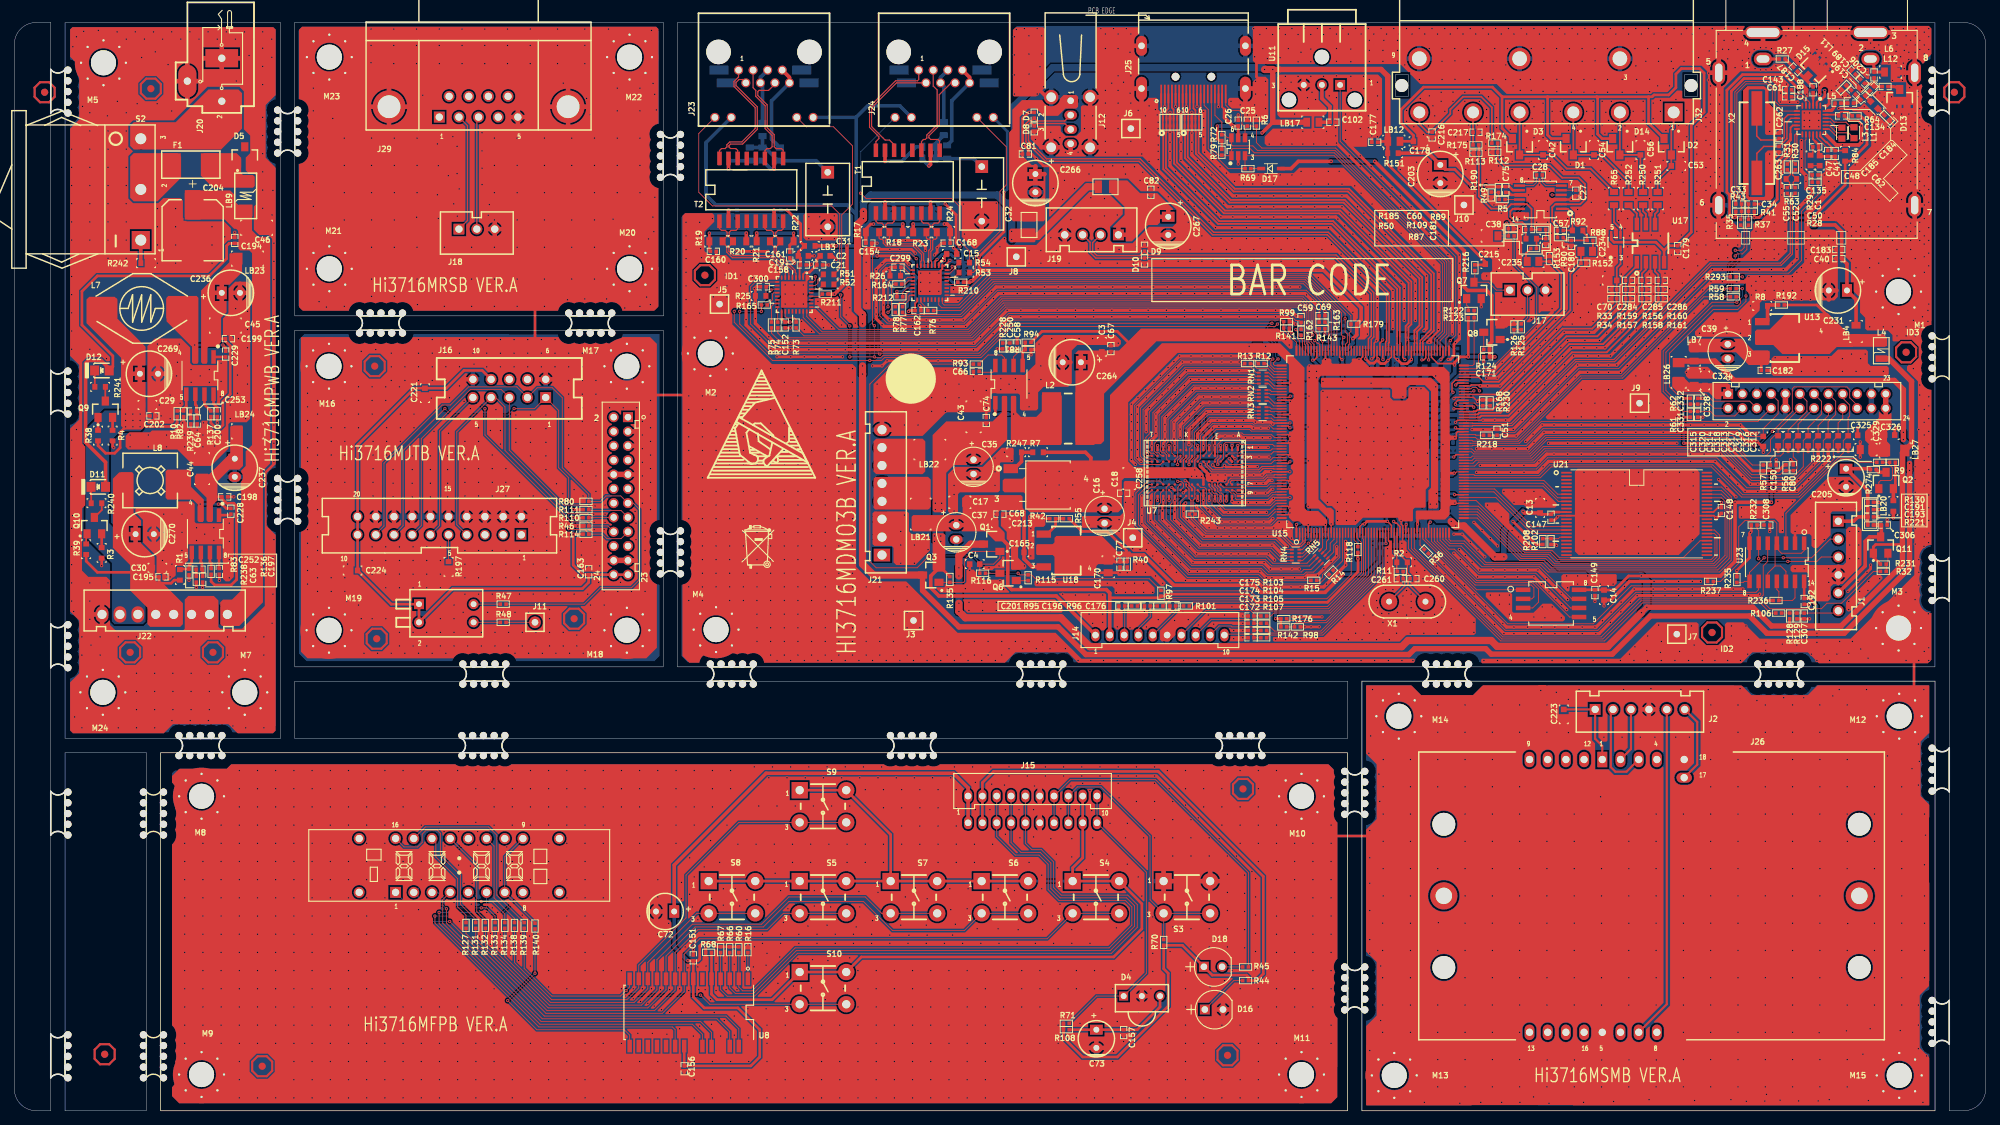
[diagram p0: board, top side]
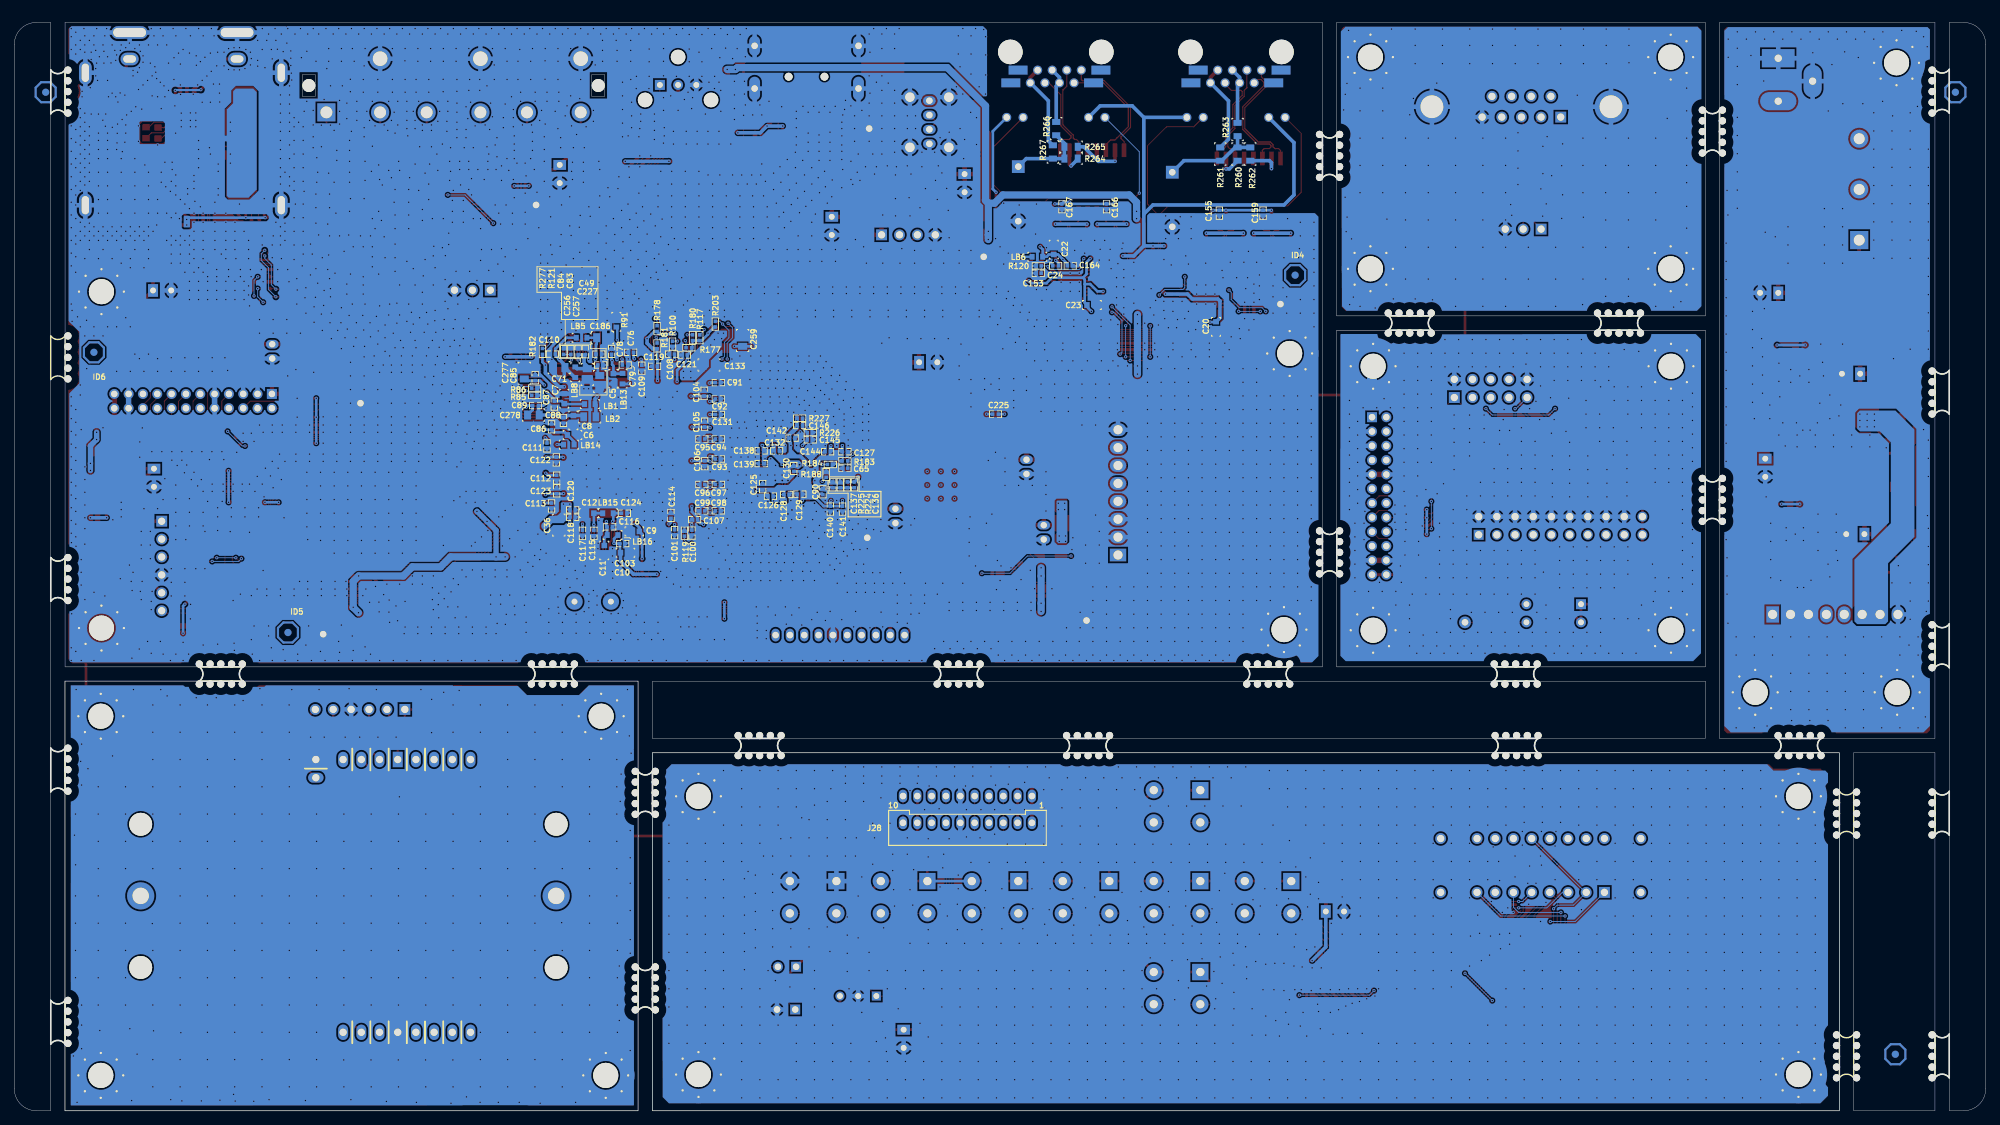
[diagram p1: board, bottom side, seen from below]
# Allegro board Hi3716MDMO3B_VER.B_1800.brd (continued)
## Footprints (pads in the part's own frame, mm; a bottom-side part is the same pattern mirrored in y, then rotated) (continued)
SOT23
  rect 1.016x1.27 smd: 1(-1.016,-1.143) 2(1.016,-1.143) 3(0,1.143)
SOT23A-6L
  rect 0.635x1.27 smd: 1(-0.95,-1.25) 2(0,-1.25) 3(0.95,-1.25) 4(0.95,1.25) 5(0,1.25) 6(-0.95,1.25)
SOT223A
  rect 1.016x2.032 smd: 1(-2.286,-3.15) 2(0,-3.15) 3(2.286,-3.15)
  rect 3.302x2.032 smd: 4(0,3.15)
SPL0707B
  rect 1.651x2.286 smd: 1(-3.302,0) 2(3.302,0)
SPL1209
  rect 4.064x2.794 smd: 1(-5.461,0) 2(5.461,0)
SR0402
  rect 0.508x0.508 smd: 1(-0.406,0) 2(0.406,0)
SR0603
  rect 0.711x0.813 smd: 1(-0.737,0) 2(0.737,0)
SR0805
  rect 0.838x1.143 smd: 1(-0.927,0) 2(0.927,0)
SRN8-0804
  rect 0.279x0.533 smd: 1(-0.762,-0.521) 2(-0.254,-0.521) 3(0.254,-0.521) 4(0.762,-0.521) 5(0.762,0.521) 6(0.254,0.521) 7(-0.254,0.521) 8(-0.762,0.521)
STFM16-50-285
  rect 0.635x1.905 smd: 1(-4.445,-4.381) 2(-3.175,-4.381) 3(-1.905,-4.381) 4(-0.635,-4.381) 5(0.635,-4.381) 6(1.905,-4.381) 7(3.175,-4.381) 8(4.445,-4.381) 9(4.445,4.381) 10(3.175,4.381) 11(1.905,4.381) 12(0.635,4.381) 13(-0.635,4.381) 14(-1.905,4.381) 15(-3.175,4.381) 16(-4.445,4.381)
SW4-PUSH
  rect 2.286x2.286 hole 1.143: 1(-3.25,2.25)
  round 2.286 hole 1.143: 2(3.25,2.25) 3(-3.25,-2.25) 4(3.25,-2.25)
SX2-1205
  rect 4.826x1.524 smd: 1(-4.85,0) 2(4.85,0)
TO-252
  rect 1.27x2.032 smd: 1(-2.285,-3.375) 2(0,-3.375) 3(2.285,-3.375)
  rect 5.715x5.842 smd: 4(0,3.375)
unnamed
  round 1.016 hole 1.016 unplated: (-3,1.4) (-3,-1.4) (-1.5,1.4) (-1.5,-1.4) (0,1.4) (0,-1.4) (1.5,1.4) (1.5,-1.4) (3,1.4) (3,-1.4)
unnamed#2
  round 1.016 smd: 1(0,0)
unnamed#3
  round 1.016 hole 1.016 unplated: (-3,-1.4) (-1.5,-1.4) (0,-1.4) (1.5,-1.4) (3,-1.4)
USB4-2007
  oval 1.27x1.778 hole 0.914: 1(0,0) 2(2.007,0) 3(4.013,0) 4(6.02,0)
  round 2.032 hole 1.321: 5(-0.495,2.718) 6(6.515,2.718) 7(-0.495,-2.718) 8(6.515,-2.718)
VAF9-RF
  round 1.803 hole 1.803 unplated: (-2.45,-3.75) (37.95,-3.75)
  rect 2.54x2.54 hole 1.651: 1(0,0)
  round 2.54 hole 1.651: 2(7.5,0) 4(14,0) 5(21.5,0) 7(28,0) 8(35.5,0)
  round 3.048 hole 2.032: 3(7.5,-7.5) 6(21.5,-7.5) 9(35.5,-7.5)
WBC0119-20R
  rect 0.254x2.591 smd: 1(4.5,5.155) 2(4,5.155) 3(3.5,5.155) 4(3,5.155) 5(2.5,5.155) 6(2,5.155) 7(1.5,5.155) 8(1,5.155) 9(0.5,5.155) 10(0,5.155) 11(-0.5,5.155) 12(-1,5.155) 13(-1.5,5.155) 14(-2,5.155) 15(-2.5,5.155) 16(-3,5.155) 17(-3.5,5.155) 18(-4,5.155) 19(-4.5,5.155)
  oval 1.524x3.302 hole 0.914: 20(-7.25,4.395) 21(7.25,4.395)
  oval 1.524x2.794 hole 0.914: 22(-7.25,-1.565) 23(7.25,-1.565)
  round 1.092 hole 1.092: 24(-2.5,2.745) 25(2.5,2.745)
WBC0212-79T
  rect 1.397x1.397 hole 0.914: 1(0,0)
  round 1.397 hole 0.914: 2(0,-2) 3(2,0) 4(2,-2) 5(4,0) 6(4,-2) 7(6,0) 8(6,-2) 9(8,0) 10(8,-2) 11(10,0) 12(10,-2) 13(12,0) 14(12,-2) 15(14,0) 16(14,-2) 17(16,0) 18(16,-2) 19(18,0) 20(18,-2) 21(20,0) 22(20,-2) 23(22,0) 24(22,-2)
XTAL2-200A
  round 2.286 hole 0.813: 1(-2.54,0) 2(2.54,0)

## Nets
1V2_CTRL: C3.1 C67.2 C71.1 C104.1 C105.1 C106.1 C107.1 C108.1 C109.1 C110.1 C111.1 C112.1 C113.1 C114.1 C117.1 C133.1 C264.1 L2.2 LB5.2 LB8.2 LB14.1 R94.2 U15.1 U15.13 U15.43 U15.60 U15.71 U15.85 U15.111 U15.139 U15.152 U15.174 U15.184 U15.197
1V2_PLL: C11.1 C116.1 LB16.2 U15.37
1V2_STANDBY: C10.1 C77.1 C103.1 C170.1 LB16.1 R40.1 R55.2 U15.32 U18.2(TP-2) U18.4(TP-4)
1V5_DDR3: C16.1 C18.1 C90.1 C91.1 C92.1 C93.1 C94.1 C95.1 C96.1 C97.1 C98.1 C99.1 C100.1 C101.1 C125.1 C126.1 C127.1 C128.1 C129.1 C130.1 C131.1 C132.1 C136.1 C138.1 C139.1 C140.1 C141.1 C142.1 C144.1 C146.1 C258.1 C259.1 R7.2 R183.1 R224.2 R227.2 U7.A1 U7.A8 U7.B2 U7.C1 U7.C9 U7.D2 U7.D9 U7.E9 U7.F1 U7.G7 U7.H2 U7.H9 U7.K2 U7.K8 U7.N1 U7.N9 U7.R1 U7.R9 U10.2 U10.4 U15.5 U15.11 U15.169 U15.175 U15.180 U15.187 U15.190 U15.194 U15.203 U15.206 U15.212 U15.215
1V8_ETH0: C2.1 C21.1 U3.2
1V8_ETH1: C15.1 C24.1 U4.2
3V3: C9.1 C17.1 C37.1 C68.2 C124.1 C165.1 C213.1 J14.2 LB15.1 LB21.2 Q1.2 R97.1 R118.2 R142.2 R176.2 U10.3 U15.23 U15.34 U18.3(TP-3)
3V3_A_ETH0: C19.1 C155.1 C158.1 C159.1 LB3.2 T2.2(TP-2) T2.7(TP-7) U3.3
3V3_A_ETH1: C22.1 C164.1 C166.1 C167.1 LB6.2 T1.2(TP-2) T1.7(TP-7) U4.3
3V3_FP_NB: D18.1 J15.2 J28.2 R44.1 R70.2 R71.2 R108.2
3V3_JTAG_FP: C163.1 C221.1 C224.1 J16.9 J27.10(TP-10) J27.20(TP-20) J30.23 J30.24 R110.2 R111.2 R114.2 S1.1 S1.2
3V3_MOS: C13.1 C14.1 C20.1 C23.1 C36.1 C118.1 C119.1 C120.1 C121.1 C122.1 C123.1 C147.1 C148.1 C149.1 C152.1 C162.1 C171.1 D17.2 J23.10 J23.12 J24.10 J24.12 L4.1 LB1.1 LB2.2 LB3.1 LB6.1 LB13.1 LB27.1 Q1.3 Q11.1 R56.1 R57.1 R61.1 R62.1 R117.2 R123.1 R124.2 R128.2 R141.2 R143.2 R177.2 R178.2 R179.2 R180.2 R181.2 R182.2 R203.2 R208.1 R210.2 R211.2 R212.2 R231.1 R237.1 U3.17 U4.17 U15.47 U15.63 U15.77 U15.115 U15.147 U15.155 U16.8 U21.12(TP-12) U21.37(TP-37)
3V3_PLL: C12.1 C115.1 LB15.2 U15.39
3V3_PWR: C30.1 C195.2 C270.1 J22.4 J22.5 L8.2(TP-2) R1.2 R39.1
3V3_T: C40.1(TP-1) C183.1 C231.1 LB4.2 R41.2 R43.2 R64.2 R84.2 U22.2 U22.11
3V3_TS: C325.1 C326.1 C329.1 J34.23 J34.24 LB27.2
5V0: C35.1 C43.1 C74.1 J14.1 LB22.2 Q3.2 R135.1 U19.2
5V0_MOS: C26.1 C177.1 C192.2 C215.1 D19.1 D20.2 J25.18 LB7.2 LB12.2 LB17.1 LB20.1 LB26.2 Q3.3 R72.2 R79.2 R151.1 R216.1 U14.5 U23.14
5V0_PWR: C29.1 C202.2 C269.1 J22.6 J22.7 L7.2 R10.2 R38.1
5V0_TS: C324.1 C328.1 J34.1 LB26.1
5V0_VBUS0: C81.1 C266.1 D19.2 J12.1
5V0_VBUS1: C82.1 C267.1 D20.1 J19.1
5V_FP_NB: C72.1 C151.2 C156.1 J15.1 J28.1 R60.2 R66.2 R67.2 U8.7 U8.21
5V_VIDEO: C178.1 C179.1 D1.2 D2.2 D3.2 D14.2 LB12.1 U12.5 U17.4
12V0_PWR: C46.1 C194.2 C204.1 D11.1(TP-1) D12.1(TP-1) J22.1 LB9.2(TP-2) LB23.1 LB24.1
AVCC12_HDMI: C83.1 C84.1 C227.1 C256.1 C257.1 LB8.1 U15.117
AVDD12_QAM: C6.1 C86.1 LB14.2 U15.86
AVDD33_ADAC: C7.1 C87.1 LB1.2 U15.103
AVDD33_USB: C5.1 C76.1 C78.1 C79.1 LB13.2 U15.129 U15.134 U15.138
AVDD33_VDAC: C8.1 C88.1 C89.1 C278.1 LB2.1 U15.96
AVDD_HDMI: C49.1 C186.1 LB5.1 U15.125
GND: C1.2 C2.2 C3.2 C4.2 C5.2 C6.2 C7.2 C8.2 C9.2 C10.2 C11.2 C12.2 C13.2 C14.2 C15.2 C16.2 C17.2 C18.2 C19.2 C20.2 C21.2 C22.2 C23.2 C24.2 C25.2 C26.2 C27.1(TP-1) C31.2 C32.2 C33.2 C34.2 C35.2 C36.2 C37.2 C38.2 C39.2 C40.2(TP-2) C41.1 C42.2 C43.2 C47.2 C49.2 C50.2 C51.2 C53.2 C54.2 C56.2 C58.2 C59.2 C61.1 C65.2 C66.2 C67.1 C68.1 C69.2 C70.2 C71.2 C72.2 C73.2 C74.2 C75.2 C76.2 C77.2 C78.2 C79.2 C80.2 C81.2 C82.2 C83.2 C84.2 C85.2 C86.2 C87.2 C88.2 C90.2 C91.2 C92.2 C93.2 C94.2 C95.2 C96.2 C97.2 C98.2 C99.2 C100.2 C101.2 C102.2 C103.2 C104.2 C105.2 C106.2 C107.2 C108.2 C109.2 C110.2 C111.2 C112.2 C113.2 C114.2 C115.2 C116.2 C117.2 C118.2 C119.2 C120.2 C121.2 C122.2 C123.2 C124.2 C125.2 C126.2 C127.2 C128.2 C129.2 C130.2 C131.2 C132.2 C133.2 C134.1 C135.2 C137.2 C138.2 C139.2 C140.2 C141.2 C142.2 C143.1 C144.2 C145.2 C147.2 C148.2 C149.2 C150.2 C151.1 C152.2 C153.2 C154.1 C155.2 C156.2 C157.2 C158.2 C159.2 C160.1 C161.2 C162.2 C163.2 C164.2 C165.2 C166.2 C167.2 C168.2 C170.2 C171.2 C172.2 C173.2 C174.2 C175.2 C176.2 C177.2 C178.2 C179.2 C180.2 C181.2 C182.2 C183.2 C186.2 C191.2 C192.1 C193.2 C196.2 C201.2 C203.2 C205.2 C213.2 C215.2 C216.2 C217.2 C221.2 C223.2 C224.2 C227.2 C231.2 C256.2 C257.2 C258.2 C259.2 C260.2 C261.2 C262.2 C263.2 C264.2 C266.2 C267.2 C277.2 C284.2 C285.2 C286.2 C299.2 C300.2 C306.2 C307.2 C308.2 C312.2 C313.2 C314.2 C315.2 C316.2 C317.2 C318.2 C319.2 C320.2 C324.2 C325.2 C326.2 C328.2 C329.2 C331.2 C332.2 D1.1 D2.1 D3.1 D4.2(TP-2) D7.2 D8.2 D9.2 D10.2 D13.1 D13.2 D14.1 D15.1 D15.2 D16.2 J1.4 J2.4 J3.1(TP-1) J4.1(TP-1) J5.1(TP-1) J6.1(TP-1) J7.1(TP-1) J8.1(TP-1) J9.1(TP-1) J10.1(TP-1) J12.4 J12.5 J12.6 J12.7 J12.8 J13.3 J13.4 J13.5 J13.6 J13.7 J13.8 J14.6 J15.6 J16.6 J16.10 J17.3 J18.3 J19.4 J21.2 J21.3 J21.8 J25.2 J25.5 J25.8 J25.11 J25.17 J25.20 J25.21 J25.22 J25.23 J26.5 J26.18 J27.11(TP-11) J27.12(TP-12) J27.13(TP-13) J27.14(TP-14) J27.15(TP-15) J27.16(TP-16) J27.17(TP-17) J27.18(TP-18) J27.19(TP-19) J28.6 J29.5 J29.10 J29.11 J30.3 J30.5 J30.9 J30.10 J30.21 J30.22 J32.3 J32.6 J32.9 J34.3 J34.5 J34.9 J34.10 J34.21 J34.22 L6.1 L9.1 L10.1 L11.1 M1.1 M1.2 M1.3 M1.4 M1.5 M1.6 M1.7 M1.8 M2.1 M2.2 M2.3 M2.4 M2.5 M2.6 M2.7 M2.8 M3.1 M3.2 M3.3 M3.4 M3.5 M3.6 M3.7 M3.8 M4.1 M4.2 M4.3 M4.4 M4.5 M4.6 M4.7 M4.8 M8.1 M8.2 M8.3 M8.4 M8.5 M8.6 M8.7 M8.8 M9.1 M9.2 M9.3 M9.4 M9.5 M9.6 M9.7 M9.8 M10.1 M10.2 M10.3 M10.4 M10.5 M10.6 M10.7 M10.8 M11.1 M11.2 M11.3 M11.4 M11.5 M11.6 M11.7 M11.8 M12.1 M12.2 M12.3 M12.4 M12.5 M12.6 M12.7 M12.8 M13.1 M13.2 M13.3 M13.4 M13.5 M13.6 M13.7 M13.8 M14.1 M14.2 M14.3 M14.4 M14.5 M14.6 M14.7 M14.8 M15.1 M15.2 M15.3 M15.4 M15.5 M15.6 M15.7 M15.8 M16.1 M16.2 M16.3 M16.4 M16.5 M16.6 M16.7 M16.8 M17.1 M17.2 M17.3 M17.4 M17.5 M17.6 M17.7 M17.8 M18.1 M18.2 M18.3 M18.4 M18.5 M18.6 M18.7 M18.8 M19.1 M19.2 M19.3 M19.4 M19.5 M19.6 M19.7 M19.8 M20.1 M20.2 M20.3 M20.4 M20.5 M20.6 M20.7 M20.8 M21.1 M21.2 M21.3 M21.4 M21.5 M21.6 M21.7 M21.8 M22.1 M22.2 M22.3 M22.4 M22.5 M22.6 M22.7 M22.8 M23.1 M23.2 M23.3 M23.4 M23.5 M23.6 M23.7 M23.8 Q6.2 Q7.2 Q8.2 R6.2 R8.2 R16.2 R25.2 R26.2 R33.1 R34.1 R40.2 R42.1 R46.1 R49.1 R68.1 R80.1 R81.1 R85.2 R86.2 R91.1 R98.2 R99.2 R100.2 R102.2 R112.2 R113.2 R119.2 R120.2 R121.2 R126.1 R129.1 R130.1 R152.2 R153.2 R156.1 R157.1 R158.1 R159.1 R160.1 R161.1 R168.1 R184.2 R185.2 R188.1 R197.2 R225.1 R226.1 R228.2 R230.1 R232.2 R235.2 R236.2 R247.2 R277.2 S3.1(TP-1) S3.2(TP-2) U2.3 U2.8 U3.1 U3.33 U4.1 U4.33 U5.3 U5.8 U7.A9 U7.B1 U7.B3 U7.B9 U7.D1 U7.D8 U7.E1 U7.E2 U7.E8 U7.F9 U7.G1 U7.G8 U7.G9 U7.J2 U7.J8 U7.M1 U7.M9 U7.P1 U7.P9 U7.T1 U7.T9 U8.22 U8.25 U8.28 U9.1 U9.4 U9.10 U9.14 U11.3(TP-3) U12.1 U12.2 U14.2 U15.2 U15.33 U15.38 U15.89 U15.93 U15.97 U15.101 U15.122 U15.128 U15.132 U15.135 U15.183 U15.200 U15.209 U15.217 U16.4 U17.5 U19.4 U19.9 U21.13(TP-13) U21.36(TP-36) U22.16 U22.25 U23.2 U23.7
VCC_SCI: C191.1 C193.1 C205.1 J1.1 R130.2 R221.1 R274.2
VCC_SMT: C223.1 J2.1 J26.1
VDD_AUDIO: C75.1 C203.1 R151.2 R190.2 U9.9
AUDIO_L: C216.1 J32.8 R174.1
AUDIO_OUTL: C234.1 R152.1 U15.104
AUDIO_OUTR: C235.2 R153.1 U15.105
AUDIO_R: C217.1 J32.7 R175.2
CLK_50M_PHY0: C59.1 R162.2 U3.9
CLK_50M_PHY1: C69.1 R163.2 U4.9
CLK_SCI_NB: J2.2 J26.3
CVBS: C70.1 R33.2 R34.2 U12.3 U15.98
CVBS_OUT: C42.1 D3.3 J32.5 R65.1
DATA_SCI_NB: J2.5 J26.7
DDR_ADDR0: RN2.8 U15.172
DDR_ADDR0_A: RN2.1 U7.N3
DDR_ADDR1: R14.1 U15.17
DDR_ADDR1_A: R14.2 U7.P7
DDR_ADDR2: R12.1 U15.165
DDR_ADDR2_A: R12.2 U7.P3
DDR_ADDR3: RN2.7 U15.173
DDR_ADDR3_A: RN2.2 U7.N2
DDR_ADDR4: RN5.8 U15.10
DDR_ADDR4_A: RN5.1 U7.P8
DDR_ADDR5: RN1.5 U15.171
DDR_ADDR5_A: RN1.4 U7.P2
DDR_ADDR6: RN5.7 U15.12
DDR_ADDR6_A: RN5.2 U7.R8
DDR_ADDR7: RN1.6 U15.170
DDR_ADDR7_A: RN1.3 U7.R2
DDR_ADDR8: RN5.6 U15.14
DDR_ADDR8_A: RN5.3 U7.T8
DDR_ADDR9: RN1.8 U15.167
DDR_ADDR9_A: RN1.1 U7.R3
DDR_ADDR10: RN4.7 U15.7
DDR_ADDR10_A: RN4.2 U7.L7
DDR_ADDR11: RN5.5 U15.15
DDR_ADDR11_A: RN5.4 U7.R7
DDR_ADDR12: RN4.5 U15.9
DDR_ADDR12_A: RN4.4 U7.N7
DDR_ADDR13: R13.1 U15.166
DDR_ADDR13_A: R13.2 U7.T3
DDR_ADDR14: R15.1 U15.16
DDR_ADDR14_A: R15.2 U7.T7
DDR_BA0: RN2.6 U15.176
DDR_BA0_A: RN2.3 U7.M2
DDR_BA1: RN4.6 U15.8
DDR_BA1_A: RN4.3 U7.N8
DDR_BA2: RN2.5 U15.177
DDR_BA2_A: RN2.4 U7.M3
DDR_CASN: RN3.6 U15.181
DDR_CASN_A: RN3.3 U7.K3
DDR_CKE: R119.1 RN4.8 U15.6
DDR_CKE_A: RN4.1 U7.K9
DDR_CKN1: R243.2 U7.K7 U15.4
DDR_CKP1: R243.1 U7.J7 U15.3
DDR_CS0N_A: R184.1 U7.L2
DDR_DM0: U7.E7 U15.210
DDR_DM1: U7.D3 U15.191
DDR_DQ0: U7.E3 U15.189
DDR_DQ1: U7.F7 U15.211
DDR_DQ2: U7.F2 U15.188
DDR_DQ3: U7.F8 U15.213
DDR_DQ4: U7.H3 U15.185
DDR_DQ5: U7.H8 U15.216
DDR_DQ6: U7.G2 U15.186
DDR_DQ7: U7.H7 U15.214
DDR_DQ8: U7.D7 U15.205
DDR_DQ9: U7.C3 U15.196
DDR_DQ10: U7.C8 U15.208
DDR_DQ11: U7.C2 U15.192
DDR_DQ12: U7.A7 U15.204
DDR_DQ13: U7.A2 U15.193
DDR_DQ14: U7.B8 U15.207
DDR_DQ15: U7.A3 U15.195
DDR_DQSN0: U7.G3 U15.199
DDR_DQSN1: U7.B7 U15.202
DDR_DQSP0: U7.F3 U15.198
DDR_DQSP1: U7.C7 U15.201
DDR_ODT: RN3.7 U15.179
DDR_ODT_A: RN3.2 U7.K1
DDR_RASN: RN3.5 U15.182
DDR_RASN_A: RN3.4 U7.J3
DDR_RSTN: RN1.7 U15.168
DDR_RSTN_A: C65.1 R183.2 RN1.2 U7.T2
DDR_VREF_CA: C136.2 C137.1 R224.1 R225.2 U7.M8
DDR_VREF_DQ: C145.1 C146.2 R226.2 R227.1 U7.H1
DDR_WEN: RN3.8 U15.178
DDR_WEN_A: RN3.1 U7.L3
DETECT_SCI_NB: J2.6 J26.17
DM_USB0: D7.1 J12.2 U15.131
DM_USB1: D9.1 J19.2 U15.136
DP_USB0: D8.1 J12.3 U15.130
DP_USB1: D10.1 J19.3 U15.137
ETH_RSTN: C153.1 R120.1 U3.32 U4.32 U15.164
FP_CLK: R96.2 U15.24
FP_CLK_NB: J15.4 J28.4 R66.1 U8.3
FP_IO: R95.2 U15.22
FP_IO_NB: J15.3 J28.3 R60.1 U8.2
FP_IR_NB: D4.1(TP-1) J15.10 J28.10 R71.1
FP_STB: R101.2 U15.25
FP_STB_NB: J15.5 J28.5 R67.1 U8.4
FUNC_SEL: R118.1 U15.21
HDMI_REXT: R121.1 R277.1 U15.116
IF_AGC: R218.2 U15.84
IR_IN: R107.2 U15.31
JTAG_SEL: R117.1 U15.161
KEY_INT: R105.2 U15.30
KEY_INT_NB: J15.9 J28.9 R68.2 S4.1(TP-1) S4.2(TP-2) S5.1(TP-1) S5.2(TP-2) S6.1(TP-1) S6.2(TP-2) S7.1(TP-1) S7.2(TP-2) S8.1(TP-1) S8.2(TP-2) S9.1(TP-1) S9.2(TP-2) S10.1(TP-1) S10.2(TP-2) U8.5
LED0_BASE: J23.9 R51.2
LED0_LINK_ACT: J23.11 R52.2
LED1_BASE: J24.9 R54.2
LED1_LINK_ACT: J24.11 R53.2
LED_CLK: R176.1 U15.27
LED_DATA: R98.1 R142.1 U15.28
LED_STANDBY: R103.2 U15.26
LED_STANDBY_NB: J15.7 J28.7 R45.2
MDCK: R99.1 R141.1 R164.1 R165.1 U15.162
MDIO: R203.1 U3.11 U4.11 U15.163
MUTE_CTL: R50.1 U15.106
NF_ALE: U15.64 U21.17(TP-17)
NF_CLE: U15.65 U21.16(TP-16)
NF_CS0N: U15.66 U21.9(TP-9)
NF_DQ0: U15.61 U21.29(TP-29)
NF_DQ1: U15.59 U21.30(TP-30)
NF_DQ2: U15.58 U21.31(TP-31)
NF_DQ3: U15.57 U21.32(TP-32)
NF_DQ4: U15.56 U21.41(TP-41)
NF_DQ5: U15.55 U21.42(TP-42)
NF_DQ6: U15.54 U21.43(TP-43)
NF_DQ7: U15.53 U21.44(TP-44)
NF_RDY0: U15.68 U21.7(TP-7)
NF_REN: U15.67 U21.8(TP-8)
NF_WEN: U15.62 U21.18(TP-18)
NF_WP: R102.1 R208.2 U21.19(TP-19)
P_GND: C29.2 C30.2 C44.2 C45.2 C46.2 C63.2 C64.2 C194.1 C195.1 C197.2 C198.2 C199.2 C200.2 C202.1 C204.2 C236.2 C237.2 C269.2 C270.2 D5.2 J20.1 J20.3 J22.2 J22.3 J22.8 M5.1 M5.2 M5.3 M5.4 M5.5 M5.6 M5.7 M5.8 M7.1 M7.2 M7.3 M7.4 M7.5 M7.6 M7.7 M7.8 M24.1 M24.2 M24.3 M24.4 M24.5 M24.6 M24.7 M24.8 R3.2 R4.2 R82.2 R83.2 R238.2 R239.2 R242.1 U6.4 U6.9 U20.4 U20.9
PB: C284.1 R157.2 R159.2 U15.92 U17.1
PB_OUT: C54.1 D1.3 J32.4 R252.1
PHY1_AD1: R212.1 U4.14
PR: C286.1 R160.2 R161.2 U15.90 U17.3
PR_OUT: C53.1 D2.3 J32.1 R251.1
PWR_BUTTON: R104.2 U15.29
PWR_BUTTON_NB: J15.8 J28.8 R70.1 S3.3(TP-3) S3.4(TP-4)
QAM_SCL: R35.1 R58.1 U15.82
QAM_SDA: R37.1 R59.1 U15.83
QAM_VINN: C55.2 U15.88
QAM_VINP: C52.2 U15.87
REXT_VDAC: R168.2 R230.2 U15.95
RF_IN: C206.1 J13.2 L6.2
RF_OUT: J13.1 R27.1
RST_SCI_NB: J2.3 J26.2
RX+_PHY0: R21.2 T2.6(TP-6) U3.5
RX+_PHY1: R23.2 T1.6(TP-6) U4.5
RX-_PHY0: R22.2 T2.8(TP-8) U3.4
RX-_PHY1: R24.2 T1.8(TP-8) U4.4
RXD0_RMII0: R74.1 U15.158
RXD0_RMII1: R77.1 U15.149
RXD1_RMII0: R75.1 U15.159
RXD1_RMII1: R78.1 U15.150
RXDV_RMII0: R73.1 U15.157
RXDV_RMII1: R76.1 U15.148
SFC_CLK: U15.51 U16.6
SFC_CS1N: U15.46 U16.1
SFC_DIO: U15.50 U16.5
SFC_DOI: U15.48 U16.2
SFC_HOLDN_IO3: U15.52 U16.7
SFC_WPN_IO2: U15.49 U16.3
SIM0_CARD_I/O: C306.1 J1.5 Q11.3 R221.2
SIM0_CLK: R36.1 U15.44
SIM0_CLK_OUT: J1.2 R235.1 U23.8
SIM0_DATA: R32.1 U15.41
SIM0_DET: R106.1 U15.40
SIM0_PWREN: R237.2 U15.45 U23.1 U23.4 U23.10 U23.12
SIM0_PWREN_CTL: R222.1 U23.3
SIM0_RST: U15.42 U23.5
SIM0_RST_OUT: C308.1 J1.3 R232.1 U23.6
SPDIF_OUT: R182.1 U11.1(TP-1) U15.109
STANDBY_PWROFF: R93.2 R97.2 R115.1 U15.20
TCK_ICE_FP: J16.5 J27.6(TP-6) J30.18 R46.2
TDI_ICE_FP: J16.1 J27.8(TP-8) J30.17 R114.1
TDO_ICE_FP: J16.4 J27.4(TP-4) J30.16 R110.1
TMDS_CEC: J25.13 R69.2 U14.3 U15.114
TMDS_CLK_N: J25.12 U2.5 U2.6 U15.118
TMDS_CLK_P: J25.10 U2.4 U2.7 U15.119
TMDS_D0_N: J25.9 U2.2 U2.9 U15.120
TMDS_D0_P: J25.7 U2.1 U2.10 U15.121
TMDS_D1_N: J25.6 U5.5 U5.6 U15.123
TMDS_D1_P: J25.4 U5.4 U5.7 U15.124
TMDS_D2_N: J25.3 U5.2 U5.9 U15.126
TMDS_D2_P: J25.1 U5.1 U5.10 U15.127
TMDS_HOTPLUG: C25.1 J25.19 R6.1 U14.4 U15.110
TMDS_SCL: J25.15 R79.1 U14.1 U15.113
TMDS_SDA: J25.16 R72.1 U14.6 U15.112
TMS_ICE_FP: J16.3 J27.7(TP-7) J30.15 R111.1
TRST_ICE_FP: J16.2 J27.9(TP-9) J30.13 R47.1 R80.2
TS_RESET: C51.1 R28.2 R218.1 R293.1
TS_SCL: C332.1 J34.2 R58.2 R62.2
TS_SDA: C331.1 J34.4 R59.2 R61.2
TSI0_CLK: C315.1 J34.7 U15.80
TSI0_D0: C312.1 J34.17 U15.69
TSI0_D1: C316.1 J34.18 U15.70
TSI0_D2: C319.1 J34.15 U15.72
TSI0_D3: C317.1 J34.16 U15.73
TSI0_D4: C313.1 J34.13 U15.74
TSI0_D5: C80.1 C318.1 J34.14 R56.2 U15.75
TSI0_D6: C150.1 C314.1 J34.11 R57.2 U15.76
TSI0_D7: C320.1 J34.12 U15.78
TSI0_SYNC: J34.8 U15.81
TSI0_VALID: J34.20 U15.79
TX+_PHY0: R19.1 T2.1(TP-1) U3.7
TX+_PHY1: R17.1 T1.1(TP-1) U4.7
TX-_PHY0: R20.1 T2.3(TP-3) U3.6
TX-_PHY1: R18.1 T1.3(TP-3) U4.6
TXD0_RMII0: R177.1 U3.24 U15.154
TXD0_RMII1: R178.1 U4.24 U15.145
TXD1_RMII0: R100.1 R143.1 U3.25 U15.153
TXD1_RMII1: R179.1 U4.25 U15.144
TXEN_RMII0: R180.1 U3.23 U15.156
TXEN_RMII1: R181.1 U4.23 U15.146
UART0_RXD: Q8.3 R124.1 U15.107
UART0_TXD: R122.2 R123.2 U15.108
USB_REXT: R91.2 U15.133
VDAC_COMP: C89.2 C278.2 U15.94
VREF_ADAC: C85.1 C277.1 U15.102
XIN: C260.1 R2.2 U15.36 X1.1(TP-1)
XOUT: R2.1 R11.2 U15.35
Y: C285.1 R156.2 R158.2 U15.91 U17.2
Y_OUT: C56.1 D14.3 J32.2 R250.1
$4N8: R7.1 R247.1 U10.1
$4N9: C225.1 U19.1
$4N10: C225.2 L2.1 U19.3
$4N23: J21.6 J21.7 LB22.1
$4N24: J21.4 J21.5 LB21.1
$4N25: R93.1 U19.7
$4N89: C58.1 C250.1 U19.6
$4N91: C66.1 U19.8
$4N92: C250.2 R228.1
$4N93: R81.2 R94.1 U19.5
$4N348: R42.2 R55.1 U18.1(TP-1)
$5N20: C4.1 Q1.1 Q3.1 R116.1 R135.2
$5N64: Q6.3 R116.2
$5N66: Q6.1 R115.2
$6N108: R162.1 U15.160
$6N109: R163.1 U15.151
$6N160: C261.1 R11.1 X1.2(TP-2)
$6N395: C201.1 J14.3 R95.1
$6N397: C196.1 J14.4 R96.1
$6N399: C176.1 J14.5 R101.1
$6N401: C175.1 J14.7 R103.1
$6N403: C174.1 J14.8 R104.1
$6N405: C173.1 J14.9 R105.1
$6N407: C172.1 J14.10 R107.1
$7N340: R85.1 U15.99
$7N342: R86.1 U15.100
$10N107: R188.2 U7.L8
$11N254: J34.6 R293.2
$12N2: C300.1 R25.1 U3.10
$12N8: J23.7 J23.8 R261.2
$12N9: R262.2 T2.15(TP-15)
$12N10: R260.2 T2.10(TP-10)
$12N32: C154.2 R17.2 R18.2
$12N40: R54.1 U4.31
$12N41: R51.1 U3.31
$12N46: R53.1 U4.30
$12N48: R210.1 U4.28
$12N50: R76.2 U4.18
$12N55: R78.2 U4.15
$12N65: R211.1 U3.28
$12N67: R52.1 U3.30
$12N71: R74.2 U3.16
$12N73: C160.2 R19.2 R20.2
$12N75: R77.2 U4.16
$12N76: R75.2 U3.15
$12N77: R73.2 U3.18
$12N87: C161.1 R21.1 R22.1
$12N91: J23.6 T2.9(TP-9)
$12N113: J23.3 T2.11(TP-11)
$12N114: C31.1 R260.1 R261.1 R262.1 R263.1
$12N115: J23.1 T2.16(TP-16)
$12N116: J23.2 T2.14(TP-14)
$12N117: J23.4 J23.5 R263.2
$12N122: R265.2 T1.15(TP-15)
$12N123: R264.2 T1.10(TP-10)
$12N124: J24.6 T1.9(TP-9)
$12N125: J24.3 T1.11(TP-11)
$12N126: J24.2 T1.14(TP-14)
$12N127: J24.1 T1.16(TP-16)
$12N128: J24.7 J24.8 R267.2
$12N129: J24.4 J24.5 R266.2
$12N133: C299.1 R26.1 U4.10
$12N261: C168.1 R23.1 R24.1
$12N279: C32.1 R264.1 R265.1 R266.1 R267.1
$12N307: R164.2 U4.12
$12N314: R165.2 U3.12
$13N49: Q7.1 R122.1
$13N52: J17.1 Q7.3 R216.2
$13N54: Q8.1 R125.1 R126.2
$13N57: J17.2 R125.2
$14N137: D17.1 R69.1
$15N244: R251.2 U17.6
$15N245: R250.2 U17.7
$15N246: R252.2 U17.8
$15N325: R65.2 U12.4
$16N143: R5.1 U9.11
$16N153: C60.1 R89.1 R113.1 R175.1 U9.12
$16N171: R5.2 R49.2 R190.1
$16N236: C27.2(TP-2) U9.6
$16N249: C57.2 R90.2 R112.1 R174.2 U9.3
$16N268: C180.1 R88.2 R90.1 R92.1
$16N273: C57.1 R92.2 U9.2
$16N280: C234.2 R88.1
$16N296: C38.1 R50.2 R185.1 U9.5
$16N316: C28.1(TP-1) U9.7
$16N318: C28.2(TP-2) U9.8
$16N327: C60.2 R109.1 U9.13
$16N332: C181.1 R87.1 R89.2 R109.2
$16N368: C235.1 R87.2
$16N387: C102.1 LB17.2 U11.2(TP-2)
$17N94: R30.1 U22.13
$17N123: R8.1 R192.1 U13.1(TP-1)
$17N126: C39.1 C182.1 LB7.1 U13.3(TP-3)
$17N128: L4.2 LB4.1 R192.2 U13.2(TP-2) U13.4(TP-4)
$17N139: C52.1 R30.2 R63.2
$17N140: C55.1 R31.2 R63.1
$17N221: C50.1 R28.1 U22.14
$17N517: C47.1 U22.17
$17N528: C1.1 R29.2
$17N535: C135.1 R29.1 U22.15
$17N549: R31.1 U22.12
$17N569: C262.1 U22.8 X2.1(TP-1)
$17N571: C263.1 U22.9 X2.2(TP-2)
$17N582: C33.1 R35.2 R43.1 U22.6
$17N583: C34.1 R37.2 R41.1 U22.7
$17N610: C61.2 U22.5
$17N615: C143.2 U22.4
$17N624: C187.2 C188.1 D15.3
$17N628: C188.2 U22.3
$17N631: C187.1 R27.2
$17N637: L3.1 U22.19
$17N639: L3.2 U22.21
$17N641: L1.1 U22.20
$17N643: L1.2 U22.22
$17N657: L5.2 U22.24
$17N674: C48.2 L5.1
$17N676: C48.1 C185.2 C190.1
$17N678: C184.1 C189.1 C206.2 L12.2
$17N683: C62.2 L9.2
$17N685: C190.2 L10.2
$17N699: C134.2 R64.1 U22.23
$17N726: C62.1 C184.2 C185.1
$17N732: C189.2 L11.2
$17N744: C41.2 R84.1 U22.18
$17N767: D13.3 L12.1
$18N11: Q11.2 R32.2 R231.2
$18N28: R236.1 U23.11 U23.13
$18N32: R36.2 U23.9
$18N33: Q2.1 R9.2 R222.2
$18N35: LB20.2 Q2.2 R9.1
$18N36: Q2.3 R274.1
$18N96: C307.1 J1.6 R106.2 R128.1 R129.2
$19N8: C44.1 C198.1 C237.1 LB24.2 R136.1 U6.2
$19N10: C45.1 C199.1 C236.1 LB23.2 R137.1 U20.2
$19N25: D12.2(TP-2) R241.1
$19N26: Q9.3 R241.2
$19N27: Q9.2 R4.1
$19N28: Q9.1 R38.2
$19N31: Q10.1 R39.2
$19N32: Q10.2 R3.1
$19N33: Q10.3 R240.2
$19N34: D11.2(TP-2) R240.1
$19N37: D5.1 F1.2(TP-2) LB9.1(TP-1)
$19N38: F1.1(TP-1) S2.2
$19N39: J20.2 S2.3
$19N40: R242.2 S2.1
$19N44: C63.1 C252.1 U6.6
$19N56: C197.1 U6.8
$19N57: R136.2 U6.7
$19N58: C228.1 U6.1
$19N59: C252.2 R238.1
$19N60: R1.1 R83.1 U6.5
$19N61: C228.2 L8.1(TP-1) U6.3
$19N64: C229.2 L7.1 U20.3
$19N65: R10.1 R82.1 U20.5
$19N66: C253.2 R239.1
$19N67: C229.1 U20.1
$19N68: R137.2 U20.7
$19N69: C200.1 U20.8
$19N80: C64.1 C253.1 U20.6
$20N482: D16.1 R44.2
$20N487: D18.2 R45.1
$20N488: D6.8 U8.20
$20N489: D6.6 U8.23
$20N490: D6.4 U8.24
$20N491: D6.2 D6.12 U8.26
$20N492: D6.1 U8.27
$20N493: D6.7 D6.9 R140.2
$20N494: D6.14 R127.2
$20N495: R140.1 U8.15
$20N496: R139.1 S10.3(TP-3) S10.4(TP-4) U8.14
$20N502: R16.1 U8.1
$20N503: D6.16 R131.2
$20N504: R131.1 S5.3(TP-3) S5.4(TP-4) U8.9
$20N505: D6.13 R132.2
$20N506: R132.1 S6.3(TP-3) S6.4(TP-4) U8.10
$20N507: D6.3 R133.2
$20N508: R133.1 S7.3(TP-3) S7.4(TP-4) U8.11
$20N509: D6.5 R134.2
$20N510: R134.1 S8.3(TP-3) S8.4(TP-4) U8.12
$20N511: D6.11 R138.2
$20N512: R138.1 S9.3(TP-3) S9.4(TP-4) U8.13
$20N513: D6.15 R139.2
$20N555: R127.1 S4.3(TP-3) S4.4(TP-4) U8.8
$20N573: C73.1 C157.1 D4.3(TP-3) R108.1
$21N8: J18.1 J29.2
$21N51: J18.2 J29.3
$21N65: J27.5(TP-5) R197.1
$21N352: R47.2 S1.4
$21N355: R48.1 S1.3
$21N358: J11.1(TP-1) R48.2

Pads without a net: D5 3; D6 10; ID1 1; ID2 1; ID3 1; ID4 1; ID5 1; ID6 1; J16 7 8; J21 1; J25 14 24 25; J26 4 6 8 9 10 11 12 13 14 15 16 19 20; J27 1 2 3; J29 1 4 6 7 8 9; J30 1 2 4 6 7 8 11 12 14 19 20; J34 19; NOREF#2 1; NOREF#4 1; NOREF#6 1; NOREF#13 1; NOREF#15 1; NOREF#18 1; NOREF#19 1; NOREF#30 1; NOREF#33 1; NOREF#34 1; NOREF#43 1; NOREF#44 1; NOREF#54 1; NOREF#55 1; NOREF#56 1; T1 4 5 12 13; T2 4 5 12 13; U3 8 13 14 19 20 21 22 26 27 29; U4 8 13 19 20 21 22 26 27 29; U7 J1 J9 L1 L9 M7; U8 6 16 17 18 19; U15 18 19 140 141 142 143; U21 1 2 3 4 5 6 10 11 14 15 20 21 22 23 24 25 26 27 28 33 34 35 38 39 40 45 46 47 48; U22 1 10

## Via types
v1: diameter 0.457, hole 0.203, TOP to BOTTOM, 6056 vias
v2: diameter 0.508, hole 0.254, TOP to BOTTOM, 14 vias

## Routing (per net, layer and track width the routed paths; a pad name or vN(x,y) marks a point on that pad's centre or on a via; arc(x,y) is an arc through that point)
1V2_CTRL: length 64.9
  TOP w0.127: U15.71 201.34,89.23 201.16,89.05 v1(201,89.05)
  TOP w0.203: U15.152 v1(183.02,104.91) ; v1(178.97,81.87) 178.97,81.87 U15.1 ; v1(199.13,104.94) 199.42,105.22 U15.111 ; v1(178.11,99.81) 177.94,99.63 U15.174 ; U15.13 v1(183.82,81.95) ; v1(178.06,90.64) 177.85,90.43 U15.197 ; v1(195.87,81.92) 195.82,81.87 U15.43 ; v1(178.06,95.39) 177.82,95.63 U15.184 ; U15.85 201.47,94.83 201.3,94.66 201.3,94.15 201.08,93.93 v1(201.08,93.99) ; U15.139 188.22,105.28 187.92,104.99 187.92,104.96 v1(187.7,104.96) ; U15.60 201.22,84.83
  TOP w0.381: 155.48,107.32 153.96,108.85 143.44,108.85 R94.2 ; v1(195.87,81.92) 195.87,82.69 ; v1(201,89.05) 200.2,89.05
  TOP w0.635: C264.1 149.96,104.53 ; C264.1 148.88,105.8 ; C264.1 148.88,103.26
  BOTTOM w0.381: C114.1 183.52,82.17 183.74,81.95 v1(183.82,81.95) ; v1(178.11,99.81) C104.1 v1(180.73,99.81) ; v1(178.06,95.39) 178.16,95.49 C105.1 v1(180.6,95.49) ; v1(178.97,81.87) 179.04,81.95 179.09,81.95 179.22,82.08 179.46,82.08 179.81,82.43 C107.1 179.81,82.86 180.6,83.65 v1(180.6,84.41) ; C117.1 v1(195.87,81.92) ; C111.1 200.82,93.74 v1(201.08,93.99) ; v1(199.13,104.94) 199.13,104.97 199.65,105.5 C110.1 199.65,106.41 198.11,107.96 LB5.2 ; v1(201,89.05) 200.71,88.76 C112.1 ; v1(199.43,93.05) 198.54,93.05 LB14.1 ; v1(178.06,90.64) 178.19,90.76 C106.1 v1(180.63,90.76) ; C113.1 v1(201.08,84.87) ; C109.1 187.59,104.85 v1(187.7,104.96) ; C108.1 v1(183.02,104.91)
  BOTTOM w0.508: v1(198.41,102.63) 198.41,103.7 C71.1 ; v1(199.13,104.94) 199.08,104.88 199.07,104.88 198.31,104.13 C71.1 ; C71.1 196.92,102.4 LB8.2
  vias: v1(176.19,108.59) v1(176.44,107.83) v1(176.95,108.59) v1(177.46,107.71) v1(177.96,106.94) v1(180.76,104.02) v1(180.76,103.26) v1(180.75,102.37) v1(181.77,103.26) v1(181.77,102.37)
1V2_PLL: length 5.6
  TOP w0.203: v1(192.54,82.31) 192.79,82.05 192.95,82.05 193.42,81.58 U15.37
  BOTTOM w0.381: v1(192.54,82.31) 192.54,81.61 C116.1 192.42,81.5 LB16.2 192.44,80.4 192.82,80.02 C11.1
1V2_STANDBY: length 58.7
  TOP w0.203: v1(191.47,79.23) 191.42,79.29 U15.32
  TOP w0.381: 154.34,76.62 C77.1 154.34,77.35 ; 154.34,76.62 155.36,76.62 R40.1 155.36,77.35 ; 154.34,76.62 153.68,76.62 153.45,76.84 ; 155.23,77.86 155.23,78.24 152.56,80.91 149.03,80.91 R55.2
  TOP w0.508: 155.74,77.61 157.64,77.61 161.86,73.39 173.04,73.39 174.03,72.4 182.97,72.4 v1(185.51,74.94)
  BOTTOM w0.381: LB16.1 191.47,79.87 v1(191.47,79.23) 191.45,79.21 C103.1 190.63,79.18 190.63,78 C10.1
  BOTTOM w0.508: v1(185.51,74.94) 188.76,74.94 190.57,76.75 C10.1
1V5_DDR3: length 63.9
  TOP w0.178: v1(164.78,89.49) 164.78,90.83 164.78,90.83 165.18,91.23 U7.H2 ; U7.D2 168.38,91.27 167.98,90.87 v1(167.98,90.29) ; v1(163.41,89.51) 163.18,89.74 163.18,90.85 163.58,91.26 U7.K2
  TOP w0.203: v1(180.62,81.85) 180.62,81.85 U15.5 ; U15.194 177.83,91.63 v1(178.06,91.4) ; v1(178.05,87.08) 178.03,87.08 177.79,86.83 U15.206 ; v1(183.02,81.87) 183.02,80.72 U15.11 ; U15.180 176.91,97.23 178.08,97.23 v1(178.09,97.24) ; U15.212 177.79,84.43 v1(178.06,84.16) 178.06,84.18 ; v1(178.06,94.18) 177.81,94.43 U15.187 ; U15.175 176.91,99.23 177.95,99.23 v1(178.11,99.07) ; U15.215 177.81,83.23 v1(178.06,83.48) ; U15.190 177.81,93.23 v1(178.06,93.48) ; v1(178.06,87.77) 177.8,88.03 U15.203 ; U15.169 v1(178.17,101.63)
  TOP w0.305: U7.N1 v1(161.18,92.9) ; U7.A1 v1(170.78,92.9) ; U7.R1 v1(159.58,92.9) ; U7.N9 v1(161.18,85.22) ; U7.B2 v1(170.39,91.05) ; U7.R9 v1(159.58,85.22) ; U7.H9 v1(165.18,85.22) ; U7.K8 163.55,86.66 v1(163.18,86.29) ; U7.E9 v1(167.58,85.16) ; U7.C1 v1(169.18,92.9) ; U7.C9 v1(169.18,85.16) ; U7.A8 v1(171.42,86.66) ; U7.F1 v1(166.78,92.9) ; U7.D9 v1(168.38,85.16)
  TOP w0.356: U7.G7 165.98,88.34 v1(165.72,88.6)
  TOP w0.508: 150.28,90.43 150.28,91.2 149.51,91.96 R7.2
  TOP w0.635: 150.91,84.07 C16.1 ; C16.1 153.45,84.07 ; C16.1 152.18,85.06
  BOTTOM w0.381: v1(178.05,87.08) 178.42,87.08 C96.1 ; v1(180.62,81.85) 180.62,81.78 180.6,81.77 C100.1 ; C91.1 177.98,101.69 178.04,101.63 v1(178.17,101.63) ; C99.1 178.42,84.16 v1(178.06,84.16) ; C94.1 177.65,93.48 v1(178.06,93.48) ; v1(161.18,85.22) 161.27,85.13 C140.1 ; C140.1 162.19,84.44 163.23,85.48 ; C140.1 C141.1 159.57,85.21 v1(159.58,85.22) ; C90.1 162.44,86.17 163.05,86.17 v1(163.18,86.29) ; C98.1 177.62,83.48 v1(178.06,83.48) ; C101.1 183.01,81.87 v1(183.02,81.87) ; v2(157.39,88.53) 157.39,88.33 C136.1 R224.2 ; v1(178.09,97.24) C131.1 ; C97.1 177.63,87.77 v1(178.06,87.77) ; v1(174.66,106.77) C259.1 v1(172.38,106.77) ; C130.1 165.54,89.29 ; v1(178.11,99.07) 177.65,99.07 C92.1 ; C93.1 177.39,91.02 177.77,91.4 v1(178.06,91.4) ; C95.1 178.43,94.18 v1(178.06,94.18)
  vias: v1(143.94,89.29) v1(143.94,87.39) v1(143.94,85.48) v1(145.84,89.29) v1(145.84,87.39) v1(145.84,85.48) v1(147.75,89.29) v1(147.75,87.39) v1(147.75,85.48) v1(164.35,88.6) v1(165.03,88.6)
1V8_ETH0: length 4.4
  TOP w0.254: U3.2 110.12,116.83 110.39,117.11 110.9,117.11
  TOP w0.381: C2.1 112.02,118.92 C21.1 111,117.11 110.9,117.11
1V8_ETH1: length 3.3
  TOP w0.254: v1(129.82,118.76) 129.82,118.73 129.8,118.76 129.45,118.76 129.04,118.34 U4.2
  TOP w0.381: v1(129.82,118.76) 129.82,119.32 C15.1
  BOTTOM w0.381: v1(129.82,118.76) 129.41,118.35 C24.1
3V3: length 100.3
  TOP w0.185: v1(188.46,81.95) 188.17,81.95 187.82,81.6 U15.23
  TOP w0.203: U15.34 192.22,81.76 v1(191.67,82.31)
  TOP w0.381: v1(188.46,81.95) 188.82,82.31 v1(191.67,82.31) ; R118.2 v1(187.54,77.1) 187.56,77.07 187.56,75.27 183.3,71 v1(176.06,71) 173.39,71 172.25,72.15 160.84,72.15 160.56,71.87 R97.1 159.83,71.64 152.91,71.64 ; R142.2 R176.2 v1(176.06,68.72)
  TOP w0.508: Q1.2 138.67,79.05 138.67,73.34 139.23,72.78 152.44,72.78 152.91,72.3 J14.2 ; 140.37,84.21 140.94,83.64 C165.1 140.94,77.06 142.05,75.96 143.7,75.96
  TOP w0.635: 130.21,81.78 C37.1 ; C37.1 131.48,82.77 ; C37.1 132.75,81.78
  BOTTOM w0.381: C124.1 LB15.1 191.57,82.4 v1(191.67,82.31) ; v1(176.06,71) v1(176.06,68.72) ; v1(187.54,77.1) 187.54,80.51 C9.1 187.93,81.42 v1(188.46,81.95)
3V3_A_ETH0: length 22.2
  TOP w0.254: C158.1 109.62,118.01 U3.3
  TOP w0.381: C158.1 109.73,119.1 C19.1 109.44,119.93 LB3.2 109.76,121.32 109.76,123.86 v1(107.86,125.76)
  TOP w0.508: T2.2 v1(99.7,125.76) ; T2.7 v1(106.05,125.76)
  BOTTOM w0.381: v1(99.7,125.76) C159.1 v1(106.05,125.76) C155.1 v1(107.86,125.76)
3V3_A_ETH1: length 25.5
  TOP w0.254: U4.3 128.54,118.63 v1(128.8,118.9)
  TOP w0.381: v1(129.93,126.65) 131.46,125.13 131.46,121.19 v1(131.99,120.66)
  TOP w0.508: v1(121.54,126.91) T1.2 ; v1(127.89,126.91) T1.7
  BOTTOM w0.381: C164.1 128.2,118.29 v1(128.8,118.9) 129.49,119.58 C22.1 130.77,119.58 131.08,119.27 131.62,119.27 ; v1(121.54,126.91) 121.54,126.89 121.78,126.65 C166.1 127.64,126.65 v1(127.89,126.91) 128.69,126.91 C167.1 v1(129.93,126.65) ; v1(131.99,120.66) 131.62,120.29 131.62,119.27 ; 131.62,119.27 LB6.2
3V3_FP_NB: length 111.2
  TOP w0.381: J28.2 J15.2 135.13,45.82 136.69,47.38 159.68,47.38 174.34,32.71 174.34,19.12 173.39,18.17 R44.1 172.27,18.65 171.99,18.93 167.22,18.93 D18.1 163.05,23.1 R70.2 160.44,19.82 161.07,19.19 161.07,14.61 153.96,7.5 149.13,7.5 146.44,10.19 R108.2
  TOP w0.508: R71.2 R108.2
3V3_JTAG_FP: length 101.2
  TOP w0.381: R111.2 v1(78.01,83.96) ; C163.1 79.36,74.86 78.01,76.21 v1(78.01,80.53) R114.2 ; C163.1 80.17,73.8 79.28,72.91 61.19,72.91 S1.2 S1.1 52.61,70.75 C224.1 J27.10 J27.20 47.91,92.97 55.85,100.91 C221.1 60.3,100.91 62.77,103.39 65.31,103.39 J16.9 ; C163.1 J30.24 J30.23 ; R110.2 v1(78.01,82.81)
  BOTTOM w0.381: v1(78.01,80.53) v1(78.01,82.81) v1(78.01,83.96)
3V3_MOS: length 652
  TOP w0.203: v1(181.24,104.83) 181.44,104.83 181.82,105.21 U15.155 ; v1(200.93,91.3) 201.26,91.63 U15.77 ; v1(201.03,86.04) 201.2,86.04 201.21,86.03 U15.63 ; U15.147 185.02,105.21 v1(185.33,104.9) ; U15.47 197.42,82 197.64,82.23 v1(197.64,82.2) ; U15.115 197.82,105.22 198.69,104.35 198.94,104.35 ; 215.68,83.6 U21.12
  TOP w0.254: v1(201.04,104.15) 200.84,104.35 198.94,104.35 ; U21.37 237.17,83.6 237.81,84.24 C148.1 ; C162.1 125.74,112.76 126.04,113.06 U4.17 ; R143.2 v1(182.95,108.47) ; C152.1 107.12,110.63 U3.17
  TOP w0.381: R141.2 177.99,108.95 v1(178.34,108.59) ; C152.1 v1(108.28,110.15) ; C13.1 213.17,83.3 C147.1 214.82,83.6 215.68,83.6 ; R128.2 247.81,67.7 ; v1(233.03,96.86) R61.1 ; C162.1 124.94,111.76 v1(124.83,111.65) ; v1(120.43,119.39) 124.62,119.39 v1(125,119.01) ; 135.04,117.36 134.65,117.74 v1(134.65,119.26) 138.14,122.75 v1(138.14,128.28) ; v1(209.2,82.31) 212.42,79.08 R208.1 ; C148.1 v1(238.29,84.97) ; v1(201.04,104.15) 201.04,104.5 201.84,105.29 v1(202.96,105.29) R123.1 ; 236.36,74.69 R237.1 ; R56.1 247.08,90.2 246.24,89.37 v1(245.27,89.37) R57.1 242.66,89.37 238.8,93.23 v1(233.03,93.23) ; 263.56,79.08 259.83,79.08 259.5,78.75 Q11.1 259.5,77.32 R231.1 ; R62.1 v1(233.03,99.5) ; U16.8 C149.1 221.86,72.76 C14.1 223.37,72.72 225.33,74.69 v1(227.11,74.69) ; v1(123.2,114.44) R212.2
  TOP w0.508: v1(186.85,107.83) 187.39,108.37 R179.2 188,110.47 188,112.15 182.76,117.38 135.06,117.38 135.04,117.36 135.04,117.23 133.72,115.91 v1(133.55,115.91) 133.35,115.71 R210.2 ; v1(183.81,132.6) 179.23,132.6 178.22,131.58 D17.2 ; v1(114.71,120.79) LB3.1 ; R211.2 v1(114.48,114.06) 116.23,115.81 v1(116.23,120.79) ; v1(206.67,105.29) C171.1 R124.2 205.93,107.1 206.23,107.4 206.23,113.85 205.52,114.56 202.86,114.56 202.41,115.01 202.41,120.09 v1(189.9,132.6) ; v1(227.11,74.69) 238.16,74.69 240.19,76.72 v1(240.19,84.97) v1(245.27,84.97) ; v1(210.6,83.7) 210.82,83.49 C13.1
  TOP w0.762: v1(227.14,69.55) 227.87,70.29 v1(227.87,70.32) 242.66,70.32 245.27,67.7 255,67.7 263.56,76.26 263.56,91.88 LB27.1 264.83,93.15 264.83,101.86 261.65,105.04 L4.1
  TOP w1.016: v1(131.85,70.88) 131.85,69.74 ; 131.85,69.74 132.75,68.84 146.09,68.84 150.12,64.8 193.66,64.8 194.52,65.67 206.16,65.67 206.97,64.86 222.44,64.86 v1(227.14,69.55) ; 131.85,69.74 v1(131.85,69.72) ; v1(131.85,74.69) v1(131.85,75.83) 131.85,77.47 133.51,79.13 Q1.3 ; v1(207.94,77.35) v1(206.67,77.35) 202.35,81.67 v1(201.2,81.67) v1(200.57,82.31)
  BOTTOM w0.254: R177.2 180.5,106.66 R180.2
  BOTTOM w0.381: v1(124.83,111.65) 125.45,112.27 C23.1 125.77,112.85 125.77,115.45 ; v1(133.55,115.91) 133.22,115.58 131.1,115.58 130.34,116.34 126.02,116.34 ; v1(201.04,104.15) 201.46,104.56 R182.2 ; LB13.1 189.5,101.5 v1(189.39,101.61) ; v1(238.29,84.97) v1(240.19,84.97) ; 125.77,115.45 125.77,116.09 126.02,116.34 ; 125.77,115.45 125,115.45 123.99,114.44 v1(123.2,114.44) ; v1(182.95,108.47) 185.1,108.47 R178.2 185.86,108.82 v1(186.85,107.83) ; v1(138.14,128.28) 138.59,128.73 138.59,136.79 136.65,138.73 J24.12 ; C20.1 107.46,110.15 v1(108.28,110.15) ; LB6.1 v1(134.65,119.26) ; C118.1 v1(197.64,82.2) ; v1(233.03,99.5) v1(233.03,96.86) v1(233.03,93.23) ; 126.02,116.34 125.51,116.85 125.51,118.5 v1(125,119.01) ; R180.2 R117.2 179.23,107.55 178.34,108.44 v1(178.34,108.59) 177.48,109.46 R203.2 ; v1(201.03,86.04) 200.91,86.17 C123.1 198.53,86.17 v1(198.51,86.19) ; v1(198.55,91.23) 198.62,91.3 C122.1 v1(200.93,91.3) ; v1(245.27,89.37) v1(245.27,84.97) ; v1(182.66,101.86) 182.66,103.41 v1(181.24,104.83) C121.1 180.6,106.18 R177.2 ; v1(185.4,101.97) C119.1 185.4,104.83 v1(185.33,104.9) 185.46,105.03 R181.2
  BOTTOM w0.508: v1(114.48,114.06) 111.42,114.06 110.73,113.37 107.17,113.37 106.88,113.08 106.88,110.72 C20.1 ; v1(183.81,132.6) v1(189.9,132.6) ; v1(114.71,120.79) v1(116.23,120.79) 117.51,120.79 ; 117.51,138.73 117.51,125.23 ; 117.51,138.73 J23.12 ; 117.51,138.73 119.12,140.34 123.61,140.34 J24.10 ; 117.51,125.23 116.24,126.5 97.95,126.5 96.56,127.9 96.56,135.21 J23.10 ; 117.51,125.23 117.51,120.79 ; v1(193.84,99.7) 194.11,99.43 LB1.1 194,98.58 LB2.2 ; 117.51,120.79 118.91,119.39 v1(120.43,119.39) ; v1(206.67,105.29) v1(202.96,105.29) ; v1(201.04,104.15) 201.04,103.03 199.12,101.1 v1(198.41,101.1) ; v1(186.85,107.83) 186.85,107.2 186.07,106.41 R181.2
  BOTTOM w0.762: v1(207.94,77.35) 207.94,81.05 v1(209.2,82.31) 210.59,83.7 v1(210.6,83.7) ; v1(200.57,82.31) v1(201.2,81.67)
  BOTTOM w1.016: v1(131.85,75.83) v1(131.85,74.69) v1(131.85,70.88) v1(131.85,69.72) ; v1(206.67,77.35) v1(207.94,77.35) 214.29,77.35 215.68,75.96 219.62,75.96 220.89,74.69 v1(227.11,74.69) 227.87,73.92 v1(227.87,70.32) 227.87,70.29 v1(227.14,69.55)
  vias: v1(197.65,84.72) v1(198.53,84.72)
3V3_PLL: length 4.8
  TOP w0.203: v1(194.28,81.87) 194.22,81.81 194.22,80.72 U15.39
  BOTTOM w0.381: C115.1 v1(194.28,81.87) C12.1 LB15.2
3V3_PWR: length 16.2
  TOP w0.381: 19.34,74.56 C195.2 20.2,73.69 ; 20.48,73.67 21.88,73.67 22.31,74.1 R1.2 ; 16.55,75.19 11.59,75.19 10.03,76.75 R39.1
  TOP w0.635: 15.85,80.53 C270.1 ; C270.1 16.93,81.8 ; C270.1 16.93,79.26
3V3_T: length 103.4
  TOP w0.254: 252.16,141.23 251.98,141.23 251.59,140.85 U22.2 ; U22.11 248.26,137.61 247.94,137.3 247.94,136.41
  TOP w0.381: R41.2 242.89,124.75 ; 242.89,124.75 v1(242.86,124.72) ; 242.89,124.75 243.52,124.75 246.09,127.31 246.09,132.52 247.18,133.61 247.18,134.83 247.94,135.59 247.94,136.41 ; 252.16,141.23 252.26,141.23 252.72,141.69 v1(252.72,142.5) ; R43.2 240.29,124.85 v1(240.17,124.72) 239.94,124.72 239.43,125.23 239.43,127.9 239.05,128.28 239.05,142.53 241.23,144.71 247.05,144.71 249.13,142.63 v1(249.13,142.6) ; R64.2 257.72,138.95 258.61,138.06 258.61,134.96 256.27,132.62 R84.2 255.56,129.3 251.12,124.85 v1(251.12,124.47)
  TOP w0.508: LB4.2 257.08,113.29 C231.1 255.81,118.27 C40.1 C183.1 255.08,122.79 254.16,123.71 v1(251.12,123.71) v1(251.12,124.47)
  BOTTOM w0.305: v1(249.13,142.6) 249.18,142.55 252.66,142.55 v1(252.72,142.5)
  BOTTOM w0.381: v1(251.12,124.47) 250.86,124.72 v1(242.86,124.72) v1(240.17,124.72)
3V3_TS: length 3.1
  TOP w0.635: 261.23,97.03 J34.24
  TOP w0.762: J34.23 J34.24
5V0: length 34.5
  TOP w0.381: Q3.2 129.37,75.83 R135.1
  TOP w0.508: Q3.2 127.93,74.69 127.93,73.03 129.07,71.89 145.45,71.89 J14.1
  TOP w0.635: 132.62,90.93 C35.1 ; C35.1 133.89,91.92 ; C35.1 135.16,90.93
  vias: v1(128.43,80.27) v1(128.43,79.51) v1(128.56,84.85) v1(128.56,83.96) v1(129.32,80.27) v1(129.32,79.51) v1(129.45,84.85) v1(129.45,83.96)
5V0_MOS: length 462.8
  TOP w0.254: 168.94,139.84 168.59,140.18 J25.18
  TOP w0.381: U23.14 249.85,73.92 C192.2 250.58,71.54 v1(251.37,70.75) ; 191.7,135.38 190.79,135.38 190.68,135.26 C177.1 ; v1(167.92,137.53) 167.92,135.78 168.2,135.5 R72.2 R79.2 ; R216.1 205.23,118.14 C215.1 205.33,118.56 191.7,132.19 R151.1 ; v1(170.11,137.53) C26.1 U14.5
  TOP w0.508: R151.1 191.7,135.38 LB12.2 ; v1(174.18,136.58) 175.67,138.06 ; LB20.1 v1(262.29,82.81) ; 168.94,139.84 168.94,138.7 v1(170.11,137.53)
  TOP w0.762: v1(263.69,93.74) v1(263.69,94.75) 263.69,100.72 262.42,101.99 240.07,101.99 237.36,104.7 LB7.2 232.54,104.7 LB26.2 ; Q3.3 126.78,72.65 131.86,67.57 145.71,67.57 149.57,63.71 194.68,63.71 195.49,64.53 205.4,64.53 206.16,63.76 223.05,63.76 228.38,69.1 242.23,69.1 244.64,66.68 v1(251.62,66.68) 255.43,66.68 264.55,75.8 v1(264.55,82.81) v1(264.55,89.42) v1(264.55,90.41) ; LB17.1 175.67,138.06 v1(175.67,145.43) 176.69,145.43 176.7,145.42 190.79,145.42 191.72,144.5 LB12.2
  TOP w1.016: v1(174.52,145.43) v1(175.67,145.43) ; Q3.3 119.92,74.81 118.4,76.34 v1(118.4,102.88) v1(118.4,104.02) ; D20.2 149.77,129.04 142.84,122.11 141.51,122.11 ; v1(118.53,125.61) v1(118.53,124.6) 117.71,123.78 117.71,111.87 v1(118.4,111.18) v1(118.4,109.91)
  BOTTOM w0.381: v1(251.62,66.68) 251.62,70.49 v1(251.37,70.75)
  BOTTOM w0.508: v1(262.29,82.81) v1(264.55,82.81) ; v1(167.92,137.53) v1(170.11,137.53) 171.06,136.58 v1(174.18,136.58)
  BOTTOM w0.762: v1(264.55,89.42) v1(264.55,90.41) 264.55,92.87 v1(263.69,93.74) v1(263.69,94.75)
  BOTTOM w1.016: v1(175.67,145.43) v1(174.52,145.43) 174.27,145.68 144.93,145.68 139.61,140.36 139.61,127.15 139.22,126.76 ; v1(139.22,121.68) 139.22,122.31 139.22,122.31 v1(139.22,122.82) 139.22,126.76 ; v1(118.4,102.88) v1(118.4,104.02) v1(118.4,109.91) v1(118.4,111.18) ; v1(118.53,124.6) v1(118.53,125.61) 118.53,126.88 119.55,127.9 137.19,127.9 138.34,126.76 139.22,126.76
5V0_PWR: length 18
  TOP w0.381: C202.2 18.2,97.04 ; R10.2 22.73,96.07 22.22,95.56 18.4,95.56 18.07,95.89 ; R38.1 11.68,92.88 12.74,91.83 14.01,91.83 14.77,92.59 14.77,94.75 v1(15.53,95.51)
  TOP w0.635: C269.1 17.52,104.2 ; C269.1 17.52,101.66 ; C269.1 16.44,102.93
  vias: v1(15.53,97.29) v1(15.53,96.4) v1(16.55,97.29) v1(16.55,96.4) v1(16.55,95.51) v1(17.56,97.29) v1(17.56,96.4) v1(17.56,95.51)
5V0_TS: length 2.2
  TOP w0.635: 238.15,100.11 J34.1 239.23,101.19
5V0_VBUS0: length 4.7
  TOP w0.635: C266.1 142.53,131.9 ; C266.1 143.8,130.82 ; C266.1 141.26,130.82 ; C266.1 142.53,129.74
5V0_VBUS1: length 4.6
  TOP w0.635: 155.26,122.33 J19.1 154.12,123.48 ; 161.07,125.93 C267.1 159.8,124.85
5V_FP_NB: length 109.5
  TOP w0.381: R60.2 R66.2 R67.2 97.93,22.89 97.32,23.5 96.18,23.5 95.67,23 95.67,21.19 95.41,20.94 C151.2 ; C151.2 U8.7 94.78,15.88 96.3,14.36 101,14.36 104.05,11.31 104.05,7.5 102.8,6.26 C156.1 U8.21 ; C151.2 94.04,20.94 v1(94.02,20.96)
  TOP w0.508: J28.1 J15.1 133.13,45.09 131.1,47.13 104.94,47.13 92.11,34.3 C72.1
  BOTTOM w0.508: v1(94.02,20.96) 92.11,22.87 C72.1
5V_VIDEO: length 121.2
  TOP w0.381: 214.02,141.62 214.02,136.28 214.53,135.78 D1.2 ; 214.02,141.62 220.88,141.62 ; 214.02,141.62 207.67,141.62 ; 230.29,120.15 230.95,120.81 C179.1 234.09,122.71 234.09,137.68 235.88,139.46 235.88,144.92 235.24,145.55 232.7,145.55 231.94,144.79 231.94,142.88 230.93,141.87 228.88,141.87 228.63,141.62 228.12,141.62 ; 230.29,120.15 229.14,121.29 223.3,121.29 222.91,121.69 U12.5 ; 230.29,120.15 U17.4 ; 220.88,141.62 228.12,141.62 ; 220.88,141.62 221.01,141.49 221.01,136.41 221.64,135.78 D14.2 ; D3.2 207.67,137.21 207.67,141.62 ; 207.67,141.62 206.33,142.96 196.71,142.96 193.58,139.84 193.58,137.93 195.3,136.22 C178.1 LB12.1 ; 228.12,141.62 228.12,137.93 D2.2
12V0_PWR: length 61.6
  TOP w0.381: 31.51,121.14 C194.2 29.98,121.14 29.63,120.79 29.63,119.01 27.21,116.6 11.59,116.6 9.43,114.44 9.43,109.74 13.75,105.42 13.75,103.9 D12.1
  TOP w0.508: D12.1 13.24,103.64 12.1,104.78 10.32,104.78 9.94,104.4 9.94,93.35 12.74,90.56 D11.1
AVCC12_HDMI: length 10.7
  TOP w0.203: v1(196.48,104.86) 196.74,104.86 197.02,105.14 U15.117
  BOTTOM w0.381: C256.1 194.24,103.64 C227.1 193.74,102.96 C257.1 ; v1(196.48,104.86) C84.1 C83.1
  BOTTOM w0.508: C83.1 195.61,105.45 195.61,105.21 195.65,105.16 195.65,104.41 195.21,103.96 C256.1 196.64,103.64 LB8.1
AVDD12_QAM: length 6.6
  TOP w0.203: v1(201.18,95.39) 201.2,95.39 201.36,95.23 U15.86
  BOTTOM w0.381: LB14.2 197.04,93.44 C6.1 198.35,94.75 199.83,94.75 C86.1 200.9,95.11 v1(201.18,95.39)
AVDD33_ADAC: length 9.2
  TOP w0.203: U15.103 201.16,102.03 200.69,101.56 200.69,100.48 v1(200.82,100.34)
  BOTTOM w0.381: v1(200.82,100.34) 200.82,100.35 199.81,99.34 C87.1 198.75,99.09 C7.1 198.35,98.69 LB1.2
AVDD33_USB: length 14.1
  TOP w0.203: U15.134 190.22,106.14 190.22,105.25 190.35,105.11 190.35,105.03 190.37,105.01 v1(190.37,104.99) ; v1(191.73,104.78) 192.22,105.27 192.22,106.14 U15.129 ; U15.138 v1(188.62,105.01)
  TOP w0.381: v1(191.73,104.78) 191.3,104.35 190.71,104.35 190.37,104.7 v1(190.37,104.99) 189.78,104.4 189.22,104.4 v1(188.62,105.01)
  BOTTOM w0.381: C78.1 191.81,104.86 v1(191.73,104.78) 191.73,104.2 191.55,104.02 C5.1 190.32,102.94 LB13.2 ; v1(190.37,104.99) 190.31,104.93 C79.1 ; v1(188.62,105.01) 188.73,105.13 C76.1
AVDD33_VDAC: length 10.4
  TOP w0.203: v1(201.16,98.66) 201.16,98.9 201.49,99.23 202.33,99.23 U15.96
  BOTTOM w0.381: v1(201.16,98.66) 201.34,98.49 C89.1
  BOTTOM w0.508: C89.1 202.01,97.27 C278.1 199.18,97.17 198.82,96.81 C88.1 198.28,96.81 197.99,97.1 C8.1 195.9,97.1 LB2.1
AVDD_HDMI: length 5.8
  TOP w0.203: U15.125 193.82,105.19 v1(194.09,104.91)
  BOTTOM w0.381: v1(194.09,104.91) 193.99,105.01 C49.1 193.99,106.97 193.89,107.07 C186.1 LB5.1
GND: length 2547.4
  TOP w0.127: v1(251.88,137.42) 251.88,137.3
  TOP w0.178: U7.J8 164.38,86.89 163.98,87.29 163.98,87.63 163.64,87.97 163.46,87.97 v1(163.43,88) ; U7.J2 164.38,91.23 163.98,90.83 163.98,90.26 v1(163.98,90.26) ; 167.98,88.76 v1(168,88.78) ; 167.58,86.84 167.18,87.24 v2(167.18,88.02) ; v2(167.98,88.02) 167.98,87.29 168.38,86.9 U7.D8
  TOP w0.185: v2(167.18,88.02) 166.99,88.21 v1(166.99,88.78) ; U7.E8 167.58,86.84
  TOP w0.203: v1(175.75,85.53) 175.85,85.63 U15.209 v1(178.07,85.63) ; v1(204.25,99.05) 203.67,99.63 U15.97 201.13,99.63 v1(200.95,99.45) ; v1(178.06,96.06) 178.03,96.03 U15.183 175.81,96.03 v1(175.68,95.89) ; v1(200.95,98.03) U15.93 ; v1(189.48,105.01) 189.53,105.06 189.6,105.06 189.82,105.28 189.82,106.14 ; 192.05,79.39 191.82,79.62 U15.33 ; v1(193.58,82.43) 193.58,81.93 193.82,81.7 U15.38 193.82,79.39 193.82,79.39 v1(193.68,79.26) ; U15.2 179.42,79.76 179.32,79.66 178.6,79.66 v1(178.29,79.97) ; v1(201.18,96.15) 201.46,96.43 U15.89 204.99,96.43 v1(205.01,96.46) ; v1(215.43,82.94) 215.59,83.1 U21.13 ; v1(191.04,104.94) 191.02,104.96 U15.132 ; v1(204.63,101.23) 204.51,101.36 203.36,101.36 203.24,101.23 U15.101 ; 189.82,106.14 189.82,107.22 v1(190.13,107.53) ; 189.82,106.14 U15.135 ; U15.122 v1(195.02,104.94) ; v2(167.3,90.18) 167.65,89.82 168.61,89.82 v1(168.92,90.13) ; v1(178.05,89.23) U15.200 175.4,89.23 v1(175.39,89.24) ; v1(193.07,104.91) 192.93,104.91 192.62,105.22 U15.128
  TOP w0.254: U22.16 251.09,135.67 251.37,135.39 ; J25.8 163.59,142.01 v1(163.59,140.28) ; 129.2,117.23 129.54,117.57 U4.1 129.85,118.01 v1(130.59,118.75) ; J25.5 162.09,142.01 v1(162.09,140.28) ; v1(168.07,140.22) 168.09,140.25 J25.17 ; v1(237.53,82.81) 237.23,83.1 U21.36 235.08,83.1 ; v1(165.09,140.28) 165.09,142.01 J25.11 ; U21.13 218.06,83.1 ; J25.2 v1(160.59,140.28)
  TOP w0.305: v2(166.63,83.91) 165.98,84.55 v1(165.98,85.22) U7.G9 U7.G8 ; U7.F9 v1(166.78,85.22) ; v1(167.9,93.88) 167.58,93.57 v1(167.58,92.9) U7.E1 U7.E2 ; U7.B3 v1(169.59,91.05) ; U7.B1 v1(169.98,92.9) ; C134.1 256.14,138.26 257.39,138.26 257.85,137.8 v1(257.85,137.55) ; U7.B9 169.98,85.15 169.99,85.15 v1(169.99,85.1) ; v1(254.67,139.96) 256.45,139.96 ; U7.M1 v1(161.98,92.9) 161.98,93.43 161.88,93.53 v2(161.88,93.81) ; v2(160.26,83.78) 160.26,84.41 160.38,84.54 v1(160.38,85.22) U7.P9 ; U7.P1 v1(160.38,92.9) 160.38,93.25 160.61,93.48 v2(160.61,93.78) ; U7.G1 v1(165.98,92.9) 165.98,94.05 166.35,94.42 ; U7.T1 v1(158.78,92.9) v1(158.78,93.68) ; v1(161.98,85.22) U7.M9 ; v1(174.66,86.27) 174.94,86.27 175.47,86.8 v1(175.68,86.8) ; U7.D1 v1(168.38,92.9) ; U7.A9 171.38,85.86 v1(171.41,85.83)
  TOP w0.343: v1(172.12,89.95) 172.06,89.89 169.15,89.89 v1(168.92,90.13)
  TOP w0.356: U9.14 v1(210.1,124.6) ; C75.2 208.6,128.25 208.94,127.91 U9.10 v1(211.35,127.91) ; U9.4 v1(217.33,127.26)
  TOP w0.381: 247.08,143.72 246.64,144.15 241.44,144.15 239.69,142.4 239.69,128.41 240.29,127.8 v1(240.29,127.39) C33.2 ; 253.43,141.56 253.32,141.46 253.32,140.64 253.02,140.34 v1(252.77,140.34) ; C158.2 111.16,118.12 v1(111.29,118.25) ; 119.67,120.41 119.69,120.42 C154.1 v1(120.43,121.17) ; R247.2 v1(138.21,91.96) ; v1(252.64,127.9) v1(252.64,129.17) v1(252.64,130.69) C50.2 ; v1(96.51,22.87) R68.1 96.51,21.55 ; v1(127.16,120.15) 127.16,120.66 v1(126.27,121.55) v1(124.37,121.55) v1(122.97,121.55) ; R228.2 v1(137.2,106.41) ; v1(114.71,118.88) 114.2,119.39 C2.2 ; R129.1 C307.2 v1(250.61,68.69) ; 88.81,99.96 93.38,99.96 93.51,99.83 ; C151.1 v1(94.78,22.49) ; C174.2 v1(171.49,68.08) ; C306.2 v1(261.43,82.53) ; v1(164.37,136.54) U2.3 U2.8 v1(164.37,139.46) ; v1(106.46,105.29) v1(108.37,105.29) v1(110.27,105.29) v1(112.18,105.29) v1(114.08,105.29) v1(115.61,105.29) ; C59.2 179.03,110.91 v1(178.93,111.01) ; C224.2 v1(46.52,76.34) ; v1(237.53,82.81) 237.68,82.81 C148.2 ; U17.5 v1(230.29,125.36) ; Q6.2 v1(141.01,76.08) ; v1(201.17,107.27) 200.95,107.05 200.95,105.42 200.47,104.94 v1(200.14,104.94) ; v1(163.23,83.7) 163.23,83.02 163.69,82.56 v1(163.74,82.56) ; C316.2 v1(254.58,92.05) ; C191.2 v1(260.26,83.96) ; v1(178.47,68.97) v1(179.61,68.97) v1(181.01,68.97) v1(182.54,68.97) ; v1(247.94,90.94) 248.32,90.56 C80.2 ; C160.1 97.98,119.16 v1(97.95,119.14) ; C201.2 v1(154.19,69.63) ; v1(207.05,78.88) v1(206.03,79.89) v1(204.89,81.04) v1(203.74,82.18) ; v1(171.49,66.05) C172.2 ; C26.2 v1(170.84,139.08) ; v1(184.46,136.15) v1(184.46,137.3) ; C77.2 v1(154.34,75.14) C170.2 v1(151.47,75.14) ; C182.2 v1(245.4,103.39) ; v1(245.93,90.94) C150.2 ; C58.2 v1(139.98,107.96) ; C300.2 103.54,115.07 v1(103.29,114.82) 103.44,114.66 R25.2 ; R8.2 v1(242.35,112.41) ; C161.2 108.24,119.01 v1(108.88,118.37) ; v1(119.8,104.02) v1(121.12,104.02) v1(121.83,104.73) v1(123.43,104.73) v1(125.39,104.73) v1(127.42,104.73) v1(128.94,104.73) v1(130.97,104.73) v1(132.75,104.73) ; v1(100.87,120.02) v1(102.91,120.02) v1(105.19,120.02) ; v1(240.32,85.73) v1(239.05,87) v1(237.91,88.15) ; v1(162.85,136.28) v1(162.85,139.46) ; C193.2 v1(260.26,82.94) ; v1(248.96,140.85) v1(247.81,140.85) 246.54,140.85 v1(246.52,140.88) ; C320.2 v1(246.2,92.05) ; C173.2 v1(171.49,67.07) ; v1(259.12,76.21) 259.12,75.7 v1(258.61,75.19) v1(257.34,73.92) v1(255.94,72.53) ; v1(161.32,136.67) U5.3 U5.8 v1(161.32,139.46) ; C331.2 v1(235.7,96.86) ; v1(195.02,104.94) 194.41,104.33 193.65,104.33 v1(193.07,104.91) ; R102.2 215.16,79.08 v1(215.29,78.96) ; v1(257.67,91.27) C329.2 v1(257.67,93.4) ; R40.2 v1(155.36,75.14) ; v1(131.1,120.53) 131.55,120.08 C15.2 ; D7.2 v1(141.68,139.44) 141.61,139.44 v1(140.87,138.7) 140.75,138.58 140.75,135.07 v1(140.87,134.95) 141.53,134.29 C81.2 142.02,133.62 v1(142.66,132.98) 143.67,131.97 v1(146.2,131.97) ; R80.1 v1(79.39,85.86) ; R236.2 v1(244.64,71.26) ; C66.2 v1(133.87,102.5) ; C326.2 262.48,95.07 v1(262.8,95.39) ; C149.2 v1(220.64,71.13) ; U23.2 v1(248.57,80.9) ; v1(215.43,82.94) 214.97,82.48 C147.2 ; C318.2 v1(249,92.05) ; C165.2 v1(139.55,78.94) ; U8.22 v1(94.78,10.42) ; C319.2 v1(253.19,92.05) ; C325.2 v1(257.31,95.36) ; C21.2 v1(113.69,118.12) ; v1(125.77,119.77) 125.23,120.3 v1(123.61,120.3) v1(122.21,120.3) 120.66,120.3 v1(120.56,120.41) ; C34.2 v1(243.75,126.63) ; v1(171.49,69.1) C175.2 ; v1(182.95,111.64) C69.2 ; R46.1 v1(78.65,81.67) ; C314.2 v1(247.6,92.05) ; D2.1 v1(232.31,134.63) ; U8.25 v1(98.59,10.42) ; U8.28 v1(102.4,10.55) ; C152.2 v1(108.34,109.33) ; v2(165.01,84.46) 165.01,84.26 165.75,83.52 165.77,83.52 v1(165.77,83.45) ; v1(161.97,83.65) 161.98,83.66 v1(161.98,85.22) ; R99.2 178.4,110.19 178.73,109.86 v1(178.85,109.86) ; C192.1 v1(250.58,70.72) ; R98.2 v1(180.15,67.57) v1(181.01,67.57) v1(182.15,67.57) ; C196.2 v1(157.74,69.73) ; v1(200.95,80.53) v1(202.09,80.53) v1(203.24,79.38) v1(204.32,78.3) v1(205.27,77.35) ; R130.1 v1(260.26,84.97) ; C178.2 v1(196.7,136.34) ; 184.19,38.36 188.89,38.36 ; R197.2 v1(61.73,75.22) ; v1(217.33,127.26) 217.82,127.75 C27.1 ; v1(207.4,110.85) Q8.2 ; R26.2 122.24,117.46 v1(122.08,117.61) 122.29,117.81 C299.2 ; v1(206.74,99.27) R230.1 R168.1 204.47,99.27 v1(204.25,99.05) ; v1(169.44,83.58) 168.81,83.58 v1(168.15,84.24) ; v1(141.92,105.57) R81.1 143.04,106.31 ; R232.2 242.45,80.88 v1(242.35,80.78) 242.22,80.64 U23.7 242.22,77.22 v1(240.45,75.45) R235.2 ; v1(131.18,83.75) C17.2 v1(131.18,86.06) ; Q7.2 v1(204.76,112.28) ; R42.1 v1(143.67,82.69) ; v1(126.38,112.45) 126.55,112.28 C162.2 ; C213.2 v1(139.48,82.05) ; C168.2 129.45,121.17 v1(128.81,120.53) 128.81,119.9 v1(128.43,119.52) ; 72.68,107.83 72.68,112.15 ; C176.2 v1(161.3,69.73) ; 251.37,135.39 251.86,134.9 C135.2 251.86,133.53 C1.2 252.1,133.29 C47.2 C41.1 v1(254.16,132.47) ; 173.39,146.44 173.39,144.41 173.65,144.15 ; C4.2 v1(133.36,75.47) ; v1(243.24,93.48) 243.94,92.78 C315.2 v1(244.13,91.96) ; C14.2 v1(221.91,70.49) ; C19.2 v1(111.66,119.39) ; C332.2 v1(235.7,99.5) ; C221.2 v1(58.2,99.51) ; C74.2 135.67,97.55 ; C313.2 v1(250.39,92.05) ; C312.2 v1(255.98,92.05) ; C317.2 v1(251.79,92.05) ; 265.18,59.28 265.18,62.83 ; C308.2 v1(245.04,80.88) ; U14.2 v1(170.84,132.23) ; C171.2 v1(205.12,104.56) ; U16.4 v1(212.12,68.95) ; C177.2 v1(189.49,136.15)
  TOP w0.457: v1(163.74,82.56) v1(164.82,81.48) v1(166.08,80.22) v1(167.54,80.22) v1(168.45,80.22) v1(169.58,80.22) v1(170.74,80.22) v1(172.09,80.22) v1(173.39,80.22) v1(174.92,80.22) v1(176.25,80.22) v1(177.67,78.8) ; v1(206.74,99.27) 206.89,99.27 v1(207.99,100.36) v1(209.15,101.53) v1(210.81,103.18) v1(211.95,104.33) v1(213.15,105.53) v1(214.36,106.74) v1(215.25,107.63) v1(216.34,108.72) v1(217.97,108.72) v1(219.87,108.72) 220.51,108.72 v1(221.78,109.99) v1(222.92,111.13) v1(224.19,112.4) ; v1(178.93,111.01) v1(178.14,111.79) v1(176.06,111.79) v1(173.52,111.79) v1(170.98,111.79) v1(168.44,111.79) v1(165.9,111.79) v1(163.36,111.79) v1(160.82,111.79) v1(158.28,111.79) v1(155.74,111.79) v1(153.2,111.79) v1(150.66,111.79) v1(148.12,111.79) v1(145.58,111.79) v1(143.04,111.79) v1(140.5,111.79) v1(138.59,111.79) v1(137.5,110.7) v1(136.17,109.37) v1(134.9,108.1) 134,107.2 v1(133.89,107.2) v1(131.35,107.2) v1(128.81,107.2) v1(126.27,107.2) v1(123.73,107.2) v1(121.19,107.2) v1(117.38,107.2) v1(115.99,107.2) v1(113.45,107.2) v1(110.91,107.2) v1(108.37,107.2) v1(106.21,107.2) v1(105.32,108.09) v1(104.18,109.23) 103.44,109.97 v1(103.44,110.63) v1(103.44,112.91) R25.2 ; v1(184.57,135.14) v1(186.35,133.36) v1(187.87,131.84) v1(189.33,130.37) v1(190.92,128.79) v1(192.06,127.64) v1(193.52,126.18) v1(194.79,124.91) v1(196.31,123.39) v1(197.46,122.25) v1(198.98,120.72) v1(200.12,119.58) 200.72,118.98 v1(200.72,118.37) v1(200.72,117.1) v1(200.72,115.96) v1(200.72,114.82) v1(200.72,113.29) v1(200.72,111.64) v1(200.72,109.99) v1(200.72,108.49) ; v2(161.88,93.81) v1(161.88,94.95) v1(161.88,96.17) v1(162.69,96.99) v1(163.39,97.69) v1(164.22,98.51) v1(164.92,99.21) 165.4,99.69 v1(166,99.69) v1(167.14,99.69) v1(168.41,99.69) v1(169.68,99.69) v1(170.98,99.69) v1(172.38,99.69) ; v1(190.13,107.53) 190.25,107.65 v1(190.25,110.25) v1(190.25,112.15) v1(190.25,113.42) v1(190.25,114.59) v1(189.08,115.77) v1(187.93,116.91) v1(186.92,117.93) v1(185.84,119.01) v1(185.2,119.64) v1(183.87,120.98) v1(183.04,121.8) v1(181.52,121.8) v1(179.61,121.8) v1(177.71,121.8) v1(175.8,121.8) v1(173.9,121.8) v1(171.99,121.8) v1(169.96,121.8) v1(168.44,121.8) ; v1(243.24,93.48) v1(241.72,93.48) v1(240.45,94.75) v1(239.18,94.75) v1(237.78,94.75) v1(235.88,94.75) v1(233.97,94.75) v1(232.07,94.75) v1(230.16,94.75) v1(228.26,94.75) v1(226.35,94.75) v1(224.45,94.75) v1(222.54,94.75) v1(220.64,94.75) v1(218.73,94.75) v1(216.83,94.75) v1(214.92,94.75) v1(213.52,94.75) v1(212.13,93.35) v1(211.23,92.45) v1(209.68,92.45) v1(207.91,92.45) v1(206.25,92.45) v1(204.13,92.45) ; v1(243.24,94.62) v1(242.1,94.62) v1(240.96,95.77) v1(239.18,95.77) v1(237.78,95.77) v1(235.88,95.77) v1(233.97,95.77) v1(232.07,95.77) v1(230.16,95.77) v1(228.26,95.77) v1(226.35,95.77) v1(224.45,95.77) v1(222.54,95.77) v1(220.64,95.77) v1(218.73,95.77) v1(216.83,95.77) v1(214.92,95.77) v1(213.27,95.77) v1(212,94.5) v1(210.98,93.48) ; v1(167.9,93.88) 168.25,94.23 v1(169.01,94.23) v1(170.15,94.23) 171.18,94.23 171.42,93.99 v1(171.87,93.99) v1(173.01,93.99) v1(174.22,93.99) v1(175.27,93.99) ; v1(214.16,93.23) v1(216.83,93.23) v1(218.73,93.23) v1(220.64,93.23) v1(222.54,93.23) v1(224.45,93.23) v1(226.35,93.23) v1(228.26,93.23) v1(230.16,93.23) v1(232.07,93.23) ; v1(253.19,92.05) v1(253.19,90.85) v1(252.45,90.12) v1(251.43,89.1) v1(250.48,88.15) v1(249.59,87.26) v1(248.83,86.5) v1(247.56,86.5) v1(246.04,86.5) v1(244.64,86.5) v1(243.37,86.5) v1(241.59,86.5) v1(240.57,87.51) v1(239.43,88.66) v1(238.35,89.73) v1(237.4,90.69) v1(235.88,90.69) v1(233.97,90.69) v1(232.07,90.69) v1(230.16,90.69) v1(228.26,90.69) v1(226.35,90.69) v1(224.45,90.69) v1(222.54,90.69) v1(220.64,90.69) v1(218.73,90.69) v1(216.83,90.69) v1(214.92,90.69) 214.16,90.69 v1(213.4,89.93) 212.63,89.16 v1(210.73,89.16) v1(208.82,89.16) v1(206.92,89.16) v1(204.13,89.16) ; v1(106.46,116.34) v1(104.56,116.34) v1(103.03,116.34) v1(102.14,115.45) v1(102.14,114.18) v1(102.14,112.91) v1(102.14,110.5) 102.14,109.74 v1(102.84,109.04) v1(104.05,107.83) v1(105.6,106.28) v1(108.37,106.28) v1(110.91,106.28) v1(113.45,106.28) v1(115.99,106.28) v1(117.38,106.28) v1(121.19,106.28) v1(123.73,106.28) v1(126.27,106.28) v1(128.81,106.28) v1(131.35,106.28) v1(133.89,106.28) 134.4,106.28 v1(135.43,107.31) v1(136.64,108.52) v1(137.91,109.79) v1(139,110.88) v1(140.5,110.88) v1(143.04,110.88) v1(145.58,110.88) v1(148.12,110.88) v1(150.66,110.88) v1(153.2,110.88) v1(155.74,110.88) v1(158.28,110.88) v1(160.82,110.88) v1(163.36,110.88) v1(165.9,110.88) v1(168.44,110.88) v1(170.98,110.88) v1(173.52,110.88) v1(176.06,110.88) 177.71,110.88 177.99,110.6 R99.2 ; v1(236.84,115.78) v1(235.68,114.63) v1(234.61,113.55) v1(233.34,112.28) v1(232.32,111.26) v1(231.11,110.05) v1(230.03,108.97) v1(229.02,107.96) v1(227.81,106.75) v1(226.35,105.29) v1(225.14,104.09) v1(224.19,103.13) v1(222.54,103.13) v1(221.14,103.13) v1(219.62,103.13) 218.53,103.13 v1(217.87,102.47) v1(216.79,101.39) v1(215.52,100.12) v1(214.44,99.04) v1(213.04,97.65) v1(211.71,96.31) v1(210.5,95.11) v1(209.64,94.24) v1(207.94,94.24) ; v1(172.25,92.64) v1(173.65,92.64) v1(175.01,92.64) ; v1(169.44,83.58) v1(170.47,83.58) v1(171.53,83.58) v1(172.54,83.58) v1(173.66,83.58) v1(174.79,83.58) ; v1(122.08,117.61) 121.73,117.61 121.32,117.2 v1(121.32,116.34) v1(121.32,115.07) v1(121.32,113.55) v1(121.32,112.53) 121.32,111.26 v1(122.13,110.45) v1(123.48,110.45) v1(125.39,110.45) v1(127.29,110.45) v1(129.2,110.45) v1(131.1,110.45) v1(132.45,110.45) v1(133.51,111.52) v1(134.53,112.53) v1(135.55,113.55) v1(136.43,114.44) 137.04,115.05 v1(138.09,115.05) v1(139.99,115.05) v1(141.9,115.05) v1(143.8,115.05) v1(145.71,115.05) v1(147.61,115.05) v1(149.52,115.05) v1(151.42,115.05) v1(153.33,115.05) v1(155.23,115.05) v1(157.14,115.05) v1(159.04,115.05) v1(160.95,115.05) v1(162.85,115.05) v1(164.76,115.05) v1(166.66,115.05) v1(168.57,115.05) v1(170.47,115.05) v1(172.38,115.05) v1(174.28,115.05) v1(176.19,115.05) v1(178.09,115.05) v1(179.44,115.05) ; v1(200.95,77.86) v1(201.84,76.97) v1(202.79,76.02) v1(204.25,74.56) v1(206.41,74.56) v1(208.06,74.56) v1(209.84,74.56) v1(212.13,74.56) v1(213.21,73.48) v1(214.22,72.46) v1(215.17,71.51) v1(216,70.68) v1(216.7,69.99) ; v1(169.99,85.1) 170.16,84.92 v1(170.85,84.92) v1(172.25,84.92) v1(173.39,84.92) v1(174.65,84.92) 175.14,84.92 v1(175.75,85.53) ; 166.35,94.42 v1(167.27,95.34) 167.51,95.58 v1(168.15,95.58) v1(169.17,95.58) v1(170.34,95.58) v1(171.46,95.58) 172.61,95.58 172.85,95.34 v1(172.98,95.34) v1(174,95.34) v1(175.04,95.34) ; v1(195.56,110.37) v1(195.56,112.02) v1(195.56,113.42) v1(195.56,114.44) v1(195.56,115.58) 195.56,116.02 v1(194.85,116.72) v1(193.84,117.74) v1(192.63,118.94) v1(191.43,120.15) v1(190.22,121.36) v1(189.2,122.37) v1(188.19,123.39) v1(187.3,124.28) v1(186.35,125.23) v1(185.33,126.25) v1(183.42,126.25) v1(181.52,126.25) v1(179.61,126.25) v1(177.71,126.25) v1(175.8,126.25) v1(173.9,126.25) v1(171.99,126.25) v1(170.09,126.25) 169.33,126.25 v1(168.82,126.76) v1(167.87,127.71) v1(166.98,128.6) v1(166.03,129.55) v1(164.88,130.69) v1(163.87,131.71) v1(162.85,132.72) v1(162.85,133.99) v1(162.85,135.26) v1(162.85,136.28) ; v1(172.22,86.27) v1(173.26,86.27) v1(174.66,86.27) ; v1(184.6,78.75) v1(184.6,77.49) v1(183.81,76.7) v1(182.8,75.69) v1(181.9,74.79) 180.48,74.79 v1(180.14,74.44) v1(178.73,74.44) v1(177.2,74.44) v1(175.55,74.44) v1(174.75,74.44) v1(173.86,75.33) v1(172.38,75.33) v1(170.98,75.33) v1(169.71,75.33) v1(168.18,75.33) v1(166.66,75.33) v1(165.14,75.33) v1(164.02,75.33) v1(162.81,76.55) v1(161.66,77.69) v1(160.71,78.64) v1(159.76,79.6) v1(158.93,80.42) v1(158.17,81.18) v1(157.39,81.97) v1(157.39,83.14) v1(157.39,84.21) v1(157.39,85.86) ; v1(175.39,89.24) 174.63,89.24 v1(174.17,88.78) v1(173.01,88.78) v1(172.07,88.78) v1(171.05,88.78) v1(170.04,88.78) v1(169.02,88.78) v1(168,88.78) v1(166.99,88.78) 166.79,88.78 165.57,90 v2(165.57,90.23) ; v1(165.16,93.76) 165.16,94.5 v1(165.46,94.8) v1(166.76,96.1) 167.07,96.42 v1(167.9,96.42) v1(169.3,96.42) v1(170.34,96.42) v1(171.58,96.42) 172.99,96.42 v1(173.23,96.17) v1(174.25,96.17) 175.4,96.17 v1(175.68,95.89) ; v1(175.14,91.3) v1(173.74,91.3) v1(172.76,91.3) v1(171.73,91.3) ; v2(160.61,93.78) v1(160.61,94.83) v1(160.61,95.84) 160.61,96.73 v1(160.83,96.95) v1(161.72,97.84) v1(162.73,98.85) v1(163.49,99.62) v1(164.45,100.57) 164.79,100.91 v1(165.61,100.91) v1(166.63,100.91) v1(167.77,100.91) v1(168.92,100.91) v1(169.96,100.91) v1(171.08,100.91) v1(172.35,100.91) ; v1(217.64,111.49) v1(216.48,110.33) v1(215.28,109.13) v1(213.75,107.6) v1(212.99,106.84) v1(211.85,105.7) v1(210.58,104.43) v1(209.43,103.29) v1(207.38,101.23) v1(205.65,101.23) 204.63,101.23 v1(204.63,101.23) ; v1(157.29,90.69) v1(156.76,91.21) v1(156.76,92.34) v1(156.76,93.61) v1(156.76,95.01) v1(156.76,96.15) v1(156.76,97.29) v1(156.76,98.29) v1(158.04,99.56) v1(159.18,100.71) v1(160.32,101.85) v1(161.15,102.68) v1(162.23,103.76) v1(163.04,104.57) v1(164.25,104.57) v1(165.77,104.57) v1(167.3,104.57) v1(168.57,104.57) v1(169.84,104.57) v1(170.98,104.57) ; v1(175.55,88.05) 175.12,88.05 174.68,87.61 v1(174.33,87.61) v1(173.39,87.61) v1(172.35,87.61) ; v1(164.37,136.54) v1(164.37,135.26) v1(164.37,133.99) 164.37,133.49 v1(165.13,132.73) v1(166.14,131.71) v1(167.16,130.7) v1(168.17,129.68) v1(169.2,128.66) 170.08,127.77 v1(170.6,127.77) v1(172.12,127.77) v1(173.89,127.77) v1(175.8,127.77) v1(177.7,127.77) v1(179.61,127.77) v1(181.51,127.77) v1(183.42,127.77) v1(185.32,127.77) 185.96,127.77 v1(187.49,126.25) v1(188.38,125.36) v1(189.27,124.47) v1(190.41,123.33) v1(191.36,122.37) v1(192.57,121.17) v1(193.77,119.96) v1(194.98,118.75) v1(195.93,117.8) v1(197.14,116.6) v1(197.14,115.71) v1(197.14,114.56) v1(197.14,113.42) v1(197.14,112.02) v1(197.14,110.37) 197.14,109.31 v1(196.78,108.95) ; v1(156.12,85.73) v1(156.12,84.72) v1(156.12,83.58) v1(156.12,82.56) ; v1(214.65,112.01) 214.65,111.5 v1(213.65,110.5) v1(212.44,109.29) v1(210.92,107.77) v1(210.09,106.94) v1(208.95,105.8) v1(207.68,104.53) v1(206.54,103.39) v1(205.52,103.39) ; v1(161.97,83.65) v1(161.97,82.57) v1(162.8,81.75) v1(163.63,80.92) v1(164.45,80.1) v1(165.55,78.99) v1(166.57,78.99) v1(167.59,78.99) v1(168.66,78.99) v1(169.71,78.99) v1(170.84,78.99) v1(172.19,78.99) v1(173.9,78.99) v1(175.55,78.99) 175.69,78.99 v1(176.82,77.86) ; v1(167.93,81.39) v1(168.95,81.39) v1(169.84,81.39) v1(170.69,81.39) v1(171.91,81.39) v1(173.18,81.39) v1(174.41,81.39) v1(175.8,81.39) 176.87,81.39 v1(177.02,81.24) v1(177.65,80.6) v1(178.29,79.97) ; v1(172.63,98.85) v1(171.11,98.85) v1(169.68,98.85) v1(168.28,98.85) v1(166.88,98.85) 165.86,98.85 v1(165.61,98.61) v1(164.8,97.8) v1(164.04,97.04) v1(163.21,96.21) 162.73,95.73 v1(162.73,95.21) v1(162.73,94.07) ; v1(175.92,76.91) v1(175.05,77.77) v1(173.52,77.77) v1(171.99,77.77) v1(170.85,77.77) v1(169.84,77.77) v1(168.69,77.77) v1(167.68,77.77) v1(166.53,77.77) v1(165.03,77.77) v1(164.02,78.78) v1(162.88,79.92) v1(162.06,80.75) v1(161.17,81.64) v1(160.26,82.55) v2(160.26,83.78) ; v1(242.23,117.48) v1(240.7,117.48) v1(238.42,117.48) v1(237.02,117.48) v1(235.75,116.21) v1(234.48,114.94) v1(233.14,113.61) v1(232,112.47) v1(230.92,111.39) v1(229.59,110.05) v1(228.7,109.17) v1(227.49,107.96) v1(226.29,106.75) v1(224.95,105.42) v1(223.68,104.15) v1(222.54,104.15) v1(221.14,104.15) v1(219.62,104.15) v1(218.22,104.15) v1(216.63,102.56) v1(215.49,101.42) v1(214.22,100.15) v1(213.02,98.94) v1(211.75,97.67) v1(210.48,96.4) v1(209.23,95.16) v1(207.81,95.16) C51.2 206.31,95.16 v1(206.28,95.13) v1(205.01,95.13) v1(203.49,95.13) ; v1(216.83,71.38) v1(215.94,72.27) v1(215.05,73.16) v1(213.9,74.3) v1(212.69,75.52) v1(211.24,75.52) v1(209.84,75.52) v1(208.06,75.52) v1(206.41,75.52) v1(204.56,75.52) v1(203.49,76.59) v1(202.54,77.54) v1(201.71,78.37) ; v1(229.53,112.15) v1(228.45,111.07) v1(227.43,110.05) v1(226.41,109.04) v1(225.46,108.09) v1(224.45,107.07) v1(223.43,106.05) v1(222.79,105.42) v1(221.14,105.42) v1(219.62,105.42) v1(217.65,105.42) v1(216.41,104.18) v1(215.33,103.1) v1(213.62,101.39) v1(212.54,100.31) v1(211.46,99.23) v1(209.94,97.7) 208.69,96.46 v1(208.18,96.46) v1(206.66,96.46) v1(205.01,96.46) ; v1(192.43,109.23) v1(192.43,110.37) v1(192.43,112.02) v1(192.43,113.42) v1(192.43,114.57) v1(191.36,115.64) v1(190.15,116.85) v1(189.14,117.86) v1(188.12,118.88) v1(186.98,120.02) v1(185.83,121.16) v1(184.94,122.05) 183.67,123.33 v1(183.42,123.33) v1(181.52,123.33) v1(179.61,123.33) v1(177.71,123.33) v1(175.8,123.33) v1(173.9,123.33) v1(171.99,123.33) v1(169.96,123.33) v1(167.68,123.33) v1(166.79,124.22) v1(165.58,125.42) v1(164.69,126.31) v1(163.87,127.14) v1(162.79,128.22) v1(161.96,129.04) v1(161.01,129.99) v1(159.55,131.45) ; v1(157.99,94.83) v1(157.99,95.97) v1(157.99,96.99) 157.99,97.75 v1(158.44,98.19) v1(159.45,99.21) v1(160.22,99.97) v1(161.04,100.8) v1(161.87,101.62) v1(162.63,102.38) v1(163.6,103.35) v1(164.85,103.35) v1(166,103.35) v1(167.27,103.35) v1(168.54,103.35) v1(169.68,103.35) v1(170.98,103.35) v1(172.35,103.35) ; v1(246.92,116.49) v1(245.27,116.49) v1(243.62,116.49) v1(242.12,116.49) ; v1(172.12,89.95) v1(173.49,89.95) ; v1(175.01,104.99) 174.59,105.41 v1(173.9,105.41) v1(172.38,105.41) v1(170.98,105.41) v1(169.84,105.41) v1(168.57,105.41) v1(167.3,105.41) v1(165.77,105.41) v1(164.25,105.41) v1(162.66,105.41) v1(161.87,104.62) v1(161.04,103.8) v1(159.96,102.72) v1(159.08,101.83) v1(157.93,100.68) v1(156.85,99.61) v1(155.92,98.68) v1(155.92,97.24) v1(155.92,96.22) v1(155.92,94.95) v1(155.92,93.68) v1(155.92,92.29) v1(155.92,90.96) 155.92,90.83 v1(156.47,90.28) ; v1(201.17,107.27) 201.71,107.81 v1(201.71,108.47) v1(201.71,109.99) v1(201.71,111.64) v1(201.71,113.29) v1(201.71,114.82) v1(201.71,115.96) v1(201.71,117.1) v1(201.71,118.37) v1(201.71,119.52) v1(200.32,120.91) v1(198.85,122.37) v1(197.65,123.58) v1(196.19,125.04) v1(194.98,126.25) v1(193.46,127.77) v1(192.31,128.91) v1(190.79,130.44) v1(189.39,131.84) v1(187.87,133.36) 186.22,135.01 ; v1(216.44,111.77) v1(215.17,110.5) v1(213.9,109.23) v1(212.51,107.83) v1(211.49,106.82) v1(210.41,105.74) v1(209.14,104.47) v1(207.94,103.26) v1(207,102.32) v1(205.52,102.32) ; v1(158.78,93.68) 159.36,94.26 v1(159.36,94.57) v1(159.36,95.59) v1(159.36,96.48) v1(159.36,97.31) v1(160.03,97.98) v1(160.8,98.75) v1(161.44,99.39) v1(162.07,100.02) v1(162.64,100.59) v1(163.34,101.29) v1(164.18,102.13) v1(165.36,102.13) v1(166.38,102.13) v1(167.52,102.13) v1(168.66,102.13) v1(169.71,102.13) v1(170.82,102.13) v1(172.5,102.13) ; v1(243.62,72.15) 243.42,71.94 v1(242.1,71.94) v1(239.94,71.94) v1(238.03,71.94) v1(236.13,71.94) v1(234.22,71.94) v1(232.32,71.94) v1(230.41,71.94) v1(228.76,71.94) v1(226.53,71.94) v1(225.59,71) v1(224.25,69.67) v1(222.79,68.21) 221.22,66.63 v1(220.76,66.63) v1(218.86,66.63) v1(216.95,66.63) v1(215.05,66.63) v1(213.14,66.63) v1(211.24,66.63) v1(209.33,66.63) v1(207.94,66.63) v1(206.64,67.93) v1(205.31,69.26) v1(203.97,70.6) v1(202.51,72.06) v1(201.18,73.39) v1(199.72,74.85) v1(198.51,76.06) v1(197.72,76.84) ; v1(172.5,97.63) v1(171.66,97.63) v1(170.6,97.63) v1(169.55,97.63) v1(168.41,97.63) v1(167.27,97.63) 166.47,97.63 v1(166.38,97.55) v1(164.34,95.51) 163.96,95.13 v1(163.96,93.02) ; v1(235.37,73.92) v1(234.22,73.92) v1(232.32,73.92) v1(230.41,73.92) v1(228.89,73.92) 225.46,73.92 v1(224.76,73.22) v1(223.62,72.08) v1(222.86,71.32) C14.2 ; v1(181.77,112.53) v1(181.2,113.1) v1(180.38,113.93) 180.17,114.13 v1(178.09,114.13) v1(176.19,114.13) v1(174.28,114.13) v1(172.38,114.13) v1(170.47,114.13) v1(168.57,114.13) v1(166.66,114.13) v1(164.76,114.13) v1(162.85,114.13) v1(160.95,114.13) v1(159.04,114.13) v1(157.14,114.13) v1(155.23,114.13) v1(153.33,114.13) v1(151.42,114.13) v1(149.52,114.13) v1(147.61,114.13) v1(145.71,114.13) v1(143.8,114.13) v1(141.9,114.13) v1(139.99,114.13) v1(138.09,114.13) 137.4,114.13 v1(136.69,113.42) v1(135.74,112.47) v1(134.78,111.52) v1(133.7,110.44) v1(132.8,109.53) v1(131.1,109.53) v1(129.2,109.53) v1(127.29,109.53) v1(125.39,109.53) v1(123.48,109.53) 121.4,109.53 v1(121.13,109.8) 120.31,110.63 v1(120.31,111.26) v1(120.31,112.15) v1(120.31,113.55) v1(120.31,115.07) v1(120.31,116.34) v1(120.31,117.48) v1(121.13,118.31) 121.63,118.8 v1(122.34,118.8) v1(123.73,118.8) 124.32,118.8 v1(124.88,118.25) ; v1(163.23,83.7) 163.23,84.59 v2(163.49,84.85) ; v1(251.79,92.05) v1(251.79,90.85) v1(251.12,90.18) v1(250.1,89.16) v1(249.08,88.15) 248.45,87.51 v1(247.56,87.51) v1(246.04,87.51) v1(244.64,87.51) v1(243.37,87.51) v1(242.35,87.51) v1(241.27,88.59) v1(240.13,89.73) v1(239.18,90.69) v1(238.16,91.7) v1(235.88,91.7) v1(233.97,91.7) v1(232.07,91.7) v1(230.16,91.7) v1(228.26,91.7) v1(226.35,91.7) v1(224.45,91.7) v1(222.54,91.7) v1(220.64,91.7) v1(218.73,91.7) v1(216.83,91.7) v1(214.92,91.7) 213.9,91.7 v1(212.82,90.62) 212.33,90.13 v1(210.73,90.13) v1(208.82,90.13) v1(206.92,90.13) v1(204.63,90.13) ; v1(179.36,75.66) v1(178.34,75.66) v1(176.82,75.66) v1(175.33,75.66) v1(174.44,76.55) v1(173.52,76.55) v1(172.38,76.55) v1(170.98,76.55) v1(169.84,76.55) v1(168.82,76.55) v1(167.68,76.55) v1(166.41,76.55) v1(164.53,76.55) v1(163.35,77.73) v1(162.34,78.75) v1(161.19,79.89) v1(160.24,80.84) v1(159.29,81.79) v1(158.63,82.45) v1(158.63,83.96) v1(158.63,85.25) ; v1(241.29,72.86) v1(239.94,72.86) v1(238.03,72.86) v1(236.13,72.86) v1(234.22,72.86) v1(232.32,72.86) v1(230.41,72.86) v1(228.76,72.86) v1(226.11,72.86) v1(224.29,71.03) v1(222.89,69.64) v1(221.68,68.43) 220.8,67.55 v1(220.64,67.55) v1(218.86,67.55) v1(216.95,67.55) v1(215.05,67.55) v1(213.14,67.55) v1(211.24,67.55) v1(209.33,67.55) 208.29,67.55 v1(207.78,68.06) v1(206.51,69.33) v1(205.37,70.47) v1(203.78,72.06) v1(202.45,73.39) v1(201.05,74.79) v1(199.59,76.25) v1(198.36,77.48) ; v1(194.01,110.37) v1(194.01,112.02) v1(194.01,113.42) v1(194.01,114.82) 194.01,115.28 v1(193.58,115.71) v1(192.7,116.6) v1(191.43,117.87) v1(190.22,119.07) v1(189.14,120.15) v1(188,121.29) v1(186.85,122.44) v1(185.71,123.58) v1(184.76,124.53) 184.47,124.82 v1(183.42,124.82) v1(181.52,124.82) v1(179.61,124.82) v1(177.71,124.82) v1(175.8,124.82) v1(173.9,124.82) v1(171.99,124.82) v1(170.09,124.82) 168.46,124.82 v1(168.43,124.85) v1(167.8,125.48) v1(166.72,126.56) v1(165.83,127.45) v1(164.88,128.4) v1(163.86,129.43) v1(162.97,130.31) v1(162.08,131.2) 161.32,131.96 v1(161.32,132.72) v1(161.32,133.99) v1(161.32,135.26) v1(161.32,136.67) ; v1(185.84,79.51) v1(185.84,78.11) v1(185.84,76.97) v1(185.84,76.21) v1(184.95,75.32) v1(184.12,74.49) v1(183.17,73.54) 182.78,73.15 v1(182.15,73.15) v1(180.88,73.15) v1(179.49,73.15) v1(178.22,73.15) v1(176.82,73.15) v1(175.55,73.15) v1(174.27,73.15) v1(173.38,74.04) v1(172.38,74.04) v1(170.98,74.04) v1(169.71,74.04) v1(168.18,74.04) v1(166.53,74.04) v1(165.01,74.04) 163.5,74.04 v1(163.49,74.05) ; v1(175.68,82.69) 175.22,82.23 v1(174.41,82.23) v1(173.03,82.23) v1(171.83,82.23) v1(170.82,82.23) v1(169.71,82.23) v1(168.58,82.23) 168.31,82.23 v1(167.95,82.59) v2(167.19,83.34) v2(166.63,83.91) ; 225.59,111.9 v1(224.64,110.94) v1(223.43,109.74) v1(222.29,108.59) v1(221.27,107.58) v1(219.24,107.58) v1(216.83,107.58) v1(215.87,106.63) v1(214.73,105.48) v1(213.65,104.4) v1(212.51,103.26) v1(210.79,101.55) v1(209.59,100.34) v1(208.25,99.01) v1(207.3,98.05) ; 227.37,111.9 v1(226.54,111.07) v1(225.52,110.05) v1(224.38,108.91) v1(223.43,107.96) v1(222.03,106.56) v1(220.89,106.56) v1(219.11,106.56) v1(217.33,106.56) v1(216.13,105.36) v1(215.11,104.34) v1(213.97,103.2) v1(212.44,101.67) v1(211.17,100.4) v1(209.9,99.13) v1(208.44,97.67)
  TOP w0.508: v1(252.66,136.53) 254.32,134.88 v1(255.18,134.88) 257.47,134.88 257.85,135.26 v1(257.85,135.39) v1(257.85,137.55) ; v1(246.92,116.49) v1(248.19,116.49) 248.22,116.49 v1(248.83,117.1) v1(249.46,117.74) 250.1,118.37 v1(250.1,119.01) v1(250.1,120.28) v1(250.1,121.55) v1(250.1,122.82) v1(250.1,124.09) v1(250.1,125.36) v1(250.73,125.99) v1(251.37,126.63) v1(252,127.26) v1(252.64,127.9) ; v1(236.84,115.78) v1(238.42,115.78) v1(240.45,115.78) 241.54,115.78 242.12,116.37 v1(242.12,116.49) ; 143.17,142.5 144.11,141.56 J12.7 ; v1(242.23,117.48) v1(243.62,117.48) v1(245.27,117.48) v1(246.92,117.48) 247.31,117.48 v1(248.19,118.37) v1(248.83,119.01) v1(248.83,120.28) v1(248.83,121.55) v1(248.83,122.82) v1(248.83,124.09) v1(248.83,125.36) 248.83,125.87 v1(249.21,126.25) v1(249.97,127.01) v1(250.99,128.03) v1(250.99,128.79) v1(250.1,128.79) v1(250.1,129.8) v1(250.1,130.62) 249.46,131.25 v1(249.46,131.71) v1(249.46,132.98) v1(249.46,134.25) v1(249.46,135.49)
  TOP w0.635: 241.12,150.59 J13.4 ; J13.4 244.09,149.27 ; J13.4 247.06,150.59 ; 265.26,142.89 J13.8 ; J13.8 263.94,144.97 ; J13.8 265.26,147.05 ; J13.7 265.26,128.55 ; J13.7 266.58,126.47 ; J13.7 263.94,126.47 ; J13.7 265.26,124.39 ; 148.77,134.55 J12.6 ; J12.6 150.17,135.95 ; J12.6 151.56,134.55 ; D4.2 158.41,16.01 ; D4.2 156.37,16.01 ; D4.2 157.39,17.03 ; D4.2 157.39,15 ; 151.56,141.56 J12.5 150.17,140.16 ; J18.3 67.06,124.28 ; J18.3 68.2,123.13 ; J18.3 65.92,123.13 ; J18.3 67.06,121.99 ; C203.2 200.32,129.56 ; C203.2 199.05,128.48 ; C203.2 199.05,130.64 ; C203.2 197.78,129.56 ; 156.2,142.77 J25.21 157.34,140.74 ; J17.3 213.74,115.75 ; J17.3 213.74,113.46 ; J17.3 214.88,114.61 ; 165.4,32.06 S3.2 ; S3.2 168.45,32.06 ; S3.2 166.93,30.54 ; S3.2 166.93,33.59 ; 69.15,138.78 J29.5 ; J29.5 70.29,139.92 ; J29.5 71.43,138.78 ; J29.5 70.29,137.63 ; 145.26,104.53 C264.2 ; C264.2 146.34,103.26 ; C264.2 147.42,104.53 ; C264.2 146.34,105.8 ; 159.8,122.31 C267.2 ; C267.2 162.34,122.31 ; C267.2 161.07,121.23 ; J27.19 50.45,84.06 ; J27.19 49.37,82.98 ; J27.19 50.45,81.9 ; 60.61,81.9 J27.15 60.61,84.06 ; J27.11 70.77,84.06 ; J27.11 71.85,82.98 ; J27.11 70.77,81.9 ; J27.11 69.69,82.98 ; J27.13 65.69,84.06 ; J27.13 65.69,81.9 ; J27.13 66.77,82.98 ; J27.13 64.61,82.98 ; 52.99,84.06 J27.18 52.99,81.9 ; 172.99,142.77 J25.20 171.84,140.74 ; 67.15,82.98 J27.12 ; J27.12 69.31,82.98 ; J27.12 68.23,84.06 ; J27.12 68.23,81.9 ; C73.2 152.31,8.77 ; C73.2 151.04,9.85 ; C73.2 149.77,8.77 ; 88.49,27.82 C72.2 ; C72.2 90.65,27.82 ; C72.2 89.57,29.09 ; C72.2 89.57,26.55 ; J29.11 52.31,142.89 ; J29.11 52.31,137.56 ; J29.11 54.97,140.23 ; J29.11 49.64,140.23 ; 121.11,96.38 J21.8 122.64,95.11 ; C32.2 135.04,125.51 ; C32.2 135.04,122.97 ; C32.2 133.77,124.24 ; C32.2 136.31,124.24 ; 236.59,144.97 J13.5 ; J13.5 239.23,144.97 ; J13.5 237.91,147.05 ; J13.5 237.91,142.89 ; 143.13,38.94 J28.6 143.13,41.48 ; J1.4 255.75,74.83 ; J1.4 254.61,75.98 ; J1.4 254.61,73.69 ; J1.4 253.46,74.83 ; 156.2,148.73 J25.23 ; 147.45,134.03 J12.4 ; 55.53,81.9 J27.17 55.53,84.06 ; 74.63,140.23 J29.10 ; J29.10 77.3,137.56 ; J29.10 77.3,142.89 ; J29.10 79.97,140.23 ; 82.58,76.86 J30.22 ; C205.2 256.96,87.13 ; C205.2 255.69,86.05 ; C205.2 255.69,88.21 ; C205.2 254.42,87.13 ; 82.58,88.86 J30.10 ; 58.07,81.9 J27.16 58.07,84.06 ; 237.91,124.39 J13.6 ; J13.6 237.91,128.55 ; J13.6 236.59,126.47 ; C231.2 254.35,114.56 ; C231.2 253.27,115.83 ; C231.2 252.19,114.56 ; C231.2 253.27,113.29 ; J13.3 262.06,150.59 ; J13.3 259.09,149.27 ; J13.3 256.12,150.59 ; J19.4 147.76,122.33 ; J19.4 146.62,121.19 ; J19.4 145.48,122.33 ; J19.4 146.62,123.48 ; S3.1 160.43,33.59 ; S3.1 160.43,30.54 ; S3.1 161.95,32.06 ; J16.6 75.31,102.15 ; J16.6 73.03,102.15 ; J16.6 74.17,103.29 ; 178.91,143.27 U11.3 ; U11.3 181.07,143.27 ; U11.3 179.99,144.35 ; U11.3 179.99,142.19 ; J30.9 86.74,88.86 ; J12.8 146.13,134.55 ; J12.8 144.73,135.95 ; J12.8 143.33,134.55 ; D16.2 169.8,14.13 ; D16.2 168.72,15.21 ; D16.2 167.64,14.13 ; D16.2 168.72,13.05 ; 143.13,45.22 J15.6 143.13,42.68 ; J30.5 86.74,92.86 ; 112.27,123.45 C31.2 ; C31.2 113.54,124.72 ; C31.2 113.54,122.18 ; 62.87,102.15 J16.10 ; 132.62,88.93 C35.2 ; C35.2 135.16,88.93 ; C35.2 133.89,87.93 ; J2.4 229.31,56.05 ; J2.4 227.02,56.05 ; J2.4 228.17,57.19 ; J2.4 228.17,54.9 ; J30.21 86.74,76.86 ; J30.3 86.74,94.86 ; 150.91,82.07 C16.2 153.45,82.07 ; J27.14 63.15,84.06 ; J27.14 63.15,81.9 ; J27.14 64.23,82.98
  TOP w0.762: J30.21 J30.22 ; J30.9 J30.10 ; J34.9 J34.10
  BOTTOM w0.127: 231.8,71.26 231.8,71.51
  BOTTOM w0.381: v1(130.59,118.75) 130.59,118.5 130.23,118.13 C24.2
  BOTTOM w0.635: C39.2 240.45,105.05 ; C39.2 239.18,104.06 ; C39.2 237.91,105.05 ; 67.15,82.98 J27.12 ; J27.12 68.23,81.9 ; J27.12 69.31,82.98 ; J27.12 68.23,84.06 ; C267.2 161.07,123.39 ; C267.2 162.34,122.31 ; C267.2 159.8,122.31 ; C267.2 161.07,121.23 ; C266.2 142.53,129.36 ; C266.2 142.53,127.2 ; C266.2 143.8,128.28 ; C266.2 141.26,128.28 ; 244.09,149.27 J13.4 ; J13.4 247.06,150.59 ; J13.4 241.12,150.59 ; J29.5 71.43,138.78 ; J29.5 70.29,137.63 ; J29.5 70.29,139.92 ; J29.5 69.15,138.78 ; J16.6 75.31,102.15 ; J16.6 73.03,102.15 ; J16.6 74.17,101.01 ; J16.6 74.17,103.29 ; 228.17,54.9 J2.4 ; J2.4 227.02,56.05 ; J2.4 229.31,56.05 ; J2.4 228.17,57.19 ; 150.91,82.07 C16.2 ; C16.2 153.45,82.07 ; C16.2 152.18,81.08 ; J34.3 241.23,101.19 ; 247.23,97.03 J34.10 ; 236.59,144.97 J13.5 ; J13.5 239.23,144.97 ; J13.5 237.91,147.05 ; J13.5 237.91,142.89 ; 58.07,81.9 J27.16 ; J27.16 56.99,82.98 ; J27.16 59.15,82.98 ; J27.16 58.07,84.06 ; 160.43,30.54 S3.1 ; S3.1 161.95,32.06 ; S3.1 158.9,32.06 ; S3.1 160.43,33.59 ; J12.7 146.13,141.56 ; J12.7 144.73,140.16 ; J12.7 144.73,142.96 ; J12.7 143.33,141.56 ; 145.48,122.33 J19.4 ; J19.4 146.62,123.48 ; J19.4 147.76,122.33 ; J19.4 146.62,121.19 ; J30.5 86.74,92.86 ; 49.64,140.23 J29.11 ; J29.11 52.31,137.56 ; J29.11 52.31,142.89 ; J29.11 54.97,140.23 ; 89.57,26.55 C72.2 ; C72.2 90.65,27.82 ; C72.2 88.49,27.82 ; C72.2 89.57,29.09 ; C203.2 200.32,129.56 ; C203.2 199.05,128.48 ; C203.2 199.05,130.64 ; C203.2 197.78,129.56 ; 65.69,81.9 J27.13 ; J27.13 65.69,84.06 ; J27.13 66.77,82.98 ; J27.13 64.61,82.98 ; C73.2 151.04,9.85 ; C73.2 149.77,8.77 ; C73.2 152.31,8.77 ; C73.2 151.04,7.69 ; 255.69,86.05 C205.2 ; C205.2 255.69,88.21 ; C205.2 256.96,87.13 ; C205.2 254.42,87.13 ; 196.12,145.03 J32.9 ; J32.9 198.02,146.94 ; J32.9 196.12,148.84 ; J32.9 194.21,146.94 ; J16.10 65.15,102.15 ; J16.10 64.01,103.29 ; J16.10 64.01,101.01 ; J16.10 62.87,102.15 ; 224.12,145.03 J32.3 ; J32.3 224.12,148.84 ; J32.3 222.21,146.94 ; J32.3 226.02,146.94 ; S3.2 168.45,32.06 ; S3.2 166.93,33.59 ; S3.2 166.93,30.54 ; S3.2 165.4,32.06 ; 171.84,146.95 J25.22 ; J25.22 171.84,150.51 ; J25.22 172.99,148.73 ; J25.22 170.7,148.73 ; J12.6 150.17,135.95 ; J12.6 151.56,134.55 ; J12.6 150.17,133.15 ; J12.6 148.77,134.55 ; 259.09,149.27 J13.3 ; J13.3 262.06,150.59 ; J13.3 256.12,150.59 ; 62.07,82.98 J27.14 ; J27.14 63.15,81.9 ; J27.14 64.23,82.98 ; J27.14 63.15,84.06 ; 157.34,140.74 J25.21 ; J25.21 156.2,142.77 ; J25.21 158.49,142.77 ; D4.2 157.39,17.03 ; D4.2 156.37,16.01 ; D4.2 157.39,15 ; D4.2 158.41,16.01 ; 119.59,95.11 J21.8 ; J21.8 122.64,95.11 ; J21.8 121.11,96.38 ; 113.54,122.18 C31.2 ; C31.2 112.27,123.45 ; C31.2 113.54,124.72 ; C31.2 114.81,123.45 ; J27.17 56.61,82.98 ; J27.17 55.53,84.06 ; J27.17 54.45,82.98 ; J27.17 55.53,81.9 ; 60.61,81.9 J27.15 ; J27.15 60.61,84.06 ; J27.15 59.53,82.98 ; J27.15 61.69,82.98 ; J13.6 239.23,126.47 ; J13.6 237.91,128.55 ; J13.6 237.91,124.39 ; J13.6 236.59,126.47 ; 133.77,124.24 C32.2 ; C32.2 135.04,122.97 ; C32.2 136.31,124.24 ; C32.2 135.04,125.51 ; 179.99,142.19 U11.3 ; U11.3 179.99,144.35 ; U11.3 181.07,143.27 ; U11.3 178.91,143.27 ; J13.8 265.26,147.05 ; J13.8 263.94,144.97 ; J13.8 265.26,142.89 ; 52.99,81.9 J27.18 ; J27.18 51.91,82.98 ; J27.18 54.07,82.98 ; J27.18 52.99,84.06 ; 132.62,88.93 C35.2 ; C35.2 135.16,88.93 ; C35.2 133.89,87.93 ; C264.2 146.34,105.8 ; C264.2 147.42,104.53 ; C264.2 146.34,103.26 ; C264.2 145.26,104.53 ; C231.2 253.27,115.83 ; C231.2 253.27,113.29 ; C231.2 252.19,114.56 ; C231.2 254.35,114.56 ; J1.4 255.75,74.83 ; J1.4 253.46,74.83 ; J1.4 254.61,73.69 ; J1.4 254.61,75.98 ; 210.12,145.03 J32.6 ; J32.6 208.21,146.94 ; J32.6 212.02,146.94 ; J32.6 210.12,148.84 ; J25.23 157.34,150.51 ; J25.23 156.2,148.73 ; J25.23 157.34,146.95 ; J25.23 158.49,148.73 ; 70.77,81.9 J27.11 ; J27.11 71.85,82.98 ; J27.11 70.77,84.06 ; J27.11 69.69,82.98 ; J13.7 265.26,128.55 ; J13.7 266.58,126.47 ; J13.7 263.94,126.47 ; J13.7 265.26,124.39 ; J12.8 144.73,135.95 ; J12.8 144.73,133.15 ; J12.8 143.33,134.55 ; J12.8 146.13,134.55 ; 143.13,45.22 J15.6 143.13,42.68 ; J29.10 79.97,140.23 ; J29.10 77.3,137.56 ; J29.10 77.3,142.89 ; J29.10 74.63,140.23 ; 119.59,82.61 J21.3 122.64,82.61 ; 82.58,76.86 J30.22 ; J34.21 259.23,101.19 ; 82.58,88.86 J30.10 ; 212.59,114.61 J17.3 ; J17.3 213.74,115.75 ; J17.3 214.88,114.61 ; J17.3 213.74,113.46 ; 150.17,140.16 J12.5 ; J12.5 150.17,142.96 ; J12.5 148.77,141.56 ; J12.5 151.56,141.56 ; J27.19 51.53,82.98 ; J27.19 49.37,82.98 ; J27.19 50.45,81.9 ; J27.19 50.45,84.06 ; 197.62,100.15 C7.2 199.2,100.15 ; J34.9 247.23,101.19 ; 143.13,41.48 J28.6 143.13,38.94 ; J18.3 68.2,123.13 ; J18.3 67.06,124.28 ; J18.3 65.92,123.13 ; J18.3 67.06,121.99 ; 171.84,140.74 J25.20 ; J25.20 172.99,142.77 ; J25.20 170.7,142.77 ; J30.21 86.74,76.86 ; D16.2 168.72,15.21 ; D16.2 168.72,13.05 ; D16.2 169.8,14.13 ; D16.2 167.64,14.13 ; 119.59,80.11 J21.2 122.64,80.11 ; J30.9 86.74,88.86 ; J30.3 86.74,94.86 ; 160.91,65.16 J14.6 160.91,67.7 ; 132.75,79.78 C37.2 131.48,78.79 ; 147.45,134.03 J12.4 ; 259.23,97.03 J34.22 ; J34.5 243.23,101.19
  BOTTOM w0.762: J34.9 J34.10 ; J34.21 J34.22
  vias: v1(23.79,39.89) v1(23.79,37.35) v1(23.79,34.81) v1(23.79,32.27) v1(23.79,29.73) v1(23.79,27.19) v1(23.79,24.65) v1(23.79,22.11) v1(23.79,19.57) v1(23.79,17.03) v1(23.79,14.49) v1(23.79,11.95) v1(23.79,9.41) v1(26.33,37.35) v1(26.33,34.81) v1(26.33,32.27) v1(26.33,29.73) v1(26.33,27.19) v1(26.33,24.65) v1(26.33,22.11) v1(26.33,19.57) v1(26.33,17.03) v1(26.33,14.49) v1(26.33,11.95) v1(28.87,39.89) v1(28.87,37.35) v1(28.87,34.81) v1(28.87,32.27) v1(28.87,29.73) v1(28.87,27.19) v1(28.87,24.65) v1(28.87,22.11) v1(28.87,19.57) v1(28.87,17.03) v1(28.87,14.49) v1(28.87,11.95) v1(28.87,9.41) v1(31.41,47.51) v1(31.41,44.97) v1(31.41,42.43) v1(31.41,39.89) v1(31.41,37.35) v1(31.41,34.81) v1(31.41,32.27) v1(31.41,29.73) v1(31.41,27.19) v1(31.41,24.65) v1(31.41,22.11) v1(31.41,19.57) v1(31.41,17.03) v1(31.41,14.49) v1(31.41,11.95) v1(31.41,9.41) v1(31.41,6.87) v1(31.41,4.33) v1(31.41,1.79) v1(33.95,47.51) v1(33.95,44.97) v1(33.95,42.43) v1(33.95,39.89) v1(33.95,37.35) v1(33.95,34.81) v1(33.95,32.27) v1(33.95,29.73) v1(33.95,27.19) v1(33.95,24.65) v1(33.95,22.11) v1(33.95,19.57) v1(33.95,17.03) v1(33.95,14.49) v1(33.95,11.95) v1(33.95,9.41) v1(33.95,1.79) v1(36.49,47.51) v1(36.49,44.97) v1(36.49,42.43) v1(36.49,39.89) v1(36.49,37.35) v1(36.49,34.81) v1(36.49,32.27) v1(36.49,29.73) v1(36.49,27.19) v1(36.49,24.65) v1(36.49,22.11) v1(36.49,19.57) v1(36.49,17.03) v1(36.49,14.49) v1(36.49,11.95) v1(36.49,9.41) v1(36.49,1.79) v1(39.03,47.51) v1(39.03,44.97) v1(39.03,42.43) v1(39.03,39.89) v1(39.03,37.35) v1(39.03,34.81) v1(39.03,32.27) v1(39.03,29.73) v1(39.03,27.19) v1(39.03,24.65) v1(39.03,22.11) v1(39.03,19.57) v1(39.03,17.03) v1(39.03,14.49) v1(39.03,11.95) v1(39.03,9.41) v1(39.03,6.87) v1(39.03,4.33) v1(39.03,1.79) v1(40.93,100.21) v1(40.93,98.31) v1(40.93,96.4) v1(40.93,94.5) v1(40.93,92.59) v1(40.93,90.69) v1(40.93,81.16) v1(40.93,79.26) v1(40.93,77.35) v1(40.93,75.45) v1(40.93,73.54) v1(41.57,47.51) v1(41.57,44.97) v1(41.57,42.43) v1(41.57,39.89) v1(41.57,37.35) v1(41.57,34.81) v1(41.57,32.27) v1(41.57,29.73) v1(41.57,27.19) v1(41.57,24.65) v1(41.57,22.11) v1(41.57,19.57) v1(41.57,17.03) v1(41.57,14.49) v1(41.57,11.95) v1(41.57,9.41) v1(41.57,6.87) v1(41.57,4.33) v1(41.57,1.79) v1(41.74,142.82) v1(41.74,139.65) v1(41.74,135.84) v1(41.74,132.03) v1(41.74,129.61) v1(41.74,126.31) v1(41.74,123.26) v1(42.33,99.2) v1(42.33,97.29) v1(42.33,95.39) v1(42.33,93.48) v1(42.33,91.58) v1(42.33,89.67) v1(42.33,87.77) v1(42.33,85.86) v1(42.33,83.96) v1(42.33,82.05) v1(42.33,80.15) v1(42.33,78.24) v1(42.33,76.34) v1(42.33,74.43) v1(42.33,72.53) v1(42.55,113) v1(43.56,112.24) v1(44.11,47.51) v1(44.11,44.97) v1(44.11,42.43) v1(44.11,39.89) v1(44.11,37.35) v1(44.11,34.81) v1(44.11,32.27) v1(44.11,29.73) v1(44.11,27.19) v1(44.11,24.65) v1(44.11,22.11) v1(44.11,19.57) v1(44.11,17.03) v1(44.11,14.49) v1(44.11,11.95) v1(44.11,9.41) v1(44.11,6.87) v1(44.11,4.33) v1(44.11,1.79) v1(44.23,99.2) v1(44.23,97.29) v1(44.23,95.39) v1(44.23,93.48) v1(44.23,91.58) v1(44.23,89.67) v1(44.23,87.77) v1(44.23,74.43) v1(44.23,72.53) v1(44.45,138.59) v1(46.06,135.84) v1(46.06,132.03) v1(46.06,128.22) v1(46.06,124.41) v1(46.06,112.34) v1(46.14,99.2) v1(46.14,97.29) v1(46.14,95.39) v1(46.14,93.48) v1(46.14,91.58) v1(46.14,89.67) v1(46.14,87.77) v1(46.14,74.43) v1(46.14,72.53) v1(46.39,71.13) v1(46.65,47.51) v1(46.65,44.97) v1(46.65,42.43) v1(46.65,39.89) v1(46.65,37.35) v1(46.65,34.81) v1(46.65,32.27) v1(46.65,29.73) v1(46.65,27.19) v1(46.65,24.65) v1(46.65,22.11) v1(46.65,19.57) v1(46.65,17.03) v1(46.65,14.49) v1(46.65,11.95) v1(46.65,9.41) v1(46.65,6.87) v1(46.65,4.33) v1(46.65,1.79) v1(48.04,101.1) v1(48.04,99.2) v1(48.04,97.29) v1(48.04,95.39) v1(48.04,70.62) v1(48.42,106.05) v1(48.42,68.72) v1(48.8,63.89) v1(49.19,47.51) v1(49.19,44.97) v1(49.19,42.43) v1(49.19,39.89) v1(49.19,37.35) v1(49.19,34.81) v1(49.19,32.27) v1(49.19,29.73) v1(49.19,27.19) v1(49.19,24.65) v1(49.19,22.11) v1(49.19,19.57) v1(49.19,17.03) v1(49.19,14.49) v1(49.19,11.95) v1(49.19,9.41) v1(49.19,6.87) v1(49.19,4.33) v1(49.19,1.79) v1(49.79,151.07) v1(49.79,148.78) v1(49.79,146.37) v1(49.87,135.84) v1(49.87,132.03) v1(49.87,128.22) v1(49.87,124.41) v1(49.87,120.6) v1(49.87,116.15) v1(49.87,113.74) v1(49.95,101.1) v1(49.95,99.2) v1(49.95,97.29) v1(49.95,78.75) v1(49.95,76.84) v1(49.95,74.94) v1(49.95,68.72) v1(50.07,93.48) v1(50.07,91.58) v1(50.07,89.67) v1(50.07,87.77) v1(50.07,85.86) v1(50.46,106.31) v1(50.71,63.89) v1(51.73,47.51) v1(51.73,44.97) v1(51.73,42.43) v1(51.73,39.89) v1(51.73,37.35) v1(51.73,34.81) v1(51.73,32.27) v1(51.73,29.73) v1(51.73,27.19) v1(51.73,24.65) v1(51.73,22.11) v1(51.73,19.57) v1(51.73,17.03) v1(51.73,14.49) v1(51.73,11.95) v1(51.73,9.41) v1(51.73,6.87) v1(51.73,4.33) v1(51.73,1.79) v1(51.85,101.1) v1(51.85,99.2) v1(51.85,78.75) v1(51.85,76.84) v1(51.85,74.94) v1(51.85,73.03) v1(51.85,68.72) v1(51.98,95.39) v1(51.98,93.48) v1(51.98,91.58) v1(52.61,105.8) v1(52.61,103.9) v1(52.61,101.99) v1(52.61,63.89) v1(52.87,89.54) v1(52.87,87.64) v1(52.87,85.73) v1(52.97,151.07) v1(52.97,148.78) v1(52.97,146.24) v1(53.04,135.84) v1(53.04,132.03) v1(53.04,128.22) v1(53.04,124.41) v1(53.04,120.6) v1(53.04,116.15) v1(53.04,113.74) v1(53.76,101.1) v1(53.76,78.75) v1(53.76,76.84) v1(53.76,74.94) v1(53.76,73.03) v1(53.76,68.72) v1(53.76,66.81) v1(53.76,64.91) v1(53.88,97.29) v1(53.88,95.39) v1(53.88,93.48) v1(54.27,47.51) v1(54.27,44.97) v1(54.27,42.43) v1(54.27,39.89) v1(54.27,34.81) v1(54.27,32.27) v1(54.27,27.19) v1(54.27,24.65) v1(54.27,22.11) v1(54.27,19.57) v1(54.27,17.03) v1(54.27,14.49) v1(54.27,11.95) v1(54.27,9.41) v1(54.27,6.87) v1(54.27,4.33) v1(54.27,1.79) v1(54.52,105.8) v1(54.52,103.9) v1(54.52,101.99) v1(54.52,63.89) v1(55.54,91.45) v1(55.54,89.54) v1(55.54,87.64) v1(55.54,85.73) v1(55.66,78.75) v1(55.66,76.84) v1(55.66,74.94) v1(55.66,73.03) v1(55.66,66.81) v1(55.66,64.91) v1(55.79,99.2) v1(55.79,97.29) v1(55.79,95.39) v1(56.14,151.07) v1(56.14,148.78) v1(56.14,146.24) v1(56.16,124.79) v1(56.22,135.84) v1(56.22,132.03) v1(56.22,128.22) v1(56.22,120.6) v1(56.22,116.15) v1(56.27,112.59) v1(56.42,107.71) v1(56.42,105.8) v1(56.42,103.9) v1(56.42,101.99) v1(56.42,63.89) v1(56.42,28.08) v1(56.81,47.51) v1(56.81,44.97) v1(56.81,42.43) v1(56.81,39.89) v1(56.81,34.81) v1(56.81,32.27) v1(56.81,24.65) v1(56.81,22.11) v1(56.81,19.57) v1(56.81,17.03) v1(56.81,14.49) v1(56.81,11.95) v1(56.81,9.41) v1(56.81,6.87) v1(56.81,4.33) v1(56.81,1.79) v1(57.01,141.83) v1(57.57,78.75) v1(57.57,76.84) v1(57.57,74.94) v1(57.57,73.03) v1(57.57,66.81) v1(57.57,64.91) v1(58.08,93.35) v1(58.08,91.45) v1(58.08,89.54) v1(58.08,87.64) v1(58.08,85.73) v1(58.33,107.71) v1(58.33,105.8) v1(58.33,103.9) v1(58.33,101.99) v1(58.33,63.89) v1(58.58,94.88) v1(59.06,135.04) v1(59.06,127.92) v1(59.18,131.99) v1(59.18,124.62) v1(59.32,151.07) v1(59.32,148.78) v1(59.32,146.24) v1(59.35,47.51) v1(59.35,44.97) v1(59.35,42.43) v1(59.35,40.27) v1(59.35,22.11) v1(59.35,19.57) v1(59.35,17.03) v1(59.35,14.49) v1(59.35,11.95) v1(59.35,9.41) v1(59.35,6.87) v1(59.35,4.33) v1(59.35,1.79) v1(59.47,78.75) v1(59.47,76.84) v1(59.47,74.94) v1(59.47,73.03) v1(59.47,68.72) v1(59.47,66.81) v1(59.47,64.91) v1(60.03,120.6) v1(60.03,116.15) v1(60.03,112.34) v1(59.98,39) v1(60.11,36.97) v1(60.11,32.27) v1(60.23,107.71) v1(60.23,105.8) v1(60.23,103.9) v1(60.23,101.99) v1(60.23,96.53) v1(60.23,63.89) v1(60.49,91.45) v1(60.49,89.54) v1(60.49,87.64) v1(60.49,85.73) v1(60.58,130.59) v1(60.62,94.62) v1(60.74,99.58) v1(61.22,136.05) v1(61.34,126.65) v1(61.38,70.62) v1(61.38,68.72) v1(61.38,66.81) v1(61.38,64.91) v1(61.38,29.09) v1(61.81,134.69) v1(61.81,130.88) v1(61.84,124.94) v1(61.89,47.51) v1(61.89,44.97) v1(61.89,42.43) v1(61.89,40.27) v1(61.89,22.11) v1(61.89,19.57) v1(61.89,17.03) v1(61.89,14.49) v1(61.89,11.95) v1(61.89,9.41) v1(61.89,6.87) v1(61.89,4.33) v1(61.89,1.79) v1(62.01,39) v1(62.01,34.3) v1(62.09,128.75) v1(62.14,107.71) v1(62.14,105.8) v1(62.14,103.9) v1(62.14,101.23) v1(62.14,35.57) v1(62.14,26.43) v1(62.27,96.53) v1(62.49,151.07) v1(62.49,148.78) v1(62.49,146.24) v1(62.65,69.61) v1(62.77,99.07) v1(62.77,31.76) v1(62.9,93.48) v1(62.9,91.58) v1(62.9,89.67) v1(62.9,87.77) v1(62.9,85.86) v1(62.9,78.24) v1(62.9,76.34) v1(62.9,74.43) v1(62.9,72.15) v1(63.28,66.81) v1(63.28,64.91) v1(63.66,98.05) v1(63.66,34.17) v1(63.84,120.6) v1(63.84,116.15) v1(63.84,112.34) v1(63.79,28.84) v1(63.92,31.76) v1(64.04,107.71) v1(64.04,105.8) v1(64.17,104.28) v1(64.43,47.51) v1(64.43,44.97) v1(64.43,42.43) v1(64.43,40.27) v1(64.43,19.57) v1(64.43,17.03) v1(64.43,14.49) v1(64.43,11.95) v1(64.43,9.41) v1(64.43,6.87) v1(64.43,4.33) v1(64.43,1.79) v1(64.68,39) v1(64.68,37.09) v1(64.81,95.39) v1(64.81,93.48) v1(64.81,91.58) v1(64.81,89.67) v1(64.81,87.77) v1(64.81,85.86) v1(64.81,78.24) v1(64.81,76.34) v1(64.81,74.43) v1(64.81,72.15) v1(64.93,24.39) v1(65.19,66.81) v1(65.19,64.91) v1(65.29,136.59) v1(65.29,134.05) v1(65.29,131.64) v1(65.29,129.35) v1(65.67,151.07) v1(65.67,148.78) v1(65.67,146.24) v1(65.7,35.57) v1(65.7,32.65) v1(65.95,107.71) v1(65.95,105.8) v1(65.95,103.9) v1(65.95,27.7) v1(66.16,125.06) v1(66.08,69.61) v1(66.3,126.56) v1(66.46,95.01) v1(66.46,24.77) v1(66.46,23.25) v1(66.71,91.58) v1(66.71,89.67) v1(66.71,87.77) v1(66.71,85.86) v1(66.71,78.24) v1(66.71,76.34) v1(66.71,74.43) v1(66.71,72.15) v1(66.71,28.33) v1(66.97,47.51) v1(66.97,44.97) v1(66.97,42.43) v1(66.97,39.89) v1(66.97,17.03) v1(66.97,14.49) v1(66.97,11.95) v1(66.97,9.41) v1(66.97,6.87) v1(66.97,4.33) v1(66.97,1.79) v1(67.01,135.84) v1(67.01,132.03) v1(67.01,128.22) v1(67.01,124.41) v1(67.01,120.6) v1(67.01,116.15) v1(67.01,112.34) v1(67.09,66.81) v1(67.09,64.91) v1(67.22,97.93) v1(67.35,96.53) v1(67.47,27.7) v1(67.73,22.62) v1(67.85,107.71) v1(67.85,105.8) v1(67.85,103.9) v1(67.85,95.01) v1(67.85,93.1) v1(67.85,32.14) v1(67.85,24.65) v1(67.98,69.61) v1(67.98,34.81) v1(68.62,89.67) v1(68.62,87.77) v1(68.62,85.86) v1(68.62,78.24) v1(68.62,76.34) v1(68.62,74.43) v1(68.62,72.15) v1(68.74,36.84) v1(68.84,151.07) v1(68.84,148.78) v1(68.84,146.24) v1(69,66.81) v1(69,64.91) v1(69,29.22) v1(69.12,24.39) v1(69.25,21.73) v1(69.51,47.51) v1(69.51,44.97) v1(69.51,42.43) v1(69.51,39.89) v1(69.51,34.81) v1(69.51,32.27) v1(69.51,11.95) v1(69.51,9.41) v1(69.51,6.87) v1(69.51,4.33) v1(69.51,1.79) v1(69.76,107.71) v1(69.76,105.8) v1(69.76,103.9) v1(69.89,69.61) v1(69.89,63.89) v1(70.01,97.16) v1(70.01,95.26) v1(70.01,93.35) v1(70.19,135.84) v1(70.19,132.03) v1(70.19,128.22) v1(70.19,124.41) v1(70.19,120.6) v1(70.19,116.15) v1(70.19,112.34) v1(70.39,20.96) v1(70.52,87.77) v1(70.52,85.86) v1(70.52,78.24) v1(70.52,76.34) v1(70.52,74.43) v1(70.52,72.15) v1(70.65,24.77) v1(70.9,66.81) v1(70.9,64.91) v1(70.9,27.31) v1(71.66,107.71) v1(71.66,105.8) v1(71.66,103.9) v1(71.79,69.61) v1(71.79,63.89) v1(71.92,24.39) v1(72.02,151.07) v1(72.02,148.78) v1(72.02,146.24) v1(72.05,97.16) v1(72.05,95.26) v1(72.05,93.35) v1(72.05,91.45) v1(72.05,47.51) v1(72.05,44.97) v1(72.05,42.43) v1(72.05,39.89) v1(72.05,37.35) v1(72.05,34.81) v1(72.05,32.27) v1(72.05,29.73) v1(72.05,20.2) v1(72.05,9.41) v1(72.05,6.87) v1(72.05,4.33) v1(72.05,1.79) v1(72.43,85.86) v1(72.43,83.96) v1(72.43,82.05) v1(72.43,80.15) v1(72.43,78.24) v1(72.43,76.34) v1(72.43,74.43) v1(72.43,72.15) v1(72.81,66.81) v1(72.81,64.91) v1(73.57,107.71) v1(73.57,105.8) v1(73.57,103.9) v1(73.7,63.89) v1(74,135.84) v1(74,132.03) v1(74,128.22) v1(74,124.41) v1(74,120.6) v1(74,116.15) v1(74,112.34) v1(74.2,97.16) v1(74.2,95.26) v1(74.2,93.35) v1(74.2,91.45) v1(74.2,89.54) v1(74.33,83.96) v1(74.33,82.05) v1(74.33,80.15) v1(74.33,78.24) v1(74.33,76.34) v1(74.33,74.43) v1(74.33,72.15) v1(74.59,47.51) v1(74.59,44.97) v1(74.59,42.43) v1(74.59,39.89) v1(74.59,37.35) v1(74.59,34.81) v1(74.59,32.27) v1(74.59,29.73) v1(74.59,27.19) v1(74.59,24.65) v1(74.59,22.11) v1(74.59,19.57) v1(74.59,17.28) v1(74.59,9.41) v1(74.59,6.87) v1(74.59,4.33) v1(74.59,1.79) v1(74.71,69.99) v1(74.71,68.72) v1(74.71,66.81) v1(74.71,64.91) v1(75.47,107.71) v1(75.47,105.8) v1(75.47,103.9) v1(75.6,63.89) v1(75.68,87.56) v1(75.83,151.07) v1(75.83,148.78) v1(75.83,146.24) v1(76.24,82.05) v1(76.24,80.15) v1(76.24,78.24) v1(76.24,76.34) v1(76.24,74.43) v1(76.24,72.15) v1(76.57,86.17) v1(76.62,143.52) v1(76.62,66.81) v1(76.62,64.91) v1(77.13,47.51) v1(77.13,44.97) v1(77.13,42.43) v1(77.13,39.89) v1(77.13,37.35) v1(77.13,34.81) v1(77.13,32.27) v1(77.13,29.73) v1(77.13,27.19) v1(77.13,24.65) v1(77.13,22.11) v1(77.13,19.57) v1(77.13,17.03) v1(77.13,9.41) v1(77.13,6.87) v1(77.13,4.33) v1(77.13,1.79) v1(77.22,113.25) v1(77.38,105.8) v1(77.38,103.9) v1(77.38,101.99) v1(77.38,100.09) v1(77.38,98.18) v1(77.38,96.28) v1(77.38,94.37) v1(77.38,92.47) v1(77.38,90.56) v1(77.51,63.89) v1(77.81,135.84) v1(77.81,132.03) v1(77.81,128.22) v1(77.81,124.41) v1(77.81,120.6) v1(77.81,116.15) v1(78.14,86.75) v1(78.14,74.43) v1(78.14,72.15) v1(78.52,66.43) v1(78.52,64.91) v1(79.16,79.51) v1(79.16,77.61) v1(79.28,105.8) v1(79.28,103.9) v1(79.28,101.99) v1(79.28,100.09) v1(79.28,98.18) v1(79.28,96.28) v1(79.28,94.37) v1(79.28,92.47) v1(79.28,90.56) v1(79.28,88.66) v1(79.41,63.89) v1(79.64,151.07) v1(79.64,148.78) v1(79.64,146.24) v1(79.63,113.38) v1(79.67,47.51) v1(79.67,44.97) v1(79.67,42.43) v1(79.67,39.89) v1(79.67,37.35) v1(79.67,34.81) v1(79.67,32.27) v1(79.67,29.73) v1(79.67,27.19) v1(79.67,24.65) v1(79.67,22.11) v1(79.67,19.57) v1(79.67,17.03) v1(79.67,9.41) v1(79.67,6.87) v1(79.67,4.33) v1(79.67,1.79) v1(79.88,141.39) v1(80.05,72.15) v1(80.39,139.1) v1(80.43,70.62) v1(80.43,68.72) v1(80.43,66.81) v1(80.43,64.91) v1(80.88,83.32) v1(80.94,82.18) v1(80.94,81.16) v1(80.98,135.84) v1(80.98,132.03) v1(80.98,128.22) v1(80.98,124.41) v1(80.98,120.6) v1(80.98,116.15) v1(81.06,84.46) v1(81.06,79.51) v1(81.06,77.61) v1(81.19,105.8) v1(81.19,101.99) v1(81.19,100.09) v1(81.19,98.18) v1(81.19,96.28) v1(81.19,94.37) v1(81.19,92.47) v1(81.19,90.56) v1(81.19,88.66) v1(81.19,86.5) v1(81.57,73.8) v1(81.7,76.08) v1(82.21,47.51) v1(82.21,44.97) v1(82.21,42.43) v1(82.21,39.89) v1(82.21,37.35) v1(82.21,34.81) v1(82.21,32.27) v1(82.21,29.73) v1(82.21,27.19) v1(82.21,24.65) v1(82.21,22.11) v1(82.21,19.57) v1(82.21,17.03) v1(82.21,9.41) v1(82.21,6.87) v1(82.21,4.33) v1(82.21,1.79) v1(82.33,81.16) v1(82.33,72.53) v1(82.33,70.62) v1(82.46,84.59) v1(82.46,83.32) v1(82.46,82.18) v1(82.68,113.38) v1(82.94,151.07) v1(83.09,98.18) v1(83.58,124.53) v1(83.98,99.45) v1(84.16,142.82) v1(84.16,139.65) v1(84.16,135.84) v1(84.16,132.03) v1(84.16,128.22) v1(84.24,72.53) v1(84.62,73.8) v1(84.75,47.51) v1(84.75,44.97) v1(84.75,42.43) v1(84.75,39.89) v1(84.75,37.35) v1(84.75,34.81) v1(84.75,32.27) v1(84.75,29.73) v1(84.75,27.19) v1(84.75,24.65) v1(84.75,22.11) v1(84.75,19.57) v1(84.75,17.03) v1(84.75,9.41) v1(84.75,6.87) v1(84.75,4.33) v1(84.75,1.79) v1(85,98.18) v1(85.22,112.11) v1(85.25,16.01) v1(86.14,72.53) v1(86.4,17.03) v1(86.4,15.63) v1(86.65,83.7) v1(86.78,82.05) v1(86.78,79.77) v1(86.9,98.18) v1(87.03,10.8) v1(87.33,142.82) v1(87.33,139.65) v1(87.33,135.84) v1(87.33,132.03) v1(87.33,128.22) v1(87.33,112.34) v1(87.29,47.51) v1(87.29,44.97) v1(87.29,42.43) v1(87.29,39.89) v1(87.29,37.35) v1(87.29,34.81) v1(87.29,32.27) v1(87.29,29.73) v1(87.29,27.19) v1(87.29,24.65) v1(87.29,6.87) v1(87.29,4.33) v1(87.29,1.79) v1(87.41,15.25) v1(87.67,96.28) v1(87.67,94.37) v1(87.67,92.47) v1(87.67,90.56) v1(87.67,88.66) v1(87.67,86.75) v1(87.67,84.85) v1(87.67,17.03) v1(88.05,82.05) v1(88.05,80.15) v1(88.05,78.24) v1(88.05,76.34) v1(88.05,74.43) v1(88.05,72.53) v1(88.27,113.64) v1(88.43,15) v1(88.52,121.76) v1(88.78,112.59) v1(88.81,99.2) v1(88.81,97.29) v1(88.81,95.39) v1(88.81,93.48) v1(88.81,91.58) v1(88.81,89.67) v1(88.81,87.77) v1(88.81,85.86) v1(88.81,83.96) v1(88.94,150.89) v1(88.94,17.03) v1(89.06,10.8) v1(89.16,143.48) v1(89.14,124.81) v1(89.27,122.78) v1(89.32,14.61) v1(89.4,141.96) v1(89.42,127.58) v1(89.62,139.77) v1(89.83,47.51) v1(89.83,44.97) v1(89.83,42.43) v1(89.83,39.89) v1(89.83,37.35) v1(89.83,34.81) v1(89.83,32.27) v1(89.83,29.85) v1(89.83,24.65) v1(89.83,6.87) v1(89.83,4.33) v1(89.83,1.79) v1(90.21,16.9) v1(90.33,14.11) v1(91.1,10.68) v1(91.35,26.17) v1(91.48,16.9) v1(91.48,13.73) v1(92.37,47.51) v1(92.37,44.97) v1(92.37,42.43) v1(92.37,39.89) v1(92.37,37.35) v1(92.37,6.87) v1(92.37,4.33) v1(92.37,1.79) v1(92.75,19.95) v1(92.87,17.03) v1(92.87,11.44) v1(93.13,31.89) v1(93.13,29.6) v1(93.13,13.85) v1(93.25,14.87) v1(93.64,22.87) v1(93.76,124.09) v1(93.76,122.18) v1(93.76,120.28) v1(93.76,119.01) v1(93.76,117.1) v1(93.76,115.2) v1(93.76,113.29) v1(93.76,111.39) v1(93.76,109.48) v1(94.02,19.95) v1(94.14,99.83) v1(94.14,97.93) v1(94.14,96.02) v1(94.14,94.12) v1(94.14,92.21) v1(94.14,90.31) v1(94.14,88.4) v1(94.14,86.5) v1(94.14,84.59) v1(94.14,82.69) v1(94.14,73.16) v1(94.14,71.26) v1(94.14,16.77) v1(94.27,35.32) v1(94.27,30.24) v1(94.65,28.46) v1(94.91,47.51) v1(94.91,44.97) v1(94.91,42.43) v1(94.91,39.89) v1(94.91,32.65) v1(94.91,6.87) v1(94.91,4.33) v1(94.91,1.79) v1(95.29,13.73) v1(95.41,26.68) v1(95.41,20.08) v1(95.54,16.9) v1(95.67,124.09) v1(95.67,122.18) v1(95.67,113.29) v1(95.67,111.39) v1(95.67,11.82) v1(95.79,120.41) v1(95.92,119.14) v1(96.05,99.83) v1(96.05,97.93) v1(96.05,96.02) v1(96.05,94.12) v1(96.05,92.21) v1(96.05,90.31) v1(96.05,88.4) v1(96.05,86.5) v1(96.05,84.59) v1(96.05,82.69) v1(96.05,80.78) v1(96.05,78.88) v1(96.05,76.97) v1(96.05,75.07) v1(96.05,73.16) v1(96.05,71.26) v1(96.3,34.05) v1(96.3,24.65) v1(96.43,16.9) v1(96.56,20.2) v1(97.19,37.73) v1(97.19,15.5) v1(97.32,29.6) v1(97.32,12.07) v1(97.45,124.6) v1(97.45,47.51) v1(97.45,44.97) v1(97.45,42.43) v1(97.45,6.87) v1(97.45,4.33) v1(97.45,1.79) v1(97.57,113.67) v1(97.57,111.39) v1(97.7,13.73) v1(97.95,99.83) v1(97.95,97.93) v1(97.95,96.02) v1(97.95,94.12) v1(97.95,92.21) v1(97.95,90.31) v1(97.95,88.4) v1(97.95,86.5) v1(97.95,84.59) v1(97.95,82.69) v1(97.95,80.78) v1(97.95,78.88) v1(97.95,76.97) v1(97.95,75.07) v1(97.95,73.16) v1(97.95,20.58) v1(97.95,16.77) v1(98.08,114.94) v1(98.46,34.68) v1(98.84,24.65) v1(98.97,31) v1(98.97,28.71) v1(99.1,12.58) v1(99.22,116.72) v1(99.22,20.58) v1(99.35,16.9) v1(99.48,115.2) v1(99.48,113.67) v1(99.48,111.39) v1(99.48,39.89) v1(99.73,118.37) v1(99.86,99.83) v1(99.86,97.93) v1(99.86,96.02) v1(99.86,94.12) v1(99.86,92.21) v1(99.86,90.31) v1(99.86,88.4) v1(99.86,86.5) v1(99.86,84.59) v1(99.86,82.69) v1(99.86,80.78) v1(99.86,78.88) v1(99.86,76.97) v1(99.86,75.07) v1(99.86,73.16) v1(99.86,71.26) v1(99.99,47.51) v1(99.99,44.97) v1(99.99,6.87) v1(99.99,4.33) v1(99.99,1.79) v1(100.49,20.46) v1(100.49,13.22) v1(100.49,10.55) v1(100.62,31) v1(100.87,16.9) v1(101,37.22) v1(101,34.68) v1(101.26,28.58) v1(101.38,116.72) v1(101.38,115.2) v1(101.38,113.29) v1(101.38,24.65) v1(101.76,118.5) v1(101.76,103.64) v1(101.76,101.74) v1(101.76,99.83) v1(101.76,97.93) v1(101.76,96.02) v1(101.76,94.12) v1(101.76,92.21) v1(101.76,90.31) v1(101.76,88.4) v1(101.76,86.5) v1(101.76,84.59) v1(101.76,82.69) v1(101.76,80.78) v1(101.76,78.88) v1(101.76,76.97) v1(101.76,75.07) v1(101.76,73.16) v1(101.76,71.26) v1(101.89,20.84) v1(102.27,29.47) v1(102.4,14.23) v1(102.53,6.87) v1(102.53,4.33) v1(102.53,1.79) v1(103.16,20.08) v1(103.16,18.42) v1(103.29,48.02) v1(103.31,22.89) v1(103.54,118.5) v1(103.54,37.22) v1(103.54,34.68) v1(103.67,103.64) v1(103.67,101.74) v1(103.67,99.83) v1(103.67,97.93) v1(103.67,96.02) v1(103.67,94.12) v1(103.67,92.21) v1(103.67,90.31) v1(103.67,88.4) v1(103.67,86.5) v1(103.67,84.59) v1(103.67,82.69) v1(103.67,80.78) v1(103.67,78.88) v1(103.67,76.97) v1(103.67,75.07) v1(103.67,73.16) v1(103.67,71.26) v1(103.67,69.35) v1(103.67,67.45) v1(103.67,65.54) v1(103.92,42.55) v1(104.43,24.65) v1(104.43,23.38) v1(104.94,20.33) v1(104.94,16.52) v1(104.94,14.23) v1(105.07,21.98) v1(105.07,11.95) v1(105.07,9.41) v1(105.07,6.87) v1(105.07,4.33) v1(105.07,1.79) v1(105.19,28.84) v1(105.32,46.49) v1(105.45,118.5) v1(105.57,103.64) v1(105.57,101.74) v1(105.57,99.83) v1(105.57,97.93) v1(105.57,96.02) v1(105.57,94.12) v1(105.57,92.21) v1(105.57,90.31) v1(105.57,88.4) v1(105.57,86.5) v1(105.57,84.59) v1(105.57,82.69) v1(105.57,80.78) v1(105.57,78.88) v1(105.57,76.97) v1(105.57,75.07) v1(105.57,73.16) v1(105.57,71.26) v1(105.57,69.35) v1(105.57,67.45) v1(105.57,65.54) v1(105.57,63.64) v1(105.83,48.02) v1(106.08,37.22) v1(106.08,34.68) v1(106.21,33.16) v1(106.46,62.87) v1(106.46,42.55) v1(106.59,117.36) v1(106.59,17.79) v1(106.84,21.47) v1(106.97,30.74) v1(106.97,24.65) v1(106.97,23.38) v1(107.35,26.3) v1(107.48,103.64) v1(107.48,101.74) v1(107.48,99.83) v1(107.48,97.93) v1(107.48,96.02) v1(107.48,94.12) v1(107.48,92.21) v1(107.48,90.31) v1(107.48,88.4) v1(107.48,86.5) v1(107.48,84.59) v1(107.48,82.69) v1(107.48,80.78) v1(107.48,78.88) v1(107.48,76.97) v1(107.48,75.07) v1(107.48,73.16) v1(107.48,71.26) v1(107.48,69.35) v1(107.48,67.45) v1(107.48,65.54) v1(107.48,63.64) v1(107.48,15.63) v1(107.6,115.33) v1(107.6,114.06) v1(107.6,112.66) v1(107.61,14.23) v1(107.61,11.95) v1(107.61,9.41) v1(107.61,6.87) v1(107.61,4.33) v1(107.61,1.79) v1(107.73,19.44) v1(107.86,46.49) v1(107.99,28.2) v1(108.37,62.87) v1(108.37,48.02) v1(108.62,37.22) v1(108.62,34.68) v1(108.75,17.41) v1(108.87,115.33) v1(108.87,114.06) v1(108.87,112.66) v1(109,42.55) v1(109.38,103.64) v1(109.38,101.74) v1(109.38,99.83) v1(109.38,97.93) v1(109.38,96.02) v1(109.38,94.12) v1(109.38,92.21) v1(109.38,90.31) v1(109.38,88.4) v1(109.38,86.5) v1(109.38,84.59) v1(109.38,82.69) v1(109.38,80.78) v1(109.38,78.88) v1(109.38,76.97) v1(109.38,75.07) v1(109.38,73.16) v1(109.38,71.26) v1(109.38,69.35) v1(109.38,67.45) v1(109.38,65.54) v1(109.38,63.64) v1(109.38,21.22) v1(109.51,24.65) v1(109.51,23.38) v1(109.89,110.25) v1(110.14,115.33) v1(110.14,114.06) v1(110.14,112.66) v1(110.15,11.95) v1(110.15,9.41) v1(110.15,6.87) v1(110.15,4.33) v1(110.15,1.79) v1(110.27,109.1) v1(110.27,62.87) v1(110.4,46.49) v1(110.78,25.79) v1(110.91,124.85) v1(110.91,123.2) v1(110.91,121.8) v1(110.91,48.02) v1(111.16,37.22) v1(111.16,34.68) v1(111.29,111.64) v1(111.29,108.85) v1(111.29,103.64) v1(111.29,101.74) v1(111.29,99.83) v1(111.29,97.93) v1(111.29,96.02) v1(111.29,94.12) v1(111.29,92.21) v1(111.29,90.31) v1(111.29,88.4) v1(111.29,86.5) v1(111.29,84.59) v1(111.29,82.69) v1(111.29,80.78) v1(111.29,78.88) v1(111.29,76.97) v1(111.29,75.07) v1(111.29,73.16) v1(111.29,71.26) v1(111.29,69.35) v1(111.29,67.45) v1(111.29,65.54) v1(111.29,63.64) v1(111.29,17.15) v1(111.42,21.09) v1(111.54,42.55) v1(111.67,30.74) v1(111.67,28.58) v1(111.8,110.63) v1(112.05,24.65) v1(112.05,23.38) v1(112.18,113.04) v1(112.18,62.87) v1(112.43,124.85) v1(112.69,121.8) v1(112.69,18.17) v1(112.69,11.95) v1(112.69,9.41) v1(112.69,6.87) v1(112.69,4.33) v1(112.69,1.79) v1(112.81,110.5) v1(112.94,109.36) v1(112.94,46.49) v1(113.19,103.64) v1(113.19,101.74) v1(113.19,99.83) v1(113.19,97.93) v1(113.19,96.02) v1(113.19,94.12) v1(113.19,92.21) v1(113.19,90.31) v1(113.19,88.4) v1(113.19,86.5) v1(113.19,84.59) v1(113.19,82.69) v1(113.19,80.78) v1(113.19,78.88) v1(113.19,76.97) v1(113.19,75.07) v1(113.19,73.16) v1(113.19,71.26) v1(113.19,69.35) v1(113.19,67.45) v1(113.19,65.54) v1(113.19,63.64) v1(113.19,15.5) v1(113.45,113.04) v1(113.45,111.64) v1(113.45,48.02) v1(113.45,25.92) v1(113.57,20.96) v1(113.7,37.22) v1(113.7,34.68) v1(113.96,28.46) v1(114.08,109.36) v1(114.08,62.87) v1(114.08,42.55) v1(114.08,30.62) v1(114.46,124.98) v1(114.46,121.8) v1(114.59,110.63) v1(114.59,24.65) v1(114.59,23.38) v1(114.72,113.04) v1(114.72,111.77) v1(115.1,103.64) v1(115.1,101.74) v1(115.1,99.83) v1(115.1,97.93) v1(115.1,96.02) v1(115.1,94.12) v1(115.1,92.21) v1(115.1,90.31) v1(115.1,88.4) v1(115.1,86.5) v1(115.1,84.59) v1(115.1,82.69) v1(115.1,80.78) v1(115.1,78.88) v1(115.1,76.97) v1(115.1,75.07) v1(115.1,73.16) v1(115.1,71.26) v1(115.1,69.35) v1(115.1,67.45) v1(115.1,65.54) v1(115.1,63.64) v1(115.23,11.95) v1(115.23,9.41) v1(115.23,6.87) v1(115.23,4.33) v1(115.23,1.79) v1(115.48,109.74) v1(115.48,46.49) v1(115.73,17.03) v1(115.86,113.17) v1(115.99,62.87) v1(115.99,48.02) v1(116.11,111.13) v1(116.24,37.22) v1(116.24,34.68) v1(116.5,114.82) v1(116.62,112.15) v1(116.62,42.55) v1(116.62,21.35) v1(117,103.64) v1(117,101.74) v1(117,99.83) v1(117,97.93) v1(117,96.02) v1(117,94.12) v1(117,92.21) v1(117,90.31) v1(117,88.4) v1(117,86.5) v1(117,84.59) v1(117,82.69) v1(117,80.78) v1(117,78.88) v1(117,76.97) v1(117,75.07) v1(117,73.16) v1(117,71.26) v1(117,69.35) v1(117,67.45) v1(117,65.54) v1(117,63.64) v1(117.13,24.65) v1(117.13,23.38) v1(117.38,109.99) v1(117.51,25.66) v1(117.77,19.57) v1(117.77,17.03) v1(117.77,14.49) v1(117.77,11.95) v1(117.77,9.41) v1(117.77,6.87) v1(117.77,4.33) v1(117.77,1.79) v1(117.89,62.87) v1(117.89,30.62) v1(118.02,46.49) v1(118.02,28.46) v1(118.53,48.02) v1(118.78,44.84) v1(118.78,37.22) v1(118.78,34.68) v1(118.91,118.5) v1(118.91,116.6) v1(118.91,114.69) v1(118.91,112.79) v1(118.91,73.16) v1(118.91,71.26) v1(118.91,69.35) v1(118.91,67.45) v1(118.91,65.54) v1(118.91,63.64) v1(119.67,24.65) v1(119.67,23.38) v1(119.8,62.87) v1(119.8,26.55) v1(120.31,19.57) v1(120.31,17.03) v1(120.31,14.49) v1(120.31,11.95) v1(120.31,9.41) v1(120.31,6.87) v1(120.31,4.33) v1(120.31,1.79) v1(120.43,101.48) v1(120.43,99.58) v1(120.43,97.67) v1(120.56,46.49) v1(120.56,30.49) v1(120.81,73.16) v1(120.81,71.26) v1(120.81,69.35) v1(120.81,67.45) v1(120.81,65.54) v1(120.81,63.64) v1(121.07,48.02) v1(121.32,44.84) v1(121.32,42.3) v1(121.32,37.22) v1(121.32,34.68) v1(121.7,62.87) v1(122.21,24.52) v1(122.21,23.38) v1(122.34,101.48) v1(122.34,99.58) v1(122.34,97.67) v1(122.46,103.39) v1(122.72,73.16) v1(122.72,71.26) v1(122.72,69.35) v1(122.72,67.45) v1(122.72,65.54) v1(122.72,63.64) v1(122.85,19.57) v1(122.85,17.03) v1(122.85,14.49) v1(122.85,11.95) v1(122.85,9.41) v1(122.85,6.87) v1(122.85,4.33) v1(122.85,1.79) v1(123.1,46.49) v1(123.61,62.87) v1(123.73,80.91) v1(123.73,79) v1(123.73,76.46) v1(123.73,25.92) v1(123.86,44.84) v1(123.86,42.3) v1(123.86,39.76) v1(123.86,37.22) v1(123.86,34.68) v1(124.24,103.39) v1(124.24,101.48) v1(124.24,99.58) v1(124.24,97.67) v1(124.24,95.77) v1(124.24,83.19) v1(124.37,29.85) v1(124.62,73.16) v1(124.62,71.26) v1(124.62,69.61) v1(124.62,67.45) v1(124.62,65.54) v1(124.62,63.64) v1(124.75,23.38) v1(124.88,24.52) v1(125.39,19.57) v1(125.39,17.03) v1(125.39,14.49) v1(125.39,11.95) v1(125.39,9.41) v1(125.39,6.87) v1(125.39,4.33) v1(125.39,1.79) v1(125.51,62.87) v1(125.64,79) v1(125.64,76.46) v1(125.64,46.49) v1(125.64,28.33) v1(125.77,31.12) v1(126.15,103.39) v1(126.15,101.48) v1(126.15,99.58) v1(126.15,97.67) v1(126.15,95.77) v1(126.4,69.61) v1(126.4,67.45) v1(126.4,44.84) v1(126.4,42.3) v1(126.4,39.76) v1(126.4,37.22) v1(126.4,34.68) v1(126.52,116.98) v1(126.52,115.71) v1(126.52,114.44) v1(126.53,65.54) v1(126.53,63.64) v1(127.29,25.92) v1(127.29,23.38) v1(127.42,80.02) v1(127.42,62.87) v1(127.42,29.6) v1(127.42,24.52) v1(127.54,78.37) v1(127.79,116.98) v1(127.79,115.64) v1(127.79,114.44) v1(127.93,19.57) v1(127.93,17.03) v1(127.93,14.49) v1(127.93,11.95) v1(127.93,9.41) v1(127.93,6.87) v1(127.93,4.33) v1(127.93,1.79) v1(128.05,103.39) v1(128.05,101.48) v1(128.05,99.58) v1(128.05,97.67) v1(128.18,46.49) v1(128.31,67.45) v1(128.31,65.54) v1(128.43,63.64) v1(128.94,44.84) v1(128.94,42.3) v1(128.94,39.76) v1(128.94,37.22) v1(128.94,34.68) v1(129.06,116.98) v1(129.06,115.71) v1(129.06,114.44) v1(129.32,62.87) v1(129.83,23.38) v1(129.96,103.39) v1(129.96,101.48) v1(129.96,99.58) v1(129.96,97.67) v1(130.21,65.54) v1(130.21,63.64) v1(130.34,113.17) v1(130.34,72.91) v1(130.47,19.57) v1(130.47,17.03) v1(130.47,14.49) v1(130.47,11.95) v1(130.47,9.41) v1(130.47,6.87) v1(130.47,4.33) v1(130.47,1.79) v1(130.59,31) v1(130.72,46.49) v1(130.72,28.08) v1(130.97,24.52) v1(131.1,114.69) v1(131.18,89.24) v1(131.18,87.33) v1(131.23,62.87) v1(131.23,48.02) v1(131.35,26.04) v1(131.48,44.84) v1(131.48,42.3) v1(131.48,39.76) v1(131.48,37.22) v1(131.48,34.68) v1(131.74,113.17) v1(131.86,103.39) v1(131.86,101.48) v1(131.86,99.58) v1(131.86,97.67) v1(132.12,65.54) v1(132.12,63.64) v1(132.37,23.38) v1(132.5,126.63) v1(132.5,114.69) v1(132.62,122.44) v1(132.75,72.91) v1(133.01,28.2) v1(133.01,19.57) v1(133.01,17.03) v1(133.01,14.49) v1(133.01,11.95) v1(133.01,9.41) v1(133.01,6.87) v1(133.01,4.33) v1(133.01,1.79) v1(133.08,87.33) v1(133.13,62.87) v1(133.13,31) v1(133.26,71) v1(133.26,69.86) v1(133.77,48.02) v1(133.89,100.59) v1(134.02,65.54) v1(134.02,63.64) v1(134.02,37.22) v1(134.02,34.68) v1(134.15,120.79) v1(134.15,45.86) v1(134.15,42.05) v1(134.4,25.41) v1(134.66,74.18) v1(134.91,126.5) v1(134.91,23.38) v1(134.99,87.33) v1(135.04,62.87) v1(135.16,71) v1(135.16,69.86) v1(135.29,72.78) v1(135.55,118.37) v1(135.55,19.57) v1(135.55,17.03) v1(135.55,14.49) v1(135.55,11.95) v1(135.55,9.41) v1(135.55,6.87) v1(135.55,4.33) v1(135.55,1.79) v1(135.67,102.24) v1(135.67,100.59) v1(135.67,99.2) v1(135.67,98.18) v1(135.93,65.54) v1(135.93,63.64) v1(136.05,75.83) v1(136.18,42.05) v1(136.31,48.02) v1(136.43,119.77) v1(136.43,45.6) v1(136.56,37.22) v1(136.56,34.68) v1(136.89,91.14) v1(136.89,89.24) v1(136.89,87.33) v1(136.94,62.87) v1(137.07,126.76) v1(137.07,118.25) v1(137.07,71) v1(137.07,69.86) v1(137.07,28.33) v1(137.32,31) v1(137.32,25.41) v1(137.45,76.08) v1(137.45,23.38) v1(137.58,120.66) v1(137.58,74.05) v1(137.7,102.24) v1(137.7,100.72) v1(137.83,65.54) v1(137.83,63.64) v1(137.96,76.84) v1(138.09,72.78) v1(138.09,19.57) v1(138.09,17.03) v1(138.09,14.49) v1(138.09,11.95) v1(138.09,9.41) v1(138.09,6.87) v1(138.09,4.33) v1(138.09,1.79) v1(138.21,121.8) v1(138.21,45.48) v1(138.34,42.05) v1(138.34,38.62) v1(138.72,83.32) v1(138.85,101.48) v1(138.85,64.53) v1(138.85,48.02) v1(138.85,46.75) v1(138.97,71) v1(138.97,69.86) v1(139.1,34.68) v1(139.23,90.81) v1(139.6,150) v1(139.6,147.46) v1(139.6,144.67) v1(139.61,142) v1(139.61,30.74) v1(139.74,102.24) v1(139.74,100.72) v1(139.74,65.54) v1(139.74,28.33) v1(139.86,151.01) v1(139.99,23.38) v1(140.12,25.28) v1(140.24,42.05) v1(140.37,38.11) v1(140.5,143.01) v1(140.63,19.57) v1(140.63,17.03) v1(140.63,14.49) v1(140.63,11.95) v1(140.63,9.41) v1(140.63,6.87) v1(140.63,4.33) v1(140.63,1.79) v1(140.75,64.53) v1(140.88,71) v1(140.88,69.86) v1(141,151.14) v1(141.39,48.02) v1(141.39,46.75) v1(141.63,150.13) v1(141.63,147.59) v1(141.64,144.79) v1(141.64,120.15) v1(141.64,118.37) v1(141.64,102.12) v1(141.64,100.21) v1(141.64,98.31) v1(141.64,65.54) v1(141.64,34.68) v1(141.77,82.94) v1(141.9,81.29) v1(141.9,79.38) v1(141.9,77.48) v1(142.28,42.05) v1(142.28,38.24) v1(142.4,45.35) v1(142.53,135.65) v1(142.53,23.38) v1(142.66,64.53) v1(142.77,151.14) v1(142.78,142) v1(142.78,73.67) v1(142.78,71) v1(142.78,69.86) v1(143.04,107.07) v1(143.17,145.81) v1(143.17,137.17) v1(143.17,19.57) v1(143.17,17.03) v1(143.17,14.49) v1(143.17,11.95) v1(143.17,9.41) v1(143.17,6.87) v1(143.17,4.33) v1(143.17,1.79) v1(143.29,120.15) v1(143.29,118.37) v1(143.29,104.02) v1(143.29,102.12) v1(143.41,150.13) v1(143.41,147.59) v1(143.42,32.9) v1(143.42,31) v1(143.55,65.54) v1(143.55,28.84) v1(143.55,25.28) v1(143.67,143.01) v1(143.93,48.02) v1(143.93,46.75) v1(144.56,64.53) v1(144.68,136.66) v1(144.69,121.93) v1(144.69,71) v1(144.69,69.86) v1(144.69,37.98) v1(144.82,125.74) v1(144.82,107.83) v1(144.94,27.19) v1(145.03,128.81) v1(145.07,23.38) v1(145.45,120.15) v1(145.45,118.37) v1(145.45,65.54) v1(145.45,35.82) v1(145.58,73.67) v1(145.58,33.92) v1(145.7,130.97) v1(145.71,19.57) v1(145.71,17.03) v1(145.71,14.49) v1(145.71,11.95) v1(145.71,9.41) v1(145.71,6.87) v1(145.71,4.33) v1(145.71,1.79) v1(145.95,135.9) v1(145.96,31.25) v1(145.96,28.84) v1(146.09,42.17) v1(146.34,127.26) v1(146.34,72.15) v1(146.47,48.02) v1(146.47,46.75) v1(146.59,129.93) v1(146.71,133.87) v1(146.72,107.83) v1(146.71,64.53) v1(147.23,120.15) v1(147.23,118.37) v1(147.48,124.47) v1(147.48,45.35) v1(147.61,37.98) v1(147.61,35.44) v1(147.61,25.28) v1(147.61,23.38) v1(147.61,10.3) v1(147.99,128.79) v1(147.99,73.67) v1(148.12,72.02) v1(148.12,70.88) v1(148.12,42.05) v1(148.25,19.57) v1(148.25,17.03) v1(148.25,6.87) v1(148.25,4.33) v1(148.25,1.79) v1(148.49,133.87) v1(148.49,131.84) v1(148.49,62.88) v1(148.63,107.83) v1(148.75,126.12) v1(148.75,12.2) v1(148.88,69.48) v1(149.01,48.02) v1(149.01,46.75) v1(149.13,45.73) v1(149.38,138.95) v1(149.38,137.17) v1(149.52,120.15) v1(149.52,118.37) v1(149.52,82.69) v1(149.64,33.66) v1(149.77,28.71) v1(150.01,130.82) v1(150.02,81.8) v1(150.02,72.02) v1(150.02,70.88) v1(150.02,69.35) v1(150.15,124.98) v1(150.15,44.71) v1(150.15,30.87) v1(150.15,23.38) v1(150.27,62.88) v1(150.28,127.52) v1(150.4,41.92) v1(150.52,138.95) v1(150.52,137.17) v1(150.53,131.96) v1(150.53,107.83) v1(150.53,68.08) v1(150.53,38.11) v1(150.53,35.82) v1(150.79,19.57) v1(150.79,17.03) v1(150.79,6.87) v1(150.79,4.33) v1(150.79,1.79) v1(150.91,73.67) v1(151.29,120.41) v1(151.55,118.37) v1(151.55,48.02) v1(151.55,46.75) v1(151.55,45.73) v1(151.66,151.14) v1(151.8,14.23) v1(151.93,72.02) v1(151.93,70.88) v1(151.93,69.35) v1(151.93,68.21) v1(152.05,131.84) v1(152.05,62.88) v1(152.17,124.98) v1(152.18,130.69) v1(152.18,127.39) v1(152.3,150.38) v1(152.3,148.35) v1(152.3,142.51) v1(152.3,140.73) v1(152.3,138.95) v1(152.3,137.17) v1(152.3,135.39) v1(152.3,133.87) v1(152.31,28.58) v1(152.44,30.87) v1(152.56,73.67) v1(152.56,35.82) v1(152.56,33.54) v1(152.69,42.68) v1(152.94,40.14) v1(153.07,107.96) v1(153.19,143.52) v1(153.33,131.96) v1(153.33,19.57) v1(153.33,17.03) v1(153.33,6.87) v1(153.33,4.33) v1(153.33,1.79) v1(153.44,151.14) v1(153.45,8.26) v1(153.58,10.17) v1(153.83,73.67) v1(153.83,72.4) v1(153.83,25.54) v1(153.96,125.1) v1(153.95,118.38) v1(153.96,67.57) v1(153.95,62.88) v1(153.96,12.46) v1(154.08,150.38) v1(154.08,148.35) v1(154.08,144.54) v1(154.08,142.51) v1(154.08,140.73) v1(154.08,138.95) v1(154.08,137.17) v1(154.08,135.39) v1(154.08,133.62) v1(154.09,107.2) v1(154.09,48.02) v1(154.09,46.75) v1(154.09,45.73) v1(154.21,120.28) v1(154.21,82.56) v1(154.21,80.91) v1(154.21,43.7) v1(154.84,143.65) v1(154.84,131.84) v1(154.85,9.66) v1(155.1,130.82) v1(155.1,84.97) v1(155.1,73.67) v1(155.1,72.4) v1(155.1,38.11) v1(155.22,151.14) v1(155.23,81.16) v1(155.35,133.62) v1(155.36,40.14) v1(155.36,34.43) v1(155.74,147.84) v1(155.74,142.12) v1(155.74,67.45) v1(155.86,150.38) v1(155.86,144.54) v1(155.86,140.73) v1(155.86,138.95) v1(155.86,135.39) v1(155.86,62.88) v1(155.87,22.11) v1(155.87,19.57) v1(155.87,6.87) v1(155.87,4.33) v1(155.87,1.79) v1(156.12,78.5) v1(156.24,118.38) v1(156.25,81.29) v1(156.36,131.84) v1(156.37,73.67) v1(156.37,72.4) v1(156.63,120.66) v1(156.63,76.34) v1(156.63,75.19) v1(156.63,48.02) v1(156.63,46.75) v1(156.63,45.73) v1(156.63,43.19) v1(156.75,87.11) v1(156.87,139.71) v1(156.88,32.65) v1(156.88,13.73) v1(157.14,129.93) v1(157.14,78.37) v1(157.38,133.62) v1(157.39,29.98) v1(157.39,24.14) v1(157.52,131.07) v1(157.52,62.87) v1(157.64,76.34) v1(157.64,73.67) v1(157.64,72.4) v1(157.64,38.11) v1(157.77,121.68) v1(157.77,35.57) v1(157.89,138.95) v1(157.89,137.17) v1(157.89,135.39) v1(157.9,75.19) v1(158.02,78.37) v1(158.02,67.57) v1(158.14,129.37) v1(158.28,79.26) v1(158.41,140.34) v1(158.4,132.6) v1(158.4,130.06) v1(158.41,9.41) v1(158.41,6.87) v1(158.41,4.33) v1(158.41,1.79) v1(158.66,17.03) v1(158.91,120.28) v1(158.91,77.48) v1(158.91,72.4) v1(158.91,27.06) v1(158.91,24.52) v1(158.91,21.98) v1(158.91,19.44) v1(159.16,141.11) v1(159.17,48.02) v1(159.17,46.75) v1(159.17,45.73) v1(159.17,43.19) v1(159.17,40.65) v1(159.17,38.11) v1(159.17,35.57) v1(159.28,139.84) v1(159.29,74.69) v1(159.42,78.11) v1(159.42,62.87) v1(159.54,139.08) v1(159.67,138.06) v1(159.67,137.17) v1(159.67,136.16) v1(159.67,134) v1(159.68,134.88) v1(159.68,132.85) v1(159.68,128.91) v1(159.68,68.59) v1(159.93,76.46) v1(160.31,73.67) v1(160.44,77.1) v1(160.56,120.28) v1(160.55,118.63) v1(160.69,75.57) v1(160.95,47.51) v1(160.95,11.95) v1(160.95,9.41) v1(160.95,6.87) v1(160.95,4.33) v1(160.95,1.79) v1(161.07,127.64) v1(161.2,44.97) v1(161.33,76.21) v1(161.33,62.87) v1(161.33,22.23) v1(161.7,126.76) v1(161.71,43.19) v1(161.71,40.65) v1(161.71,38.11) v1(161.71,35.57) v1(161.71,25.66) v1(161.96,68.46) v1(162.22,75.19) v1(162.47,120.28) v1(162.46,118.63) v1(163.1,69.61) v1(163.23,62.87) v1(163.36,125.23) v1(163.49,47.51) v1(163.49,44.97) v1(163.49,42.68) v1(163.49,19.57) v1(163.49,17.03) v1(163.49,14.49) v1(163.49,11.95) v1(163.49,9.41) v1(163.49,6.87) v1(163.49,4.33) v1(163.49,1.79) v1(163.87,124.09) v1(163.87,122.18) v1(163.87,68.59) v1(164.12,120.28) v1(164.12,118.63) v1(164.25,40.65) v1(164.25,38.11) v1(164.25,35.57) v1(164.25,25.41) v1(164.25,22.87) v1(165.14,62.87) v1(165.26,67.83) v1(165.26,40.9) v1(165.52,82.69) v1(165.64,70.24) v1(165.77,122.18) v1(165.77,120.28) v1(165.77,118.63) v1(166.03,139.58) v1(166.03,138.57) v1(166.03,137.3) v1(166.03,136.03) v1(166.03,134.88) v1(166.03,47.51) v1(166.03,44.97) v1(166.03,42.43) v1(166.03,11.95) v1(166.03,9.41) v1(166.03,6.87) v1(166.03,4.33) v1(166.03,1.79) v1(166.15,133.87) v1(166.66,82.56) v1(166.66,69.22) v1(166.79,81.42) v1(166.79,38.11) v1(166.79,35.57) v1(166.79,25.41) v1(166.79,22.87) v1(166.91,17.28) v1(167.29,132.85) v1(167.3,120.28) v1(167.3,118.63) v1(167.42,67.95) v1(167.55,70.37) v1(168.05,62.88) v1(168.18,37.98) v1(168.3,131.84) v1(168.57,47.51) v1(168.57,44.97) v1(168.57,42.43) v1(168.57,39.89) v1(168.57,11.95) v1(168.57,4.33) v1(168.57,1.79) v1(168.95,69.22) v1(168.95,18.17) v1(169.19,130.95) v1(169.2,120.28) v1(169.2,118.63) v1(169.33,35.57) v1(169.33,33.03) v1(169.33,30.49) v1(169.33,27.95) v1(169.33,25.41) v1(169.33,22.87) v1(169.84,140.98) v1(169.83,62.88) v1(169.96,70.37) v1(169.96,19.57) v1(170.22,67.07) v1(170.22,65.92) v1(170.33,129.81) v1(170.6,35.57) v1(170.98,130.69) v1(171.11,140.47) v1(171.11,120.28) v1(171.11,118.63) v1(171.11,47.51) v1(171.11,42.43) v1(171.11,39.89) v1(171.11,37.35) v1(171.11,17.03) v1(171.11,14.49) v1(171.11,11.95) v1(171.11,9.41) v1(171.11,4.33) v1(171.11,1.79) v1(171.6,129.43) v1(171.61,70.37) v1(171.6,62.88) v1(171.74,32.9) v1(171.74,30.36) v1(171.74,27.82) v1(171.74,25.28) v1(171.74,22.74) v1(172.11,139.08) v1(172.25,130.69) v1(172.76,33.41) v1(172.87,129.43) v1(173,151.14) v1(173.01,120.28) v1(173.01,118.63) v1(173.14,147.2) v1(173.14,140.47) v1(173.25,143.78) v1(173.26,142) v1(173.26,32.39) v1(173.26,29.85) v1(173.26,27.31) v1(173.26,24.77) v1(173.26,22.23) v1(173.26,19.69) v1(173.38,139.03) v1(173.38,62.88) v1(173.65,130.69) v1(173.65,47.51) v1(173.65,44.97) v1(173.65,42.43) v1(173.65,39.89) v1(173.65,37.35) v1(173.65,34.81) v1(173.65,17.03) v1(173.65,14.49) v1(173.65,11.95) v1(173.65,9.41) v1(173.65,6.87) v1(173.65,4.33) v1(173.65,1.79) v1(173.86,150.31) v1(174.15,129.42) v1(174.28,148.35) v1(174.66,143.77) v1(174.66,141.87) v1(174.66,139.96) v1(174.66,138.44) v1(174.78,151.14) v1(174.92,146.95) v1(174.92,130.69) v1(174.92,120.28) v1(174.92,118.63) v1(175.17,135.01) v1(175.64,150.31) v1(175.8,129.42) v1(175.89,148.41) v1(175.93,62.87) v1(176.06,65.8) v1(176.19,47.51) v1(176.19,39.89) v1(176.19,37.35) v1(176.19,34.81) v1(176.19,32.27) v1(176.19,29.73) v1(176.19,27.19) v1(176.19,24.65) v1(176.19,22.11) v1(176.19,19.57) v1(176.19,17.03) v1(176.19,14.49) v1(176.19,11.95) v1(176.19,9.41) v1(176.56,151.14) v1(176.57,142.5) v1(176.56,139.59) v1(176.57,82.18) v1(176.69,147.08) v1(176.69,130.69) v1(176.81,143.65) v1(176.82,136.79) v1(176.82,135.01) v1(176.82,120.28) v1(176.82,118.63) v1(177.42,150.31) v1(177.42,144.47) v1(177.45,142.76) v1(177.46,65.8) v1(177.71,129.42) v1(177.71,82.18) v1(177.84,148.35) v1(178.22,143.65) v1(178.22,81.29) v1(178.33,151.14) v1(178.35,136.79) v1(178.34,135.01) v1(178.34,130.69) v1(178.47,62.87) v1(178.72,139.2) v1(178.73,120.28) v1(178.73,37.35) v1(178.73,34.81) v1(178.73,32.27) v1(178.73,29.73) v1(178.73,27.19) v1(178.73,24.65) v1(178.73,22.11) v1(178.73,19.57) v1(178.73,17.03) v1(178.73,14.49) v1(178.73,11.95) v1(178.73,9.41) v1(179.2,150.31) v1(179.2,146.5) v1(179.2,144.47) v1(179.23,118.63) v1(179.49,65.8) v1(179.6,147.84) v1(179.61,131.2) v1(179.61,129.42) v1(179.87,136.79) v1(179.86,135.01) v1(180.11,151.14) v1(180.5,141.49) v1(180.63,139.96) v1(180.63,120.28) v1(180.97,150.31) v1(180.97,148.28) v1(180.97,146.5) v1(180.97,144.47) v1(181.14,142.25) v1(181.27,62.87) v1(181.27,37.35) v1(181.27,34.81) v1(181.27,32.27) v1(181.27,29.73) v1(181.27,27.19) v1(181.27,24.65) v1(181.27,22.11) v1(181.27,19.57) v1(181.27,17.03) v1(181.27,14.49) v1(181.27,11.95) v1(181.27,9.41) v1(181.39,136.79) v1(181.38,135.01) v1(181.39,118.63) v1(181.52,131.2) v1(181.52,129.42) v1(181.65,141.23) v1(181.89,151.14) v1(181.9,65.8) v1(182.02,116.34) v1(182.53,139.71) v1(182.54,120.28) v1(182.66,100.47) v1(182.75,150.31) v1(182.75,144.47) v1(182.79,118.63) v1(183.17,136.79) v1(183.17,135.01) v1(183.27,99.65) v1(183.27,97.75) v1(183.27,95.84) v1(183.27,93.94) v1(183.27,92.03) v1(183.27,90.13) v1(183.27,88.22) v1(183.27,86.32) v1(183.3,84.97) v1(183.41,131.2) v1(183.42,129.42) v1(183.55,141.74) v1(183.54,114.82) v1(183.67,151.14) v1(183.81,39.89) v1(183.81,37.35) v1(183.81,34.81) v1(183.81,32.27) v1(183.81,29.73) v1(183.81,27.19) v1(183.81,24.65) v1(183.81,22.11) v1(183.81,19.57) v1(183.81,17.03) v1(183.81,14.49) v1(183.81,11.95) v1(183.81,9.41) v1(184.06,117.36) v1(184.18,62.88) v1(184.56,150.38) v1(184.56,148.35) v1(184.56,146.57) v1(184.56,144.54) v1(184.56,141.49) v1(184.56,139.71) v1(184.56,118.12) v1(184.57,65.8) v1(184.69,84.97) v1(184.69,83.7) v1(184.69,82.43) v1(184.81,113.55) v1(184.78,93.76) v1(184.79,92.03) v1(184.79,90.13) v1(184.94,131.2) v1(184.9,95.66) v1(185.03,97.95) v1(185.17,99.65) v1(185.17,88.22) v1(185.17,86.32) v1(185.33,129.42) v1(185.33,116.09) v1(185.33,68.21) v1(185.33,66.68) v1(185.45,151.14) v1(185.57,117.11) v1(185.83,139.2) v1(185.83,138.19) v1(185.83,136.92) v1(185.84,135.65) v1(185.96,97.29) v1(185.96,95.39) v1(185.96,93.48) v1(185.96,91.58) v1(185.96,89.67) v1(185.96,84.97) v1(185.96,83.7) v1(185.96,82.43) v1(186.08,112.28) v1(186.08,62.88) v1(186.22,150.38) v1(186.22,65.8) v1(186.34,116.34) v1(186.56,148.28) v1(186.56,146.5) v1(186.56,144.47) v1(186.59,142.76) v1(186.85,114.56) v1(186.84,111.52) v1(187.11,129.17) v1(187.08,99.65) v1(187.08,88.22) v1(187.08,86.32) v1(187.22,151.14) v1(187.23,83.7) v1(187.23,82.43) v1(187.23,68.21) v1(187.23,66.68) v1(187.35,115.33) v1(187.32,98.33) v1(187.62,84.97) v1(187.74,139.2) v1(187.74,138.19) v1(187.87,137.17) v1(187.87,97.29) v1(187.87,95.39) v1(187.87,93.48) v1(187.87,91.58) v1(187.87,89.67) v1(188,150.38) v1(188,136.03) v1(188,128.15) v1(188,113.42) v1(187.99,62.88) v1(188.12,65.8) v1(188.34,144.47) v1(188.37,142.76) v1(188.38,70.49) v1(188.38,69.22) v1(188.62,114.06) v1(188.88,112.53) v1(188.88,109.99) v1(188.88,108.47) v1(189,151.14) v1(189.01,140.85) v1(189.01,138.95) v1(189.01,137.3) v1(188.98,99.65) v1(188.98,88.22) v1(188.98,86.32) v1(189.01,83.96) v1(189.14,149.49) v1(189.14,148.09) v1(189.14,146.57) v1(189.13,144.03) v1(189.11,98.26) v1(189.14,68.21) v1(189.14,66.68) v1(189.08,49.93) v1(189.21,39.13) v1(189.21,35.32) v1(189.21,31.77) v1(189.21,27.96) v1(189.21,23.89) v1(189.21,21.99) v1(189.21,8.4) v1(189.33,52.34) v1(189.52,126.63) v1(189.65,85.61) v1(189.65,69.22) v1(189.59,58.82) v1(189.77,150.38) v1(189.77,97.29) v1(189.77,95.39) v1(189.77,93.48) v1(189.77,91.58) v1(189.77,89.67) v1(189.89,62.88) v1(190.16,71.24) v1(190.16,65.8) v1(190.28,143.65) v1(190.28,141.74) v1(190.28,139.84) v1(190.28,137.93) v1(190.28,136.03) v1(190.28,70.24) v1(190.41,125.74) v1(190.41,72.27) v1(190.48,47.01) v1(190.6,43.2) v1(190.73,20.21) v1(190.73,12.59) v1(190.78,151.14) v1(190.89,99.65) v1(190.89,88.22) v1(190.88,69.46) v1(191.04,148.09) v1(191.04,146.57) v1(191.01,98.26) v1(191.04,68.21) v1(191.04,66.68) v1(191,26.19) v1(191,22.38) v1(191,18.57) v1(191,14.76) v1(191,10.95) v1(191.17,149.49) v1(191.16,86.12) v1(191.08,49.05) v1(191.08,45.24) v1(191.08,41.43) v1(191.08,37.62) v1(191.08,33.81) v1(191.08,30) v1(191.43,72.78) v1(191.55,150.38) v1(191.55,124.6) v1(191.65,74.38) v1(191.68,97.29) v1(191.68,95.39) v1(191.68,93.48) v1(191.68,91.58) v1(191.68,89.67) v1(191.68,78.5) v1(191.68,77.48) v1(191.68,76.59) v1(191.68,75.32) v1(191.87,69.4) v1(191.8,62.88) v1(191.93,65.8) v1(192.44,72.78) v1(192.56,151.14) v1(192.57,123.58) v1(192.95,68.21) v1(192.95,66.68) v1(193.07,146.57) v1(193.08,149.49) v1(193.08,148.09) v1(193.08,97.29) v1(193.08,69.61) v1(193.33,150.38) v1(193.46,131.45) v1(193.43,88.22) v1(193.43,86.95) v1(193.45,85.61) v1(193.58,132.6) v1(193.58,122.56) v1(193.58,95.39) v1(193.58,93.48) v1(193.58,91.58) v1(193.58,89.67) v1(193.71,78.5) v1(193.7,62.88) v1(193.84,71.89) v1(193.84,70.62) v1(194.09,146.06) v1(194.34,151.14) v1(194.35,139.71) v1(194.35,138.19) v1(194.35,77.99) v1(194.35,72.65) v1(194.35,69.22) v1(194.85,68.21) v1(194.85,66.68) v1(194.89,49.05) v1(194.89,45.24) v1(194.89,41.43) v1(194.89,37.62) v1(194.89,33.81) v1(194.89,30) v1(194.89,26.19) v1(194.89,22.38) v1(194.89,18.57) v1(194.89,14.76) v1(194.89,10.95) v1(194.98,121.17) v1(195.01,100.83) v1(194.98,72.15) v1(194.98,71.13) v1(194.98,70.24) v1(195.11,150.38) v1(195.24,87.13) v1(195.24,62.87) v1(195.36,137.42) v1(195.33,95.59) v1(195.33,93.94) v1(195.33,92.03) v1(195.33,90.13) v1(195.33,88.22) v1(195.49,76.97) v1(195.49,76.08) v1(195.62,134.5) v1(195.63,69.71) v1(195.74,132.47) v1(195.74,131.2) v1(195.74,129.68) v1(195.68,100.83) v1(195.74,75.19) v1(195.87,73.42) v1(196.11,151.14) v1(196.12,144.03) v1(196.25,141.36) v1(196.25,119.9) v1(196.25,95.64) v1(196.35,100.83) v1(196.63,74.3) v1(196.76,69.35) v1(196.76,68.21) v1(196.76,66.68) v1(196.83,1.16) v1(196.89,150.38) v1(196.89,75.45) v1(197.14,134.5) v1(197.14,119.01) v1(197.27,132.47) v1(197.27,130.06) v1(197.26,91.83) v1(197.24,90.13) v1(197.24,88.22) v1(197.39,137.55) v1(197.39,131.2) v1(197.51,148.35) v1(197.52,141.74) v1(197.5,107.32) v1(197.65,127.64) v1(197.61,73.09) v1(197.89,151.14) v1(198.03,140.34) v1(198.03,74.3) v1(198.16,118.12) v1(198.25,69.33) v1(198.28,138.95) v1(198.66,150.38) v1(198.66,68.21) v1(198.66,66.68) v1(198.7,56.67) v1(198.7,52.86) v1(198.7,49.05) v1(198.7,45.24) v1(198.7,33.81) v1(198.77,26.26) v1(198.7,22.38) v1(198.7,14.76) v1(198.7,10.95) v1(198.7,7.14) v1(198.7,3.33) v1(198.79,126.5) v1(198.86,117.11) v1(198.86,116.09) v1(198.86,114.82) v1(198.86,113.04) v1(198.86,111.52) v1(198.86,110.07) v1(198.79,109.1) v1(198.92,135.9) v1(198.92,134.5) v1(198.95,72.92) v1(199.17,142.25) v1(199.17,140.98) v1(199.17,69.48) v1(199.27,70.32) v1(199.29,148.35) v1(199.29,146.57) v1(199.29,144.03) v1(199.3,137.17) v1(199.3,71.76) v1(199.67,151.14) v1(199.68,139.58) v1(200.32,124.85) v1(200.44,150.38) v1(200.44,127.64) v1(200.57,70.11) v1(200.57,68.21) v1(200.57,66.68) v1(200.82,142.25) v1(200.82,140.98) v1(201.07,148.35) v1(201.1,146.64) v1(201.1,144.06) v1(201.08,137.8) v1(201.2,136.03) v1(201.2,134.25) v1(201.2,132.6) v1(201.2,129.8) v1(201.45,151.14) v1(201.59,139.71) v1(201.71,69.22) v1(201.84,138.31) v1(201.78,1.03) v1(201.97,123.33) v1(202.22,150.38) v1(202.22,128.28) v1(202.47,142.25) v1(202.47,140.98) v1(202.51,56.67) v1(202.51,52.86) v1(202.51,49.05) v1(202.51,45.24) v1(202.51,41.43) v1(202.51,37.62) v1(202.51,33.81) v1(202.51,30) v1(202.51,26.19) v1(202.51,22.38) v1(202.51,18.57) v1(202.51,14.76) v1(202.51,10.95) v1(202.51,7.14) v1(202.51,3.33) v1(202.6,131.45) v1(202.85,148.35) v1(202.86,136.66) v1(202.86,135.39) v1(202.86,134.12) v1(202.98,137.68) v1(203.1,146.57) v1(203.1,144.03) v1(203.11,132.98) v1(203.23,151.14) v1(203.49,121.8) v1(203.74,130.57) v1(203.74,68.21) v1(203.74,66.81) v1(203.87,132.34) v1(203.87,128.15) v1(203.87,125.49) v1(203.87,123.83) v1(204,150.38) v1(204.25,137.68) v1(204.51,142.25) v1(204.51,140.98) v1(204.62,148.22) v1(204.7,1.16) v1(204.88,146.57) v1(204.88,144.03) v1(205,151.14) v1(205.01,132.34) v1(205.14,120.28) v1(205.13,62.88) v1(205.4,136.15) v1(205.4,135.01) v1(205.4,134.12) v1(205.4,132.98) v1(205.4,127.52) v1(205.52,139.84) v1(205.52,138.69) v1(205.52,137.42) v1(205.52,130.06) v1(205.52,116.6) v1(205.65,125.36) v1(205.65,123.83) v1(205.64,84.59) v1(205.78,150.38) v1(205.78,141.61) v1(206.03,72.02) v1(206.16,131.33) v1(206.32,56.67) v1(206.32,52.86) v1(206.32,49.05) v1(206.32,45.24) v1(206.32,41.43) v1(206.32,37.62) v1(206.32,33.81) v1(206.32,30) v1(206.32,26.19) v1(206.32,22.38) v1(206.32,18.57) v1(206.32,14.76) v1(206.32,10.95) v1(206.32,7.14) v1(206.32,3.33) v1(206.4,146.57) v1(206.4,144.03) v1(206.41,132.98) v1(206.54,126.5) v1(206.66,148.35) v1(206.67,140.6) v1(206.67,119.26) v1(206.67,83.83) v1(206.78,151.14) v1(206.92,138.69) v1(206.92,137.3) v1(206.92,117.23) v1(207.04,62.88) v1(207.17,131.96) v1(207.17,129.93) v1(207.17,120.41) v1(207.3,123.83) v1(207.3,72.02) v1(207.3,70.75) v1(207.55,150.38) v1(207.55,125.36) v1(207.55,112.91) v1(207.55,82.94) v1(207.62,1.16) v1(207.68,118.25) v1(207.81,135.9) v1(207.81,133.23) v1(207.94,131.45) v1(207.94,86.5) v1(208.06,134.88) v1(208.06,126.5) v1(208.19,146.06) v1(208.18,144.03) v1(208.43,148.35) v1(208.44,138.82) v1(208.56,151.14) v1(208.57,120.28) v1(208.7,140.73) v1(208.7,72.02) v1(208.7,70.75) v1(208.7,69.35) v1(208.82,137.04) v1(208.95,133.61) v1(208.95,117.36) v1(208.94,62.88) v1(209.08,132.6) v1(209.08,131.45) v1(209.08,81.04) v1(209.21,143.14) v1(209.21,134.63) v1(209.33,150.38) v1(209.33,110.63) v1(209.33,86.5) v1(209.33,84.97) v1(209.46,137.68) v1(209.46,112.91) v1(209.59,130.06) v1(209.97,120.28) v1(209.97,80.15) v1(210.09,123.2) v1(210.09,118.75) v1(210.13,56.67) v1(210.13,52.86) v1(210.13,45.24) v1(210.13,41.43) v1(210.13,37.62) v1(210.13,33.81) v1(210.13,30) v1(210.13,26.19) v1(210.13,22.38) v1(210.13,18.57) v1(210.13,14.76) v1(210.13,10.95) v1(210.13,7.14) v1(210.13,3.33) v1(210.16,1.16) v1(210.21,144.03) v1(210.21,142.51) v1(210.34,151.14) v1(210.48,131.45) v1(210.48,112.02) v1(210.6,115.96) v1(210.86,137.55) v1(210.86,86.5) v1(210.86,84.97) v1(210.86,79.38) v1(210.85,62.88) v1(211.11,150.38) v1(211.11,134.5) v1(211.11,124.6) v1(211.36,130.18) v1(211.36,78.88) v1(211.49,140.85) v1(211.62,144.03) v1(211.62,117.23) v1(211.74,148.35) v1(211.74,142.51) v1(211.75,132.6) v1(211.75,131.45) v1(211.75,128.66) v1(211.75,113.29) v1(211.75,110.63) v1(211.87,138.57) v1(212.07,1.92) v1(212.12,151.14) v1(212.13,140.22) v1(212.13,137.04) v1(212.13,135.9) v1(212.13,86.5) v1(212.12,84.89) v1(212.38,134.5) v1(212.51,127.14) v1(212.51,125.61) v1(212.51,124.09) v1(212.75,62.88) v1(212.89,150.38) v1(212.89,129.3) v1(213.02,132.6) v1(213.02,131.45) v1(212.98,85.74) v1(213.08,58.69) v1(213.27,112.66) v1(213.27,70.37) v1(213.4,144.03) v1(213.4,142.38) v1(213.4,140.73) v1(213.4,139.46) v1(213.4,138.06) v1(213.4,137.04) v1(213.4,135.9) v1(213.51,148.35) v1(213.51,146.57) v1(213.52,117.23) v1(213.65,68.84) v1(213.82,85.2) v1(213.89,151.14) v1(213.9,128.53) v1(213.94,56.67) v1(213.94,52.86) v1(213.94,41.43) v1(213.94,37.62) v1(213.94,33.81) v1(213.94,30) v1(213.94,26.19) v1(213.94,22.38) v1(213.94,18.57) v1(213.94,14.76) v1(213.96,7.09) v1(213.94,3.33) v1(214.03,127.14) v1(214.03,125.61) v1(214.03,124.09) v1(214.22,1.03) v1(214.29,134.5) v1(214.29,131.2) v1(214.41,132.6) v1(214.41,129.93) v1(214.54,122.56) v1(214.54,120.98) v1(214.67,150.38) v1(214.67,140.98) v1(214.67,139.58) v1(214.67,70.37) v1(214.66,62.88) v1(214.79,138.19) v1(214.79,136.79) v1(214.92,96.91) v1(215.01,119.42) v1(215.05,116.09) v1(215.05,113.04) v1(215.24,58.44) v1(215.29,148.35) v1(215.29,146.57) v1(215.32,144.06) v1(215.32,142.32) v1(215.3,124.6) v1(215.43,135.01) v1(215.43,120.53) v1(215.67,151.14) v1(215.81,139.58) v1(215.94,68.84) v1(216.06,140.98) v1(216.06,138.19) v1(216.06,131.33) v1(216.19,133.61) v1(216.44,150.38) v1(216.44,117.74) v1(216.56,62.88) v1(216.62,120.74) v1(216.7,119.39) v1(216.7,115.33) v1(216.69,74.69) v1(216.83,124.6) v1(216.83,98.82) v1(216.83,96.91) v1(216.83,73.03) v1(216.95,137.68) v1(216.95,136.92) v1(216.95,134.63) v1(216.92,57.45) v1(216.93,52.8) v1(217.07,148.35) v1(217.07,146.57) v1(217.21,132.22) v1(217.32,144.03) v1(217.32,142.25) v1(217.33,129.42) v1(217.45,151.14) v1(217.46,109.86) v1(217.75,41.43) v1(217.75,37.62) v1(217.75,33.81) v1(217.75,30) v1(217.75,26.19) v1(217.75,22.38) v1(217.75,18.57) v1(217.75,14.76) v1(217.77,7.09) v1(217.75,3.33) v1(217.84,130.95) v1(217.84,118.88) v1(218.1,116.6) v1(218.22,150.38) v1(218.22,137.68) v1(218.22,136.92) v1(218.22,125.87) v1(218.22,124.34) v1(218.22,114.31) v1(218.22,112.66) v1(218.22,74.69) v1(218.22,73.54) v1(218.47,62.88) v1(218.42,58.82) v1(218.59,134.63) v1(218.6,110.75) v1(218.73,140.98) v1(218.73,128.53) v1(218.73,100.72) v1(218.73,98.82) v1(218.73,96.91) v1(218.85,148.35) v1(218.85,146.57) v1(219.05,1.16) v1(219.1,144.03) v1(219.1,142.25) v1(219.1,89.17) v1(219.1,87.26) v1(219.1,85.36) v1(219.1,83.45) v1(219.1,81.55) v1(219.1,79.64) v1(219.1,77.86) v1(219.23,151.14) v1(219.24,138.31) v1(219.24,137.17) v1(219.24,132.22) v1(219.24,115.33) v1(219.49,139.58) v1(219.49,117.61) v1(219.49,109.86) v1(219.62,74.69) v1(219.62,73.54) v1(219.75,111.52) v1(220,150.38) v1(220,130.31) v1(220.13,128.66) v1(220.13,126.88) v1(220.13,125.1) v1(220.13,123.2) v1(220.13,112.66) v1(220.25,136.15) v1(220.37,62.88) v1(220.38,140.98) v1(220.38,139.58) v1(220.38,138.31) v1(220.38,137.17) v1(220.38,118.63) v1(220.38,110.25) v1(220.63,148.35) v1(220.65,146.64) v1(220.63,144.03) v1(220.63,142.25) v1(220.64,100.72) v1(220.64,98.82) v1(220.64,96.91) v1(221.01,151.14) v1(221.01,89.17) v1(221.01,87.26) v1(221.01,85.36) v1(221.01,83.45) v1(221.01,81.55) v1(221.01,79.64) v1(221.01,77.86) v1(221.4,131.33) v1(221.4,115.33) v1(221.4,111.13) v1(221.4,73.54) v1(221.43,43.84) v1(221.52,132.6) v1(221.56,41.43) v1(221.56,37.62) v1(221.56,33.81) v1(221.56,30) v1(221.56,26.19) v1(221.56,22.38) v1(221.56,18.57) v1(221.56,14.76) v1(221.56,3.33) v1(221.65,140.98) v1(221.65,137.68) v1(221.58,7.09) v1(221.78,150.38) v1(221.78,112.79) v1(221.89,52.17) v1(222.03,136.53) v1(222.03,128.66) v1(222.03,125.1) v1(222.03,123.2) v1(222.03,121.04) v1(222.03,119.14) v1(222.03,117.23) v1(222.16,139.46) v1(222.16,126.88) v1(222.28,62.88) v1(222.4,148.35) v1(222.4,144.03) v1(222.4,142.25) v1(222.54,138.31) v1(222.54,130.31) v1(222.54,100.72) v1(222.54,98.82) v1(222.54,96.91) v1(222.78,151.14) v1(222.79,112.66) v1(222.92,140.98) v1(222.92,131.33) v1(222.91,89.17) v1(222.91,87.26) v1(222.91,85.36) v1(222.91,83.45) v1(222.91,81.55) v1(222.91,79.64) v1(222.91,77.86) v1(223.05,136.92) v1(223.18,73.54) v1(223.24,1.29) v1(223.43,119.14) v1(223.56,150.38) v1(223.56,137.68) v1(223.56,122.06) v1(223.81,129.3) v1(223.94,124.34) v1(224.19,130.06) v1(224.18,62.88) v1(224.32,132.09) v1(224.32,125.61) v1(224.32,116.85) v1(224.44,144.03) v1(224.44,142.25) v1(224.45,100.72) v1(224.45,98.82) v1(224.45,96.91) v1(224.43,52.17) v1(224.56,151.14) v1(224.64,58.82) v1(224.83,137.55) v1(224.83,123.2) v1(224.82,89.17) v1(224.82,87.26) v1(224.82,85.36) v1(224.82,83.45) v1(224.82,81.55) v1(224.82,79.64) v1(224.82,77.86) v1(225.21,140.98) v1(225.2,134.71) v1(225.21,124.6) v1(225.21,120.66) v1(225.21,119.26) v1(225.21,117.87) v1(225.33,150.38) v1(225.33,131.2) v1(225.37,41.43) v1(225.37,37.62) v1(225.37,33.81) v1(225.37,30) v1(225.37,26.19) v1(225.37,22.38) v1(225.37,18.57) v1(225.37,14.76) v1(225.37,3.33) v1(225.46,122.18) v1(225.46,63.76) v1(225.39,7.09) v1(225.59,138.31) v1(225.97,139.58) v1(226.09,62.88) v1(226.21,148.35) v1(226.22,132.6) v1(226.22,129.93) v1(226.22,112.66) v1(226.22,64.78) v1(226.34,151.14) v1(226.35,145.93) v1(226.35,137.3) v1(226.35,136.03) v1(226.35,127.39) v1(226.35,102.63) v1(226.35,100.72) v1(226.35,96.91) v1(226.47,144.03) v1(226.47,142.25) v1(226.48,120.66) v1(226.48,116.47) v1(226.48,115.33) v1(226.48,114.06) v1(226.72,89.17) v1(226.72,87.26) v1(226.72,85.36) v1(226.72,83.45) v1(226.72,81.55) v1(226.72,79.64) v1(226.72,77.86) v1(226.86,122.18) v1(226.97,52.17) v1(227.11,150.38) v1(227.37,140.98) v1(227.37,139.58) v1(227.37,138.31) v1(227.74,146.57) v1(227.87,120.66) v1(227.87,64.27) v1(227.99,148.35) v1(228,112.66) v1(228,66.3) v1(227.99,62.88) v1(228.12,151.14) v1(228.13,136.79) v1(228.27,144.06) v1(228.27,142.32) v1(228.26,127.39) v1(228.26,116.85) v1(228.26,104.53) v1(228.26,102.63) v1(228.26,100.72) v1(228.26,98.82) v1(228.26,96.91) v1(228.19,1.54) v1(228.38,135.52) v1(228.38,134.12) v1(228.38,132.6) v1(228.38,131.07) v1(228.38,129.68) v1(228.38,125.61) v1(228.45,58.95) v1(228.51,122.31) v1(228.63,89.17) v1(228.63,87.26) v1(228.63,85.36) v1(228.63,83.45) v1(228.63,81.55) v1(228.63,79.64) v1(228.63,77.86) v1(228.76,140.73) v1(228.76,138.57) v1(228.76,115.45) v1(228.76,114.06) v1(228.89,150.38) v1(229,52.17) v1(229.14,120.02) v1(229.18,41.43) v1(229.18,37.62) v1(229.18,33.81) v1(229.18,30) v1(229.18,26.19) v1(229.18,22.38) v1(229.18,18.57) v1(229.18,14.76) v1(229.2,7.09) v1(229.18,3.33) v1(229.39,143.14) v1(229.52,148.35) v1(229.52,146.57) v1(229.53,106.44) v1(229.53,67.83) v1(229.78,141.11) v1(229.78,139.58) v1(229.78,137.8) v1(229.78,122.18) v1(229.78,64.02) v1(229.9,151.14) v1(229.91,65.54) v1(229.9,62.88) v1(230.16,134.12) v1(230.16,132.72) v1(230.16,98.82) v1(230.16,96.91) v1(230.41,116.98) v1(230.54,136.92) v1(230.54,129.68) v1(230.53,89.17) v1(230.53,87.26) v1(230.53,85.36) v1(230.53,83.45) v1(230.53,81.55) v1(230.53,79.64) v1(230.53,77.86) v1(230.67,150.38) v1(230.92,107.83) v1(231.04,143.14) v1(231.05,137.65) v1(231.05,114.82) v1(231.05,113.67) v1(231.18,128.03) v1(231.18,126.12) v1(231.18,122.18) v1(231.18,116.21) v1(231.29,148.35) v1(231.29,146.57) v1(231.3,130.95) v1(231.3,119.52) v1(231.43,123.83) v1(231.43,117.48) v1(231.56,145.55) v1(231.67,151.14) v1(231.8,62.88) v1(231.94,141.23) v1(231.94,114.56) v1(231.92,52.17) v1(232.07,96.91) v1(232.19,119.14) v1(232.19,108.98) v1(232.32,137.65) v1(232.44,89.17) v1(232.44,87.26) v1(232.44,85.36) v1(232.44,83.45) v1(232.44,81.55) v1(232.44,79.64) v1(232.45,64.14) v1(232.64,58.82) v1(232.69,150.38) v1(232.7,122.31) v1(232.83,131.07) v1(232.83,115.58) v1(232.95,133.11) v1(232.95,129.68) v1(233.07,146.57) v1(232.99,41.43) v1(232.99,37.62) v1(232.99,33.81) v1(232.99,30) v1(232.99,26.19) v1(232.99,22.38) v1(232.99,18.57) v1(232.99,14.76) v1(232.99,10.95) v1(232.99,7.14) v1(232.99,3.33) v1(233.08,128.03) v1(233.08,126.12) v1(233.08,123.96) v1(233.08,117.61) v1(233.34,110.12) v1(233.45,151.14) v1(233.46,139.71) v1(233.46,137.68) v1(233.46,136.03) v1(233.46,134.5) v1(233.39,103.13) v1(233.59,119.64) v1(233.71,62.88) v1(233.84,121.04) v1(233.84,116.72) v1(233.82,52.17) v1(234.1,67.7) v1(234.22,150.38) v1(234.22,79.77) v1(234.34,147.97) v1(234.35,140.98) v1(234.34,89.17) v1(234.34,87.26) v1(234.34,85.36) v1(234.34,83.45) v1(234.34,81.55) v1(234.48,111.39) v1(234.48,65.03) v1(234.54,1.42) v1(234.72,139.59) v1(234.73,128.41) v1(234.86,137.42) v1(234.86,135.52) v1(234.86,133.61) v1(234.86,131.71) v1(234.86,129.8) v1(234.86,126.63) v1(234.86,124.72) v1(234.86,122.82) v1(234.86,120.91) v1(234.86,119.64) v1(234.99,117.99) v1(235.1,147.08) v1(235.23,151.14) v1(235.24,108.59) v1(235.49,138.06) v1(235.62,63.76) v1(235.61,62.88) v1(235.75,112.66) v1(235.95,126.63) v1(235.88,103.51) v1(236,150.38) v1(236.13,138.69) v1(236.13,137.42) v1(236.13,135.52) v1(236.13,133.61) v1(236.13,131.71) v1(236.13,129.8) v1(236.13,128.53) v1(236.13,124.72) v1(236.13,122.82) v1(236.13,120.91) v1(236.13,118.88) v1(236.46,143.95) v1(236.45,58.82) v1(236.51,144.92) v1(236.59,148.01) v1(236.59,147) v1(236.59,145.98) v1(236.76,143.14) v1(236.76,141.87) v1(236.76,140.6) v1(236.76,139.33) v1(236.76,138.06) v1(236.76,136.79) v1(236.76,134.88) v1(236.76,132.98) v1(236.76,130.44) v1(236.76,129.17) v1(236.82,56.67) v1(236.8,52.86) v1(236.8,49.05) v1(236.8,45.24) v1(236.8,41.43) v1(236.8,37.62) v1(236.8,33.81) v1(236.8,30) v1(236.8,26.19) v1(236.8,22.38) v1(236.8,18.57) v1(236.8,14.76) v1(236.8,10.95) v1(236.8,7.14) v1(236.8,3.33) v1(237.01,151.14) v1(237.02,102.63) v1(237.14,149.11) v1(237.15,110.5) v1(237.15,108.59) v1(237.4,131.07) v1(237.4,123.96) v1(237.4,122.82) v1(237.4,121.55) v1(237.39,62.88) v1(237.65,147.92) v1(237.65,64.4) v1(237.91,150.38) v1(237.9,119.01) v1(238.03,141.87) v1(238.03,140.6) v1(238.03,139.33) v1(238.03,138.06) v1(238.03,136.79) v1(238.03,135.52) v1(238.03,134.25) v1(238.03,132.98) v1(238.03,131.71) v1(238.03,130.44) v1(238.03,129.42) v1(238.03,123.45) v1(238.03,122.18) v1(238.03,120.91) v1(238.45,148.25) v1(238.67,149.49) v1(238.67,124.09) v1(238.79,151.14) v1(239.04,122.19) v1(239.05,110.5) v1(239.05,108.59) v1(239.17,62.88) v1(239.17,146.9) v1(239.18,120.91) v1(239.18,119.14) v1(239.3,148.22) v1(239.3,64.65) v1(239.62,1.54) v1(239.69,150.38) v1(239.69,67.7) v1(239.69,66.3) v1(239.94,149.49) v1(240.19,145.68) v1(240.56,151.14) v1(240.57,148.22) v1(240.57,122.18) v1(240.57,120.91) v1(240.61,56.67) v1(240.61,52.86) v1(240.61,49.05) v1(240.61,45.24) v1(240.61,41.43) v1(240.61,37.62) v1(240.61,33.81) v1(240.61,30) v1(240.61,26.19) v1(240.61,22.38) v1(240.61,18.57) v1(240.61,14.76) v1(240.61,10.95) v1(240.61,7.14) v1(240.61,3.33) v1(240.96,110.5) v1(240.96,108.59) v1(240.95,62.88) v1(240.89,58.95) v1(241.08,84.21) v1(241.08,82.94) v1(241.21,149.49) v1(241.21,146.69) v1(241.21,145.89) v1(241.72,67.7) v1(241.76,1.31) v1(241.96,63.77) v1(242.1,146.95) v1(242.1,65.8) v1(242.23,147.84) v1(242.23,146.06) v1(242.48,121.55) v1(242.48,120.28) v1(242.48,119.01) v1(242.48,115.2) v1(242.48,113.93) v1(242.86,148.22) v1(242.99,145.55) v1(242.99,84.21) v1(242.99,82.94) v1(243.11,122.82) v1(243.11,115.83) v1(243.11,114.56) v1(243.11,113.29) v1(243.24,57.29) v1(243.75,148.47) v1(243.75,145.37) v1(244.25,119.01) v1(244.35,1.34) v1(244.38,124.09) v1(244.38,122.82) v1(244.38,121.55) v1(244.38,120.28) v1(244.38,115.83) v1(244.38,114.56) v1(244.38,113.29) v1(244.47,64.3) v1(244.42,56.67) v1(244.42,52.86) v1(244.42,49.05) v1(244.42,45.24) v1(244.42,41.43) v1(244.42,37.62) v1(244.42,33.81) v1(244.42,30) v1(244.42,26.19) v1(244.42,22.38) v1(244.42,18.57) v1(244.42,14.76) v1(244.42,10.95) v1(244.42,7.14) v1(244.42,3.33) v1(244.51,148.47) v1(244.51,145.37) v1(244.5,65.29) v1(244.58,2.28) v1(244.89,84.21) v1(244.89,82.94) v1(245.02,138.06) v1(245.02,136.79) v1(245.02,133.61) v1(245.02,132.34) v1(245.27,148.35) v1(245.27,145.42) v1(245.65,125.36) v1(245.65,124.09) v1(245.65,122.82) v1(245.65,121.55) v1(245.65,120.28) v1(245.65,119.01) v1(245.65,115.83) v1(245.65,114.56) v1(245.65,113.29) v1(245.78,105.17) v1(245.91,147.84) v1(245.91,145.93) v1(246.16,85.1) v1(246.29,119.64) v1(246.54,143.39) v1(246.54,142.12) v1(246.48,1.47) v1(246.72,132.22) v1(246.72,131.2) v1(246.72,128.79) v1(246.72,127.9) v1(246.8,147.84) v1(246.8,84.21) v1(246.8,82.94) v1(246.8,81.04) v1(246.8,65.16) v1(246.92,145.93) v1(246.92,115.83) v1(246.92,114.56) v1(246.92,113.29) v1(246.99,57.68) v1(247.18,126.88) v1(247.18,125.36) v1(247.18,124.09) v1(247.18,122.82) v1(247.18,121.55) v1(247.18,120.28) v1(247.3,150.13) v1(247.38,143.39) v1(247.56,105.17) v1(247.56,103.26) v1(247.68,151.14) v1(247.69,145.17) v1(247.81,147.71) v1(247.81,133.61) v1(247.94,134.5) v1(248.19,115.83) v1(248.19,114.56) v1(248.19,113.29) v1(248.19,85.1) v1(248.23,56.67) v1(248.23,52.86) v1(248.23,49.05) v1(248.23,45.24) v1(248.23,41.43) v1(248.23,37.62) v1(248.23,33.81) v1(248.23,30) v1(248.23,26.19) v1(248.23,22.38) v1(248.23,18.57) v1(248.23,14.76) v1(248.23,10.95) v1(248.23,7.14) v1(248.23,3.33) v1(248.3,144.51) v1(248.57,147.13) v1(248.58,75.7) v1(248.82,150.13) v1(248.83,83.58) v1(248.83,81.67) v1(248.82,65.04) v1(248.96,143.9) v1(249.07,1.36) v1(249.21,146.52) v1(249.45,151.14) v1(249.46,115.83) v1(249.46,114.56) v1(249.46,113.29) v1(249.46,105.17) v1(249.46,103.26) v1(249.59,143.27) v1(249.77,146.01) v1(249.79,147.33) v1(249.85,139.36) v1(249.85,138.31) v1(249.85,137.42) v1(249.85,75.7) v1(249.78,57.68) v1(250.1,117.1) v1(250.2,141.97) v1(250.6,150.13) v1(250.61,139.36) v1(250.61,138.31) v1(250.61,137.42) v1(250.73,147.72) v1(250.73,122.18) v1(250.73,120.91) v1(250.73,119.64) v1(250.73,118.37) v1(250.73,115.83) v1(250.73,114.56) v1(250.73,113.29) v1(250.73,85.48) v1(250.73,83.58) v1(250.73,81.67) v1(250.85,63.77) v1(251.23,151.14) v1(251.24,79.77) v1(251.37,121.55) v1(251.37,117.1) v1(251.37,105.17) v1(251.37,103.26) v1(251.37,75.7) v1(251.37,73.8) v1(251.37,71.89) v1(251.62,148.22) v1(251.62,65.41) v1(251.61,62.88) v1(251.79,1.36) v1(251.88,139.33) v1(251.88,138.31) v1(251.93,10.9) v1(252,146.19) v1(252,143.27) v1(251.98,141.94) v1(252,122.18) v1(252,120.91) v1(252,119.64) v1(252,118.37) v1(252.04,56.67) v1(252.04,52.86) v1(252.04,49.05) v1(252.04,45.24) v1(252.04,41.43) v1(252.04,37.62) v1(252.04,33.81) v1(252.04,30) v1(252.04,26.19) v1(252.04,22.38) v1(252.04,18.57) v1(252.04,14.76) v1(252.04,7.14) v1(252.04,3.33) v1(252.13,124.6) v1(252.26,147.71) v1(252.63,150.13) v1(252.64,125.36) v1(252.64,121.55) v1(252.64,87.39) v1(252.64,85.48) v1(252.64,83.58) v1(252.64,81.67) v1(252.64,79.77) v1(252.63,63.77) v1(252.89,147.08) v1(252.89,144.03) v1(253.01,151.14) v1(253.15,132.47) v1(253.15,131.45) v1(253.27,129.8) v1(253.27,124.72) v1(253.27,122.18) v1(253.27,120.91) v1(253.27,119.64) v1(253.27,118.37) v1(253.27,105.17) v1(253.27,103.26) v1(253.27,75.7) v1(253.27,73.8) v1(253.27,71.89) v1(253.34,1.54) v1(253.4,128.41) v1(253.39,62.88) v1(253.66,146.31) v1(253.66,142.5) v1(253.85,57.93) v1(253.91,148.85) v1(253.91,125.36) v1(253.91,121.55) v1(254.04,129.04) v1(254.16,141.61) v1(254.16,88.27) v1(254.29,143.14) v1(254.42,150.12) v1(254.42,85.35) v1(254.41,63.77) v1(254.67,131.07) v1(254.67,129.68) v1(254.74,58.82) v1(254.79,151.14) v1(254.8,143.65) v1(254.8,65.54) v1(255.18,148.85) v1(255.18,141.61) v1(255.18,127.26) v1(255.18,125.36) v1(255.18,105.04) v1(255.18,103.26) v1(255.18,84.08) v1(255.31,144.15) v1(255.31,123.71) v1(255.43,145.04) v1(255.56,145.81) v1(255.69,150.12) v1(255.74,11.15) v1(255.81,122.82) v1(255.85,56.67) v1(255.85,52.86) v1(255.85,49.05) v1(255.85,45.24) v1(255.85,41.43) v1(255.87,37.61) v1(255.85,33.81) v1(255.85,22.38) v1(255.85,14.76) v1(255.85,7.14) v1(255.85,3.33) v1(255.94,144.54) v1(255.94,141.74) v1(255.92,26.13) v1(256.07,151.14) v1(256.07,71.13) v1(256.07,69.99) v1(256.07,63.89) v1(256.2,146.31) v1(256.2,80.91) v1(256.2,79) v1(256.2,77.1) v1(256.45,148.85) v1(256.45,131.07) v1(256.45,129.17) v1(256.45,127.26) v1(256.45,125.36) v1(256.45,123.45) v1(256.45,122.18) v1(256.45,120.28) v1(256.45,119.01) v1(256.45,105.67) v1(256.58,143.9) v1(256.58,65.54) v1(256.96,132.09) v1(257.08,122.82) v1(257.08,121.55) v1(257.08,117.74) v1(257.08,103.26) v1(257.08,84.08) v1(257.21,147.33) v1(257.21,146.44) v1(257.21,143.27) v1(257.39,139.89) v1(257.47,80.91) v1(257.47,79) v1(257.47,77.1) v1(257.47,71.38) v1(257.59,147.96) v1(257.59,72.53) v1(257.72,148.85) v1(257.72,145.68) v1(257.72,123.45) v1(257.72,122.18) v1(257.72,105.04) v1(257.74,64.48) v1(257.85,142.63) v1(257.97,145.04) v1(258.04,7.89) v1(258.23,140.22) v1(258.35,148.35) v1(258.35,132.98) v1(258.35,131.07) v1(258.35,129.17) v1(258.35,127.26) v1(258.35,125.36) v1(258.35,122.82) v1(258.35,121.55) v1(258.35,120.28) v1(258.35,105.67) v1(258.55,58.82) v1(258.61,145.3) v1(258.61,144.54) v1(258.74,72.65) v1(258.77,63.2) v1(258.86,139.58) v1(258.86,73.92) v1(258.8,1.42) v1(258.99,123.45) v1(258.99,122.18) v1(258.99,119.01) v1(258.99,117.74) v1(258.99,109.48) v1(258.99,103.26) v1(259.06,11.45) v1(259.12,149.11) v1(259.5,139.07) v1(259.62,148.47) v1(259.62,137.68) v1(259.62,136.53) v1(259.62,122.82) v1(259.62,121.55) v1(259.62,110.75) v1(259.66,45.24) v1(259.66,41.43) v1(259.66,37.62) v1(259.66,33.81) v1(259.66,26.19) v1(259.66,22.38) v1(259.66,18.57) v1(259.66,14.76) v1(259.75,141.84) v1(259.75,135.26) v1(260.13,138.44) v1(260.1,133.95) v1(260.26,148.85) v1(260.26,132.98) v1(260.26,131.07) v1(260.26,129.17) v1(260.26,127.26) v1(260.26,125.36) v1(260.26,123.45) v1(260.26,122.18) v1(260.26,120.28) v1(260.26,118.37) v1(260.39,148.09) v1(260.41,142.15) v1(260.39,74.3) v1(260.72,140.88) v1(260.77,137.8) v1(260.82,136.51) v1(260.84,135.17) v1(260.89,147.46) v1(260.89,134.25) v1(260.89,122.82) v1(260.89,121.55) v1(260.89,109.48) v1(260.89,103.26) v1(261.02,146.69) v1(261.02,141.61) v1(261.15,148.09) v1(261.47,49.55) v1(261.53,148.85) v1(261.53,142.12) v1(261.5,137.35) v1(261.53,123.45) v1(261.53,122.18) v1(261.53,119.01) v1(261.68,146.34) v1(262.04,141.61) v1(262.16,147.2) v1(262.16,143.9) v1(262.16,136.53) v1(262.16,135.52) v1(262.16,134.25) v1(262.16,132.98) v1(262.16,131.07) v1(262.16,129.17) v1(262.16,127.26) v1(262.16,125.36) v1(262.16,122.82) v1(262.16,121.55) v1(262.16,109.48) v1(262.29,151.14) v1(262.42,139.2) v1(262.47,137.5) v1(262.55,150.12) v1(262.54,71.89) v1(262.67,147.96) v1(262.67,146.31) v1(262.8,148.85) v1(262.82,138.34) v1(262.8,123.45) v1(262.8,122.18) v1(262.8,120.28) v1(262.8,108.21) v1(263.25,11.19) v1(263.31,147.2) v1(263.43,139.2) v1(263.43,136.53) v1(263.43,135.52) v1(263.43,134.25) v1(263.43,132.98) v1(263.43,131.07) v1(263.43,129.17) v1(263.43,127.26) v1(263.43,125.36) v1(263.43,122.82) v1(263.43,121.55) v1(263.43,119.01) v1(263.47,45.24) v1(263.47,41.43) v1(263.47,37.62) v1(263.47,33.81) v1(263.47,30) v1(263.47,26.19) v1(263.47,22.38) v1(263.47,18.57) v1(263.47,14.76) v1(263.56,143.9) v1(263.68,151.14) v1(263.69,146.31) v1(263.82,148.09) v1(263.82,145.55) v1(263.82,144.54) v1(264.07,150.12) v1(264.07,148.85) v1(264.07,123.45) v1(264.07,122.18) v1(264.07,109.48) v1(264.07,108.21) v1(264.06,72.4) v1(264.06,62.88) v1(264.45,147.84) v1(264.45,146.82) v1(264.45,139.2) v1(264.58,142.88) v1(264.7,149.49) v1(264.7,137.42) v1(264.7,136.15) v1(264.7,134.88) v1(264.7,133.61) v1(264.7,132.34) v1(264.7,131.07) v1(264.7,129.8) v1(264.7,123.96) v1(264.7,122.82) v1(264.7,121.55) v1(264.7,120.28) v1(264.9,47.77) v1(265.09,110.4) v1(265.08,103.64) v1(265.34,150.12) v1(265.34,148.85) v1(265.34,147.84) v1(265.34,139.33) v1(265.34,138.06) v1(265.34,136.79) v1(265.34,135.52) v1(265.34,134.25) v1(265.34,132.98) v1(265.34,131.71) v1(265.34,130.44) v1(265.34,129.3) v1(265.34,123.45) v1(265.34,122.18) v1(265.34,119.01) v1(265.34,108.21) v1(265.33,89.93) v1(265.33,88.15) v1(265.33,86.37) v1(265.33,84.59) v1(265.33,82.82) v1(265.33,81.29) v1(265.34,79.13) v1(265.33,71.39) v1(265.46,151.14) v1(265.72,142.38) v1(265.72,141.61) v1(265.85,95.13) v1(265.85,76.97) v1(265.85,75.19) v1(265.85,73.42) v1(265.84,62.88) v1(265.79,51.2) v1(265.79,45.48) v1(265.79,14.75) v1(265.79,11.96) v1(265.79,8.65) v1(265.91,48.79) v1(265.97,149.49) v1(265.97,148.22) v1(265.97,139.96) v1(265.97,138.69) v1(265.97,137.42) v1(265.97,136.15) v1(265.97,134.88) v1(265.97,133.61) v1(265.97,132.34) v1(265.97,131.07) v1(265.97,129.8) v1(265.97,128.53) v1(265.97,124.09) v1(265.97,122.82) v1(265.97,121.55) v1(265.97,109.48) v1(265.97,101.36) v1(265.97,99.96) v1(266.36,110.88) v1(266.42,1.16) v1(266.57,78.83) v1(266.55,58.82) v1(266.6,150.63) v1(266.61,148.85) v1(266.61,147.58) v1(266.6,137.05) v1(266.6,135.27) v1(266.61,132.98) v1(266.6,131.71) v1(266.61,129.17) v1(266.61,127.9) v1(266.61,126.5) v1(266.6,124.6) v1(266.61,122.18) v1(266.6,121.04) v1(266.6,119.27) v1(266.61,117.1) v1(266.6,97.93) v1(266.6,96.15) v1(266.6,94.37) v1(266.6,92.6) v1(266.6,90.82) v1(266.6,89.04) v1(266.6,87.26) v1(266.6,85.48) v1(266.6,83.71) v1(266.6,81.93) v1(266.6,80.15) v1(266.6,64.15) v1(266.64,41.43) v1(266.63,34.34) v1(266.64,30) v1(266.64,26.19) v1(266.64,22.38) v1(266.64,18.57) v1(266.78,38.48) v1(266.93,7.64) v1(267.12,111.77) v1(267.12,110.25) v1(267.17,69.4) v1(267.23,151.14) v1(267.23,150) v1(267.23,148.22) v1(267.23,137.55) v1(267.23,135.78) v1(267.23,134) v1(267.23,132.22) v1(267.23,130.44) v1(267.23,128.66) v1(267.23,126.89) v1(267.23,125.11) v1(267.23,123.33) v1(267.23,121.55) v1(267.23,119.77) v1(267.23,118) v1(267.23,112.66) v1(267.24,99.7) v1(267.23,98.44) v1(267.23,96.66) v1(267.23,94.88) v1(267.23,93.1) v1(267.23,91.33) v1(267.23,89.55) v1(267.23,87.77) v1(267.23,85.99) v1(267.23,84.21) v1(267.23,82.44) v1(267.23,80.66) v1(267.21,79.34) v1(267.23,64.66) v1(267.23,62.88) v2(168.95,88.02)
